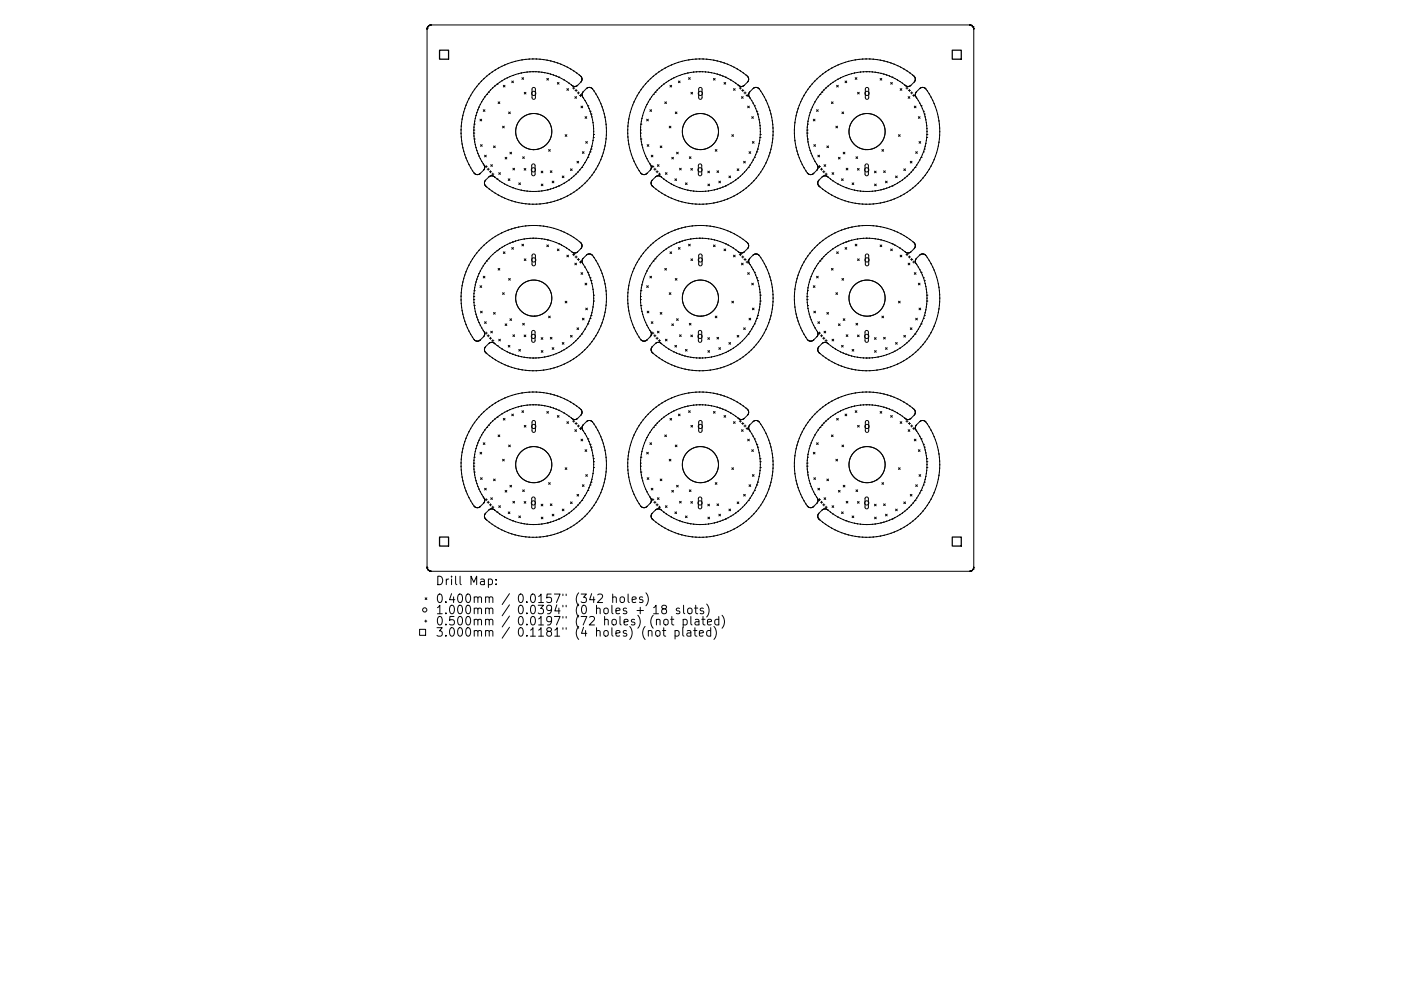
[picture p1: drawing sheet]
<svg xmlns="http://www.w3.org/2000/svg" width="297mm" height="210mm" viewBox="0 0 297 210" stroke-linecap="round" stroke-linejoin="round" font-family="sans-serif">
<defs><g id="words">
<g font-size="2.5">
<text x="92.3" y="124.1">Drill Map:</text>
<text x="92.3" y="127.9">0.400mm / 0.0157&quot; (342 holes)</text>
<text x="92.3" y="130.3">1.000mm / 0.0394&quot; (0 holes + 18 slots)</text>
<text x="92.3" y="132.7">0.500mm / 0.0197&quot; (72 holes) (not plated)</text>
<text x="92.3" y="135.1">3.000mm / 0.1181&quot; (4 holes) (not plated)</text>
</g>
</g></defs>
<g fill="none" stroke="#000" stroke-width=".21">
<path d="M90.5 6.2v114.1M90.5 6.2h.1M90.5 6.1v.1M90.6 6.1h-.1M90.6 6h.1M90.6 6v.1M90.6 5.9v.1M90.6 5.9h.1M90.6 5.8h.1M90.7 5.8h.1M90.7 5.7h.1M90.7 5.7v.1"/>
<path d="M90.7 5.6h.1M90.7 5.6v.1M90.8 5.6h.1M90.9 5.5l-.1 .1M90.9 5.5h.1M90.9 5.4h.1M91 5.4h.1M91.1 5.4h.1M91.1 5.4h-.1M91.2 5.3l-.1 .1M91.2 5.3h.1M91.3 5.3h-.1"/>
<path d="M91.3 5.3h.1M91.4 5.3h.1M91.4 5.3h-.1M91.5 5.3h-.1M100.1 19.7l-.3 .5M100.2 19.7h-.1M100.2 19.6v.1M100.2 19.5v.1M100.6 19l-.4 .5M100.6 19h.1M100.6 18.9v.1M100.7 18.9h-.1"/>
<path d="M102 17.3l-1.3 1.6M102 17.3h.1M102.6 16.7l-.6 .6M102.6 16.7h.1M102.7 16.6l-.1 .1M102.7 16.6h.1M103.6 19.6h.1M103.6 19.6l-.4 .4M103.7 15.7l-1 .9M103.7 15.7h.1M104 19.1l-.4 .5M104 19.1h.1"/>
<path d="M104.5 18.7h.1M104.5 18.7l-.5 .4M104.9 18.2l-.4 .4M104.9 18.2h.1M105.4 17.8h.1M105.4 17.8l-.5 .4M105.6 14.5l-1.9 1.2M105.6 14.5h.1M105.7 14.4l-.1 .1M105.7 14.4h.1M105.9 17.5h.1M105.9 17.5l-.5 .3"/>
<path d="M106.4 17.1l-.5 .4M106.4 17.1h.1M106.5 17.1h.1M106.5 17.1h-.1M106.7 18.1l.4 .4M107 16.8l-.5 .3M107 16.8h.1M107.1 18.1l-.4 .4M107.1 13.7l-1.4 .7M107.1 13.7h.1M107.5 16.5h.1M107.5 16.5l-.5 .3"/>
<path d="M107.6 16.5h-.1M107.6 16.5h.1M107.7 13.5l-.6 .2M107.7 13.5h.1M107.8 13.5h-.1M107.8 13.5h.1M108.1 16.3l-.5 .2M108.1 16.2h.1M108.5 17.2l.4 .3M108.5 13.2l-.7 .3M108.5 13.2h.1M108.7 16h.1"/>
<path d="M108.7 16l-.6 .2M108.9 17.2l-.4 .3M109.1 13l-.6 .2M109.2 13h-.1M109.3 15.8l-.6 .2M109.3 15.8h.1M109.9 12.9l-.7 .1M109.9 15.6l-.6 .2M109.9 15.6h.1M109.9 12.9h.1M110.5 15.5l-.6 .1M110.5 15.5h.1"/>
<path d="M110.6 12.7l-.7 .2M110.6 12.7h.1M110.7 16.5l.3 .3M111 16.5l-.3 .3M111.2 19.6l.3 .3M111.5 12.6l-.9 .1M111.5 19.6l-.3 .3M111.5 12.6h.1M112.1 12.5l-.6 .1M112.2 12.5h-.1M112.4 15.2l-1.9 .3M112.4 15.2h.1"/>
<path d="M112.9 12.5h-.7M112.9 18.7l.4-.1 .2 .3v1.9l-.3 .3-.4-.4zM112.9 12.5h.9M112.9 12.5h.1M113 15.2h.1M113 15.2h-.6M113 15.2h.6M113.6 15.2h.1M113.6 15.2l.7 .1M113.8 12.5h.1M113.8 12.5l.6 .1M114.3 15.3h.1"/>
<path d="M114.3 15.3l1.2 .1M114.4 12.6h.1M114.4 12.6h.8M115.2 12.6h.1M115.2 12.6l.9 .2M115.5 15.4h.1M115.5 15.4l.6 .2M115.9 16.6l.4 .4M116.1 12.8h.1M116.1 12.8l.7 .1M116.1 15.6h.1M116.1 15.6l.6 .1"/>
<path d="M116.3 16.6l-.4 .4M116.7 15.7h.1M116.7 15.7l.6 .2M116.8 12.9h.1M116.8 12.9l.7 .2M117.3 15.9h.1M117.3 15.9l.6 .2M117.5 13.1h.1M117.6 13.1l2 .8M117.9 16.1h.1M117.9 16.1l.6 .3M118.2 17.5l.3 .4"/>
<path d="M118.5 16.4h.1M118.5 16.4l.6 .3M118.5 17.5l-.3 .4M119.1 16.7h.1M119.1 16.7l.5 .3M119.6 13.9h.1M119.6 17h.1M119.6 17l.5 .3M119.7 13.9v.1M119.7 14l.7 .3M120.1 17.3h.1M120.2 17.3h.1"/>
<path d="M120.2 17.3l.5 .3M120.2 18.8l.3 .4M120.4 14.3h.1M120.4 14.3l1.3 .8M120.5 18.8l-.3 .4M120.7 17.6h.1M120.7 17.6v.1M120.7 17.7h.1M120.7 17.7l.5 .3M121.2 18h.1M121.2 18l.1 .2M121.3 18.2h.1"/>
<path d="M121.4 18.7h.5M121.4 18.2l.1 .1M121.5 18.3h.1M121.6 18.3h.1M121.6 18.5v.4M121.7 18.3h.2M121.7 15.1h.1M121.7 15.1l1.1 .8M121.9 19.2h.5M121.9 18.3h.1M122.1 19v.4M122.1 18.3h-.2"/>
<path d="M122.2 18.3h-.1M122.4 19.7h.5M122.4 18.1l-.2 .2M122.5 18.1h-.1M122.6 19.5v.4M122.8 15.9h.1M122.8 15.9l.3 .3M123.1 16.2h.1M123.1 16.2l.2 .2M123.2 17.4l-.7 .7M123.2 17.4h.1M123.3 16.4h.1"/>
<path d="M123.3 16.4v.1M123.3 16.5l.1 .1M123.4 16.6v.1M123.4 17l-.2 .4M123.4 16.9v.1M123.4 16.7v.1M123.4 16.8v.1M123.4 20v.2M123.4 19.9v.1M123.4 19.8v.1M123.5 19.7l-.1 .1M123.6 19.5l-.1 .2"/>
<path d="M123.6 19.5h.1M124.5 18.7l-.9 .8M124.5 18.6v.1M124.7 18.6h-.2M124.7 18.6h.1M124.9 18.5l-.2 .1M125 18.5l.3 .1M125 18.5h-.1M125.3 18.6l.1 .1M125.4 18.7l.5 .5M125.9 19.2h.1M125.9 19.2l.1 .1"/>
<path d="M126 19.3v.1M126 19.4l.3 .5M126.3 19.9h.1M126.3 19.9l.7 1.3M135.5 19.7l-.3 .5M135.5 19.7h.1M135.5 19.6v.1M135.6 19.5l-.1 .1M135.9 19l-.3 .5M135.9 19h.1M137.3 17.3l-1.4 1.7M137.4 17.3h-.1"/>
<path d="M137.4 17.2v.1M137.5 17.2h-.1M138.5 16.2l-1 1M138.5 16.2h.1M138.9 19.6h.1M138.9 19.6l-.4 .4M139.3 19.1l-.4 .5M139.4 19.1h-.1M139.8 15.2l-1.3 1M139.8 15.2h.1M139.8 18.7h.1M139.8 18.7l-.4 .4"/>
<path d="M139.8 18.6h.1M139.8 18.6v.1M140.3 18.2l-.5 .4M140.3 18.2h.1M140.4 14.8l-.6 .4M140.4 14.8h.1M140.7 17.8h.1M140.7 17.8l-.4 .4M140.8 17.8h.1M140.8 17.8h-.1M140.9 14.5l-.5 .3M141 14.5h-.1"/>
<path d="M141.3 17.5h.1M141.3 17.5l-.5 .3M141.6 14.1l-.6 .4M141.6 14.1h.1M141.7 14.1h-.1M141.8 14.1h-.1M141.8 17.1l-.5 .4M141.8 17.1h.1M142 18.1l.4 .4M142.3 13.8l-.5 .3M142.3 16.8l-.5 .3M142.3 13.8h.1"/>
<path d="M142.3 16.8h.1M142.4 18.1l-.4 .4M142.9 16.5h.1M142.9 16.5l-.6 .3M143.1 13.5l-.8 .3M143.2 13.5h-.1M143.4 16.3h.1M143.4 16.3l-.5 .2M143.5 16.2h.1M143.5 16.2l-.1 .1M143.7 13.3l-.5 .2M143.8 13.3h-.1"/>
<path d="M143.8 17.2l.4 .3M144 16h.1M144 16l-.5 .2M144.2 17.2l-.4 .3M144.5 13l-.7 .3M144.5 13h.1M144.6 13h-.1M144.6 13h.1M144.6 15.8l-.6 .2M144.6 15.8h.1M145.2 15.6h.1M145.2 15.6l-.6 .2"/>
<path d="M145.3 12.8l-.7 .2M145.4 12.8h-.1M145.8 15.5l-.6 .1M145.8 15.5h.1M145.9 15.5h.1M145.9 15.5h-.1M146 12.7l-.6 .1M146 12.7h.1M146 16.5l.3 .3M146.3 16.5l-.3 .3M146.5 15.4l-.6 .1M146.5 15.4h.1"/>
<path d="M146.5 19.6l.3 .3M146.7 12.6l-.7 .1M146.7 12.6h.1M146.8 19.6l-.3 .3M147.1 15.3l-.6 .1M147.1 15.3h.1M147.6 12.5l-.9 .1M147.6 12.5h.1M147.7 15.2l-.6 .1M147.7 15.2h.1M148.2 12.5h-.6M148.2 18.7l.4-.1 .3 .3-.1 1.9-.3 .3-.4-.4z"/>
<path d="M148.3 12.5h-.1M148.3 15.2h.1M148.3 15.2h-.6M148.4 15.2h.1M148.4 15.2h-.1M148.4 15.2l1.8 .1M148.4 12.5h-.1M148.4 12.5h.1M148.4 12.5h.6M149 12.5h.1M149 12.5l.9 .1M149.9 12.6h.1"/>
<path d="M149.9 12.6h.6M150.2 15.3h.1M150.2 15.3l.6 .1M150.5 12.6h.1M150.5 12.6l.8 .2M150.8 15.4h.1M150.9 15.4l.5 .2M151.3 16.6l.3 .4M151.3 12.8h.1M151.3 12.8l.7 .1M151.4 15.6h.1M151.5 15.6h.1"/>
<path d="M151.5 15.6l.6 .1M151.6 16.6l-.3 .4M152 12.9h.1M152 12.9l.7 .2M152.1 15.7h.1M152.1 15.7l.6 .2M152.7 15.9h.1M152.7 15.9l1.1 .5M152.7 13.1h.1M152.8 13.1l.8 .3M153.5 17.5l.4 .4M153.6 13.4h.1"/>
<path d="M153.6 13.4l1.4 .5M153.8 16.4h.1M153.8 16.4l.6 .3M153.9 17.5l-.4 .4M154.4 16.7h.1M154.4 16.7l.5 .3M155 17h.1M155 17l.5 .3M155 13.9v.1M155 14l1.9 1M155.5 17.3h.1M155.5 17.3l.5 .3"/>
<path d="M155.5 18.8l.4 .4M155.9 18.8l-.4 .4M156 17.6v.1M156 17.7l.5 .3M156.5 18h.1M156.5 18l.2 .2M156.7 18.2h.1M156.7 18.7h.5M156.8 18.2l.1 .1M156.9 18.3h.1M156.9 15h.1M156.9 15l.6 .4"/>
<path d="M156.9 18.3h.2M157 18.5v.4M157.1 18.3h.1M157.3 19.2h.4M157.5 19v.4M157.5 15.4h.1M157.5 15.4l1.2 1.1M157.7 19.7h.5M158 19.5v.4M158.6 17.3l-.9 .9-.5 .1M158.6 17.3h.1M158.6 17.2v.1"/>
<path d="M158.7 17.1l-.1 .1M158.7 16.5v.1M158.7 16.6v.1M158.7 17v.1M158.7 16.9v.1M158.7 16.7v.1M158.7 16.8v.1M158.7 20v.2M158.7 19.9v.1M158.8 19.8l-.1 .1M158.8 19.7v.1M158.9 19.6l-.1 .1"/>
<path d="M158.9 19.6h.1M159.7 18.8l-.8 .8M159.7 18.7v.1M159.9 18.6l-.2 .1M160 18.6h-.1M160.2 18.6h-.2M160.2 18.5l.2 .1M160.2 18.5v.1M160.4 18.6h.1M160.5 18.6l.4 .2M160.9 18.8h.1M161 18.8v.1"/>
<path d="M161 18.9l.2 .3M161.2 19.2h.1M161.2 19.2l.1 .1M161.3 19.3v.1M161.3 19.4l.3 .5M161.6 19.9h.1M161.7 19.9v.1M161.7 20h.1M170.9 19.6l-1.1 2M170.9 19.5v.1M171.3 18.9l-.4 .6M171.3 18.9h.1"/>
<path d="M172.7 17.3l-1.4 1.6M172.7 17.3h.1M172.8 17.2l-.1 .1M172.8 17.2h.1M173.2 16.7l-.4 .5M173.2 16.7h.1M173.3 16.6l-.1 .1M173.3 16.6h.1M173.8 16.2l-.5 .4M173.8 16.2h.1M174.2 19.6h.1M174.2 19.6l-.3 .4"/>
<path d="M174.3 19.6h-.1M174.3 19.6h.1M174.4 15.7l-.6 .5M174.4 15.7h.1M175.1 18.7l-.8 .9M175.1 18.7h.1M175.6 18.2l-.5 .4M175.6 18.2h.1M175.7 14.8l-1.3 .9M175.8 14.8h-.1M176.1 17.8h.1M176.1 17.8l-.5 .4"/>
<path d="M176.3 14.5l-.5 .3M176.3 14.5h.1M176.4 14.4l-.1 .1M176.4 14.4h.1M176.6 17.5h.1M176.6 17.5l-.5 .3M177.1 14.1l-.7 .3M177.1 14.1h.1M177.1 17.1l-.5 .4M177.1 17.1h.1M177.4 18.1l.3 .4M177.7 16.8l-.6 .3"/>
<path d="M177.7 16.8h.1M177.7 18.1l-.3 .4M177.8 13.7l-.7 .4M177.8 13.7h.1M178.2 16.5l-.5 .3M178.2 16.5h.1M178.3 13.5l-.5 .2M178.4 13.5h-.1M178.8 16.3l-.6 .2M178.8 16.2v.1M179.2 17.2l.3 .3M179.2 13.2l-.8 .3"/>
<path d="M179.2 13.2h.1M179.4 16h.1M179.4 16l-.6 .2M179.5 17.2l-.3 .3M179.9 13l-.7 .2M179.9 13h.1M180 15.8l-.6 .2M180 15.8h.1M180.6 15.6h.1M180.6 15.6l-.6 .2M180.7 12.8l-.8 .2M180.7 12.8h.1"/>
<path d="M181.2 15.5l-.6 .1M181.2 15.5h.1M181.3 16.5l.4 .3M181.4 12.7l-.7 .1M181.4 12.7h.1M181.7 16.5l-.4 .3M181.8 15.4l-.6 .1M181.8 15.4h.1M181.8 19.6l.4 .3M182.2 12.6l-.8 .1M182.2 19.6l-.4 .3M182.2 12.6h.1"/>
<path d="M182.8 12.5l-.6 .1M182.8 12.5h.1M183.6 18.7l.3-.1 .3 .3v1.9l-.3 .3-.4-.4zM183.7 15.2l-1.9 .2M183.7 15.2h.1M183.7 15.2h.6M183.7 12.5h-.9M183.7 12.5h.1M183.7 12.5h.6M184.3 15.2h.1M184.3 15.2l.6 .1M184.3 12.5h.1"/>
<path d="M184.3 12.5h.2M184.5 12.5h.1M184.5 12.5l.6 .1M184.9 15.3h.1M184.9 15.3h.6M185.1 12.6h.1M185.1 12.6l.9 .1M185.5 15.3h.1M185.6 15.3l1.2 .3M186 12.7h.1M186 12.7l.7 .1M186.6 16.6l.4 .4"/>
<path d="M186.7 12.8h.1M186.8 12.8l.5 .1M186.8 15.6h.1M186.8 15.6l.6 .1M187 16.6l-.4 .4M187.3 12.9h.1M187.4 12.9h.1M187.4 15.7h.1M187.4 15.7l.6 .2M187.5 12.9h.1M187.5 12.9l.7 .2M188 15.9h.1"/>
<path d="M188 15.9l.6 .2M188.2 13.1h.1M188.2 13.1l.7 .3M188.6 16.1h.1M188.6 16.1l.6 .3M188.8 17.5l.4 .4M188.9 13.4h.1M189 13.4l1.2 .5M189.2 16.4h.1M189.2 16.4l.5 .3M189.2 17.5l-.4 .4M189.7 16.7h.1"/>
<path d="M189.7 16.7l.6 .3M190.2 13.9h.1M190.2 13.9l.8 .4M190.3 17h.1M190.3 17l.5 .3M190.8 17.3h.1M190.8 17.3l.5 .3M190.8 18.8l.4 .4M191 14.3h.1M191.1 14.3l1.1 .7M191.2 18.8l-.4 .4M191.3 17.6h.1"/>
<path d="M191.3 17.6v.1M191.3 17.7h.1M191.3 17.7l.5 .3M191.8 18h.1M191.8 18l.5 .3M192.1 18.7h.4M192.2 15h.1M192.2 15l.1 .1M192.3 18.5v.4M192.3 18.3h.1M192.3 15.1h.1M192.4 15.1l.5 .3"/>
<path d="M192.4 18.3h.2M192.6 19.2h.4M192.6 18.3h.1M192.8 19v.4M192.9 18.3h-.3M192.9 15.4h.1M192.9 15.4l.6 .5M192.9 18.3h.1M193.1 19.7h.4M193.1 18.1l-.2 .2M193.1 18.1h.1M193.3 19.5v.4"/>
<path d="M193.5 15.9h.1M193.5 15.9l.4 .3M193.8 17.4l-.7 .7M193.9 17.4h-.1M193.9 16.2v.1M193.9 16.3v.1M193.9 16.4h.1M194 16.4l.1 .3M194 17.2l-.1 .2M194 17.1v.1M194 17v.1M194.1 16.9l-.1 .1"/>
<path d="M194.1 16.7v.1M194.1 16.8v.1M194.2 19.6l-.1 .6M194.2 19.6h.1M195.1 18.7l-.9 .9M195.1 18.7h.1M195.4 18.6l-.3 .1M195.4 18.6h.1M195.6 18.5l-.2 .1M195.6 18.5h.1M195.7 18.5l.2 .1M195.9 18.6h.1"/>
<path d="M195.9 18.6l.1 .1M196 18.7h.1M196.1 18.7l.5 .6M196.6 19.3l.1 .1M196.7 19.4l.3 .5M197 19.9h.1M197 19.9v.1M197 20h.1M205.5 5.3h-114.1M205.6 5.3h.1M205.7 5.3h.1M205.8 5.3h.1"/>
<path d="M205.8 5.3l.1 .1M205.9 5.4h.1M206 5.4h.1M206.1 5.4h.1M206.1 5.5h.1M206.1 5.5l.1 .1M206.2 5.6h.1M206.3 5.6v.1M206.3 5.7h.1M206.3 5.7v.1M206.4 5.8h.1M206.4 5.8v.1"/>
<path d="M206.4 5.9h.1M206.4 5.9v.1M206.4 6h.1M206.4 6l.1 .1M206.5 6.1h.1M206.5 6.1v.1M206.5 6.2v114.1M206.5 6.2h.1M97.8 27.6v.8M97.8 27.6h.1M97.8 28.4h.1M97.8 27.5v.1"/>
<path d="M97.8 28.4v.6M97.8 27.5h.1M97.8 29h.1M97.8 29l.1 .9M97.8 26.7v.8M97.8 26.7h.1M97.9 26.1l-.1 .6M97.9 26.1h.1M97.9 29.9h.1M97.9 29.9l.1 .7M98 25.3l-.1 .8M98 25.3h.1"/>
<path d="M98 30.6h.1M98 30.6l.1 .8M98.1 24.6l-.1 .7M98.1 24.6h.1M98.1 24.5v.1M98.1 31.4h.1M98.2 24.4l-.1 .1M98.2 31.4l.1 .7M98.3 23.8l-.1 .6M98.3 23.8h.1M98.3 32.1h.1M98.3 32.1l.8 2"/>
<path d="M98.5 23.1l-.2 .7M98.5 23.1h.1M99.1 21.7l-.6 1.4M99.1 34.1v.1M99.1 34.2l.3 .6M99.1 21.7h.1M99.1 21.6v.1M99.1 21.6h.1M99.4 21l-.3 .6M99.4 34.8h.1M99.4 34.8l.3 .7M99.4 21h.1"/>
<path d="M99.4 20.9v.1M99.5 20.9h-.1M99.7 35.5h.1M99.8 35.5v.1M99.8 20.2l-.3 .7M99.8 35.6h.1M99.8 35.6l.7 1.1M99.8 20.2h.1M100.5 27.6v.6M100.5 27.6h.1M100.5 28.2h.1M100.5 28.2l.1 1.3"/>
<path d="M100.5 36.7h.1M100.5 27v.6M100.5 27h.1M100.5 36.7l.2 .2M100.6 26.4l-.1 .6M100.6 29.5h.1M100.6 26.3h.1M100.6 29.5v.6M100.6 30.1h.1M100.6 30.1l.3 1.2M100.7 36.9h.1M100.8 25.1l-.2 1.2"/>
<path d="M100.8 25.1h.1M100.8 36.9v.1M100.8 37h.2M100.9 31.3h.1M100.9 24.5l-.1 .6M100.9 24.5h.1M100.9 31.3l.2 .6M101 37h.1M101 37h.2M101.1 23.9h.1M101.1 31.9h.1M101.1 23.9l-.2 .6"/>
<path d="M101.1 31.9l.2 .6M101.3 37h-.1M101.3 23.3h.1M101.3 32.5h.1M101.3 23.3l-.2 .6M101.3 32.5l.3 .6M101.4 37h-.1M101.5 37h-.1M101.6 33.1h.1M101.6 22.7l-.3 .6M101.6 33.1l.2 .6M101.6 22.7h.1"/>
<path d="M101.6 37h-.1M101.6 36.9v.1M101.8 25.3l.3 .4M101.8 33.7h.1M101.8 22.2l-.2 .5M101.8 22.2h.1M101.8 33.7l.3 .5M101.9 30.7l.3 .3M102.1 34.2h.1M102.1 25.3l-.3 .4M102.1 34.2l.4 .6M102.2 30.7l-.3 .3"/>
<path d="M102.5 21.1l-.7 1.1M102.5 21.1h.1M102.5 23.3l.3 .3M102.5 34.8h.1M102.5 34.8l.2 .3M102.7 35.1h.1M102.7 35.1v.2M102.7 38.9h.1M102.7 38.9l.1 .2M102.7 35.8l-1.1 1.1M102.7 38.7v.2M102.7 38.7h.1"/>
<path d="M102.7 35.8h.1M102.7 32.9l.4 .4M102.7 35.3h.1M102.7 35.3l.1 .2M102.8 39.1v.1M102.8 35.5l-.1 .3M102.8 35.5h.1M102.8 38.5l-.1 .2M102.8 39.2l.1 .2M102.8 38.5h.1M102.8 20.6l-.3 .5M102.8 20.5h.1"/>
<path d="M102.8 23.3l-.3 .3M102.9 35.3h.4M102.9 38.3l-.1 .2M102.9 38.3h.1M102.9 39.4h.1M102.9 39.4l.1 .1M103 39.5h.1M103 39.5l.8 .7M103.1 35.1v.5M103.1 32.9l-.4 .4M103.2 20.1l-.4 .4M103.2 20h.1"/>
<path d="M103.3 35.9h.4M103.5 35.7v.4M103.8 37.4l-.9 .9M103.8 36.4h.4M103.8 37.4h.1M103.9 37.4h-.1M103.9 37.4h.1M104 36.2v.5M104 34.9l.4 .4M104.1 37.3l-.2 .1M104.1 37.3h.1M104.3 36.9h.4"/>
<path d="M104.3 37.3h-.2M104.3 37.3h.1M104.3 37.3l.4 .1M104.4 34.9l-.4 .4M104.5 36.7v.5M104.6 31l.4 .3M104.7 37.4h.1M104.7 37.4l.1 .1M104.8 37.5h.1M104.8 37.5l.1 .1M104.9 37.6h.1M104.9 37.6l.5 .4"/>
<path d="M105 31l-.4 .3M105.4 38h.1M105.4 38l.5 .4M105.6 21.6l.4 .4M105.7 36.6l.4 .4M105.9 38.4h.1M105.9 38.4l.5 .3M106 21.6l-.4 .4M106.1 36.6l-.4 .4M106.4 38.7h.1M106.5 38.7h.1M106.5 38.7l.5 .3"/>
<path d="M106.6 26.8l.3 .3M106.9 26.8l-.3 .3M107 39h.1M107 39l.5 .3M107.1 33.4l.4 .3M107.5 33.4l-.4 .3M107.5 39.3h.1M107.6 39.3l.5 .3M107.8 37.9l.3 .4M107.8 23.8l.4 .3M108.1 32.3l.4 .4M108.1 37.9l-.3 .4"/>
<path d="M108.1 39.6h.1M108.1 39.6l.6 .2M108.2 23.8l-.4 .3M108.5 32.3l-.4 .4M108.7 39.8h.1M108.7 39.8l.6 .2M108.7 35.7l.4 .4M109.1 35.7l-.4 .4M109.3 28.2h.1M109.3 28.2l.4 1.3 .7 1.1M110 38.8l.4 .4M110.4 38.8l-.4 .4"/>
<path d="M110.4 30.6h.1M110.4 30.6l.4 .3M110.8 30.9v.1M110.8 33.3l.4 .3M110.8 31l.5 .3M111.1 35.7l.4 .4M111.2 33.3l-.4 .3M111.3 31.3h.1M111.3 31.3l1 .4M111.5 24.5l-1 .6-.6 .9-.5 1-.1 1.2M111.5 35.7l-.4 .4M111.5 24.5h.1"/>
<path d="M112 24.3l-.5 .2M112 24.3h.1M112.3 24.2l-.3 .1M112.3 31.7h.1M112.4 24.2h-.1M112.7 24.1l-.3 .1M112.8 24.1h.9l.9 .3M112.8 24.1h-.1M112.8 34.9l.4-.1 .2 .3v1.9l-.3 .3-.4-.3zM114.6 31.5l-1.1 .2h-1.1M114.6 24.4h.1M114.6 24.4l1.1 .6"/>
<path d="M114.6 31.5h.1M114.7 36.3l.4 .4M114.8 39.1l.3 .3M115.1 36.3l-.4 .4M115.1 39.1l-.3 .3M115.7 25v.1M115.7 25.1l.8 .9 .4 1M116.2 30.2l-.6 .7-1 .6M116.2 30.2h.1M116.3 31.7l.4 .4M116.3 30.1l-.1 .1M116.4 30l-.1 .1"/>
<path d="M116.4 29.9v.1M116.5 29.9h-.1M116.7 31.7l-.4 .4M116.7 36.2l.3 .4M116.9 27h.1M116.9 27l.1 1.5-.5 1.4M117 36.2l-.3 .4M117.1 38.4l.3 .4M117.3 39.9l-.6 .2M117.3 39.9h.1M117.4 38.4l-.3 .4M117.9 39.7l-.6 .2"/>
<path d="M117.9 39.7h.1M118.5 39.5h.1M118.5 39.5l-.6 .2M118.5 39.4h.1M118.5 39.4v.1M119.1 39.2l-.6 .2M119.1 39.2h.1M119.2 37.3l.4 .4M119.6 37.3l-.4 .4M119.6 38.9l-.5 .3M119.6 38.9h.1M119.8 28.6l.4 .3"/>
<path d="M120.1 38.5h.1M120.1 38.5l-.5 .4M120.2 38.5h.1M120.2 38.5h-.1M120.2 28.6l-.4 .3M120.7 38.2l-.5 .3M120.7 38.2h.1M121 35.8l.3 .4M121.2 37.8h.1M121.2 37.8l-.5 .4M121.3 35.8l-.3 .4M121.6 37.4h.1"/>
<path d="M121.6 37.4l-.4 .4M121.9 20.5l.3 .4M122.2 20.5l-.3 .4M122.3 34.2l.4 .4M122.5 36.5l-.9 .9M122.5 36.5h.1M122.7 34.2l-.4 .4M122.9 20.3h.4M123.1 20v.5M123.2 22.5l.3 .4M123.3 35.5l-.8 1M123.3 35.5h.1"/>
<path d="M123.4 39.5l-1.7 1.3M123.4 39.4v.1M123.4 20.2h.1M123.4 20.2v.2M123.4 20.4h.1M123.5 20.4v.1M123.5 32.2l.3 .3M123.5 20.5h.1M123.5 20.5l.2 .3M123.5 22.5l-.3 .4M123.7 20.8h.1M123.7 35l-.4 .5"/>
<path d="M123.7 20.8l.6 1.1M123.7 35h.1M123.8 32.2l-.3 .3M124 34.5l-.3 .5M124 38.8l-.6 .6M124 24.8l.4 .3M124 34.5h.1M124.1 38.8h-.1M124.2 30l.3 .4M124.3 34l-.3 .5M124.3 21.9h.1M124.3 34h.1"/>
<path d="M124.4 21.9l.2 .5M124.4 33.9h.1M124.4 33.9l-.1 .1M124.4 24.8l-.4 .3M124.5 30l-.3 .4M124.6 38.3l-.5 .5M124.6 38.3h.1M124.6 22.4h.1M124.6 33.4l-.2 .5M124.6 22.4v.1M124.6 22.5h.1M124.6 33.4h.1"/>
<path d="M124.6 22.5l.3 .5M124.9 23h.1M124.9 32.8h.1M124.9 32.8l-.3 .6M124.9 23l.2 .6M125 37.8l-.4 .5M125 37.8h.1M125.1 23.6h.1M125.1 32.2l-.2 .6M125.1 32.2h.1M125.1 23.6l.2 .6M125.3 24.2h.1"/>
<path d="M125.3 31.6l-.2 .6M125.3 31.6h.1M125.3 24.2l.2 .6M125.5 37.2l-.5 .6M125.5 37.2h.1M125.5 24.8h.1M125.5 31h.1M125.5 31l-.2 .6M125.5 24.8l.2 1.2M125.6 30.4l-.1 .6M125.6 30.4h.1M125.7 26h.1"/>
<path d="M125.7 29.8l-.1 .6M125.7 29.8h.1M125.7 26l.1 .7M125.8 29.2h.1M125.8 26.7h.1M125.8 29.2l-.1 .6M125.8 26.7l.1 .6M125.9 27.3h.1M125.9 28.6h.1M125.9 28.6l-.1 .6M125.9 28.5h.1M125.9 27.3v1.2"/>
<path d="M125.9 28.5v.1M126 36.5l-.5 .7M126 36.5h.1M126.3 36l-.3 .5M126.3 35.9v.1M126.7 35.3l-.4 .6M126.7 35.3h.1M127 34.6l-.3 .7M127 21.2h.1M127.1 21.2l.3 .8M127.1 34.6h-.1M127.1 34.5v.1"/>
<path d="M127.1 34.5h.1M127.4 33.9l-.3 .6M127.4 33.9h.1M127.4 22h.1M127.4 22l.2 .6M127.6 22.6h.1M127.6 22.6l.1 .1M127.7 33.1l-.3 .8M127.7 22.7v.1M127.7 33.1h.1M127.7 22.8l.2 .7M127.9 32.5l-.2 .6"/>
<path d="M127.9 32.5h.1M127.9 23.5h.1M127.9 23.5l.2 .6M128.1 31.8l-.2 .7M128.1 24.1h.1M128.1 24.1v.1M128.1 31.7v.1M128.1 24.2h.1M128.1 24.2l.2 .6M128.3 31l-.2 .7M128.3 24.8h.1M128.3 31h.1"/>
<path d="M128.3 24.8v.1M128.3 24.9v.1M128.3 25l.1 .7M128.4 30.3l-.1 .7M128.4 30.3h.1M128.4 25.7h.1M128.4 25.7l.1 .7M128.5 26.4v.1M128.5 29.4l-.1 .9M128.5 29.4h.1M128.5 26.5l.1 .6M128.6 27.1h.1"/>
<path d="M128.6 27.1v.9M128.6 28.6l-.1 .8M128.6 28.6h.1M128.6 28v.6M128.6 28h.1M133.1 27.6v.8M133.1 27.6h.1M133.1 28.4h.1M133.1 27.5v.1M133.1 28.4v.6M133.1 27.5h.1M133.1 29h.1"/>
<path d="M133.1 29l.1 .9M133.1 26.7v.8M133.1 26.7h.1M133.2 26.1l-.1 .6M133.2 26.1h.1M133.2 29.9h.1M133.2 29.9l.1 .7M133.3 25.3l-.1 .8M133.3 25.3h.1M133.3 30.6h.1M133.3 30.6l.2 .8M133.5 24.6l-.2 .7"/>
<path d="M133.5 24.6h.1M133.5 24.5v.1M133.5 31.4h.1M133.5 31.4l.2 .7M133.5 24.4v.1M133.6 23.8l-.1 .6M133.6 23.8h.1M133.7 32.1h.1M133.7 32.1l.2 .7M133.9 23.1l-.3 .7M133.9 23.1h.1M133.9 32.8v.1"/>
<path d="M133.9 32.9l.2 .5M134.1 33.4v.1M134.1 33.5l.1 .1M134.2 33.6h.1M134.2 22.3l-.3 .8M134.2 33.6l.2 .5M134.2 22.3h.1M134.4 34.1v.1M134.4 21.7l-.2 .6M134.4 34.2l.3 .6M134.4 21.7h.1M134.5 21.6l-.1 .1"/>
<path d="M134.5 21.6h.1M134.7 34.8h.1M134.7 21l-.2 .6M134.7 34.8l.4 .8M134.7 21h.1M134.8 20.9l-.1 .1M134.8 20.9h.1M135.1 20.2l-.3 .7M135.1 35.6h.1M135.2 35.6l.7 1.2M135.2 20.2h-.1M135.8 27.6v.6"/>
<path d="M135.8 27.6h.1M135.8 28.2h.1M135.8 28.2v.6M135.8 27h.1M135.8 28.8h.1M135.8 27v.6M135.8 28.8v.1M135.8 28.9h.1M135.8 28.9l.1 .6M135.9 26.4l-.1 .6M135.9 36.8h.1M135.9 26.3h.1"/>
<path d="M135.9 29.5h.1M135.9 29.5l.1 .6M136 30.1h.1M136 30.1l.3 1.2M136 36.8l.1 .1M136.1 36.9h.1M136.1 25.1l-.2 1.2M136.1 25.1h.1M136.1 36.9l.1 .1M136.2 37h.1M136.2 37h.3M136.3 24.5l-.2 .6"/>
<path d="M136.3 31.3h.1M136.3 24.5h.1M136.3 31.3l.1 .6M136.4 23.9h.1M136.4 31.9h.1M136.4 23.9l-.1 .6M136.4 31.9l.3 .6M136.5 37h.1M136.7 32.5h.1M136.7 23.3h.1M136.7 23.3l-.3 .6M136.7 32.5l.2 .6"/>
<path d="M136.7 37h-.2M136.7 37h.1M136.9 33.1h.1M136.9 22.7l-.2 .6M136.9 22.7h.1M136.9 33.1l.3 .6M137.1 25.3l.4 .4M137.1 36.8l-.4 .2M137.1 36.8h.1M137.2 22.2l-.3 .5M137.2 22.2h.1M137.2 33.7h.1"/>
<path d="M137.2 33.7l.3 .5M137.2 30.7l.4 .3M137.5 21.6h.1M137.5 34.2h.1M137.5 21.6l-.3 .6M137.5 25.3l-.4 .4M137.5 34.2l.3 .6M137.6 30.7l-.4 .3M137.8 34.8h.1M137.8 21.1h.1M137.8 21.1l-.3 .5M137.8 23.3l.4 .3"/>
<path d="M137.8 34.8l.3 .5M137.9 36.1l-.8 .7M137.9 36v.1M138 36h-.1M138 35.9v.1M138 38.9h.1M138 38.9l.2 .4M138.1 38.7l-.1 .2M138.1 38.7h.1M138.1 32.9l.3 .4M138.1 35.3h.1M138.1 35.3v.2"/>
<path d="M138.1 35.5l-.1 .4M138.1 35.5h.1M138.1 38.5v.2M138.1 38.5h.1M138.1 20.6l-.3 .5M138.2 20.5h.1M138.2 23.3l-.4 .3M138.2 39.3h.1M138.2 35.3h.4M138.2 39.3l.3 .3M138.3 38.2l-.2 .3M138.3 38.2h.1"/>
<path d="M138.4 35.1v.5M138.4 32.9l-.3 .4M138.5 39.6h.1M138.5 39.6l.1 .1M138.5 20.1l-.3 .4M138.5 20h.1M138.6 39.7h.1M138.6 39.7l1.1 .8M138.6 35.9h.5M138.8 35.7v.4M139 37.5l-.7 .7M139.1 37.5h-.1"/>
<path d="M139.1 36.4h.4M139.3 36.2v.5M139.3 37.3l-.2 .2M139.4 37.3h-.1M139.4 34.9l.3 .4M139.5 37.3h-.1M139.6 37.3h.2M139.6 37.3h-.1M139.6 36.9h.4M139.7 34.9l-.3 .4M139.8 37.3h.1M139.8 36.7v.5"/>
<path d="M139.8 37.3l.5 .3M140 31l.3 .3M140.3 37.6h.1M140.3 37.6l1 .8M140.3 31l-.3 .3M140.9 21.6l.4 .4M141.1 36.6l.3 .4M141.3 38.4h.1M141.3 38.4l.5 .3M141.3 21.6l-.4 .4M141.4 36.6l-.3 .4M141.8 38.7l.5 .3"/>
<path d="M141.8 38.7h.1M141.9 26.8l.3 .3M142.2 26.8l-.3 .3M142.3 39h.1M142.3 39l1.1 .6M142.4 33.4l.4 .3M142.8 33.4l-.4 .3M143.1 37.9l.3 .4M143.2 23.8l.3 .3M143.4 32.3l.4 .4M143.4 39.6h.1M143.4 37.9l-.3 .4"/>
<path d="M143.5 39.6h.1M143.5 39.6l.5 .2M143.5 23.8l-.3 .3M143.8 32.3l-.4 .4M144 39.8h.1M144 39.8l1.2 .4M144.1 35.7l.3 .4M144.4 35.7l-.3 .4M144.7 28.2h.1M144.7 28.2l.2 1.1 .5 .9 .6 .6 1 .6M145.1 26.2l-.3 .9-.1 1.1M145.1 26.2h.1"/>
<path d="M145.3 38.8l.4 .4M145.5 25.6l-.4 .6M145.5 25.5v.1M145.6 25.4l-.1 .1M145.6 25.4h.1M145.7 38.8l-.4 .4M145.9 25.1l-.3 .3M145.9 25.1h.1M146.1 33.3l.4 .3M146.5 35.7l.3 .4M146.5 33.3l-.4 .3M146.8 35.7l-.3 .4"/>
<path d="M147 31.4h.1M147 31.4l.9 .3M147.5 24.2l-.9 .4-.7 .5M147.5 24.2h.1M147.9 24.1l-.4 .1M147.9 31.7h.1M147.9 24.1h1.3M147.9 24.1h.1M148.2 34.9l.3-.1 .3 .3v1.9l-.3 .3-.4-.3zM149.2 31.7h-1.3M149.2 24.1v.1M149.2 24.2l.9 .2"/>
<path d="M149.2 31.7h.1M150.1 36.3l.3 .4M150.1 31.4l-.9 .3M150.1 24.4h.1M150.1 39.1l.4 .3M150.1 24.4l1.2 .9M150.1 31.4h.1M150.4 36.3l-.3 .4M150.5 39.1l-.4 .3M150.9 30.9l-.8 .5M150.9 30.9h.1M151.3 25.3h.1"/>
<path d="M151.3 25.3l.6 .8 .3 .9M151.4 30.4l-.5 .5M151.5 30.3l-.1 .1M151.6 31.7l.4 .4M151.9 29.8l-.4 .5M151.9 29.7v.1M152 31.7l-.4 .4M152 36.2l.4 .4M152.2 27h.1M152.2 27l.1 .3M152.3 27.3v.1M152.3 27.4v1.2l-.4 1.1"/>
<path d="M152.4 36.2l-.4 .4M152.4 38.4l.4 .4M152.7 39.9l-.6 .2M152.7 39.9h.1M152.8 38.4l-.4 .4M153.8 39.5h.1M153.8 39.5l-1.1 .4M154.4 39.2l-.6 .2M154.4 39.2h.1M154.5 37.3l.4 .4M154.9 37.3l-.4 .4M154.9 38.9l-.5 .3"/>
<path d="M155 38.9h.1M155.2 28.6l.3 .3M155.5 38.5l-.5 .4M155.5 38.5h.1M155.5 28.6l-.3 .3M156 38.2l-.5 .3M156 38.2h.1M156.3 35.8l.3 .4M156.5 37.8h.1M156.5 37.8l-.5 .4M156.6 35.8l-.3 .4M157 37.4h.1"/>
<path d="M157 37.4l-.5 .4M157.2 20.5l.4 .4M157.4 37l-.4 .4M157.4 37h.1M157.6 20.5l-.4 .4M157.7 34.2l.3 .4M157.9 36.5l-.5 .5M157.9 36.5h.1M158 34.2l-.3 .4M158.2 20.3h.4M158.3 36l-.4 .5M158.3 36h.1"/>
<path d="M158.4 20v.5M158.5 22.5l.4 .4M158.7 35.5h.1M158.7 35.5l-.4 .5M158.7 20.2h.1M158.7 20.2l.1 .2M158.8 20.4h.1M158.8 20.4l.2 .4M158.8 32.2l.4 .3M158.9 22.5l-.4 .4M159 35l-.3 .5M159 20.8h.1"/>
<path d="M159 20.8l.7 1.1M159 35h.1M159.2 32.2l-.4 .3M159.4 34.5l-.4 .5M159.4 38.8l-1.9 1.6M159.4 24.8l.3 .3M159.4 34.5h.1M159.4 38.8h.1M159.5 30l.4 .4M159.7 34l-.3 .5M159.7 34h.1M159.7 21.9h.1"/>
<path d="M159.7 33.9h.1M159.7 21.9l.3 .5M159.7 33.9v.1M159.7 24.8l-.3 .3M159.8 38.4l-.4 .4M159.8 38.4h.1M159.9 30l-.4 .4M159.9 38.3l-.1 .1M159.9 38.3h.1M160 33.4l-.3 .5M160 22.4h.1M160 22.4v.1"/>
<path d="M160 22.5h.1M160 33.4h.1M160 22.5l.2 .5M160.2 23h.1M160.2 32.8h.1M160.2 32.8l-.2 .6M160.2 23l.2 .6M160.4 32.2l-.2 .6M160.5 32.2h.1M160.5 23.6h.1M160.5 23.6l.1 .6M160.6 24.2h.1"/>
<path d="M160.6 31.6l-.1 .6M160.7 24.2h.1M160.7 31.6h.1M160.7 24.2l.1 .6M160.8 24.8h.1M160.8 31h.1M160.8 31l-.1 .6M160.8 24.8l.3 1.2M160.9 37.1l-1 1.2M160.9 37.1h.1M161 30.4l-.2 .6M161 30.4h.1"/>
<path d="M161.1 26h.1M161.1 29.8l-.1 .6M161.1 29.8h.1M161.1 26v.7M161.1 29.2h.1M161.1 26.7h.1M161.1 29.2v.6M161.1 26.7l.1 .6M161.2 27.3h.1M161.2 28.6h.1M161.2 28.6l-.1 .6M161.2 28.5h.1"/>
<path d="M161.2 27.3v1.2M161.2 28.5v.1M161.3 36.5l-.4 .6M161.3 36.5h.1M161.6 36l-.3 .5M161.7 35.9l-.1 .1M161.7 35.8v.1M161.7 20l.4 .6M161.7 35.8h.1M162 35.3l-.3 .5M162 35.3h.1M162.1 20.6v.1"/>
<path d="M162.1 20.7l.6 1.3M162.7 22h.1M162.7 22l.3 .6M163 22.6h.1M163 22.6l.3 .9M163.2 32.5l-1.2 2.8M163.2 32.5h.1M163.3 23.5h.1M163.3 23.5l.1 .6M163.4 24.1h.1M163.4 31.8l-.2 .7M163.4 24.1l.1 .1"/>
<path d="M163.4 31.7v.1M163.5 24.2h.1M163.5 24.2l.1 .7M163.6 24.9v.1M163.6 25l.2 .7M163.7 30.3l-.3 1.4M163.7 30.3h.1M163.8 25.7h.1M163.8 25.7v.7M163.8 29.4l-.1 .9M163.8 26.4v.1M163.8 29.4h.1"/>
<path d="M163.8 26.5l.1 .6M163.9 27.1h.1M163.9 27.1v.9M163.9 28.6l-.1 .8M163.9 28.6h.1M163.9 28v.6M163.9 28h.1M168.4 27.6v.8M168.4 27.6h.1M168.4 27.5v.1M168.4 28.4h.1M168.4 27.5h.1"/>
<path d="M168.4 28.4l.1 .6M168.5 29h.1M168.5 29v.9M168.5 26.7l-.1 .8M168.5 26.7h.1M168.5 29.9h.1M168.5 29.9l.2 .7M168.6 25.3l-.1 1.4M168.6 25.3h.1M168.7 30.6h.1M168.7 30.6l.1 .8M168.8 24.6l-.2 .7"/>
<path d="M168.8 24.6h.1M168.8 31.4h.1M168.8 24.5v.1M168.8 31.4l.4 1.4M168.8 24.4v.1M169 23.8l-.2 .6M169 23.8h.1M169.2 23.1l-.2 .7M169.2 23.1h.1M169.2 32.8v.1M169.2 32.9l.2 .5M169.4 33.4v.1"/>
<path d="M169.4 33.5l.1 .1M169.5 22.3l-.3 .8M169.5 33.6h.1M169.5 22.3h.1M169.5 33.6l.2 .5M169.7 34.1v.1M169.7 21.7l-.2 .6M169.7 34.2l.7 1.3M169.7 21.7h.1M169.8 21.6l-.1 .1M169.8 21.6h.1M170.4 35.5h.1"/>
<path d="M170.4 35.5l.7 1.2M171.1 27.6v.6M171.1 28.2h.1M171.1 27.6h.1M171.1 28.2l.1 1.3M171.1 36.7h.1M171.2 27l-.1 .6M171.2 27h.1M171.2 36.7l.2 .2M171.2 26.4v.6M171.2 29.5h.1M171.2 26.3h.1"/>
<path d="M171.2 29.5l.1 .6M171.3 30.1h.1M171.3 30.1l.3 1.2M171.4 36.9h.1M171.4 36.9l.5 .1M171.4 25.1l-.2 1.2M171.4 25.1h.1M171.6 24.5l-.2 .6M171.6 31.3h.1M171.6 24.5h.1M171.6 31.3l.2 .6M171.8 31.9h.1"/>
<path d="M171.8 23.9l-.2 .6M171.8 23.9h.1M171.8 31.9l.4 1.2M172 37h-.1M172 23.3l-.2 .6M172 23.3h.1M172.1 37h-.1M172.2 37h-.1M172.2 33.1h.1M172.2 22.7l-.2 .6M172.2 22.7h.1M172.2 33.1l.3 .6"/>
<path d="M172.3 36.9l-.1 .1M172.3 36.9h.1M172.4 25.3l.4 .4M172.5 33.7h.1M172.5 22.2l-.3 .5M172.5 22.2h.1M172.5 33.7l.3 .5M172.5 30.7l.4 .3M172.8 34.2h.1M172.8 25.3l-.4 .4M172.8 34.2l.3 .6M172.9 30.7l-.4 .3"/>
<path d="M173.1 21.1l-.6 1.1M173.1 34.8h.1M173.1 21.1h.1M173.1 23.3l.4 .3M173.1 34.8l.2 .3M173.3 36l-1 .9M173.3 35.1h.1M173.3 35.9v.1M173.3 35.1l.1 .2M173.4 38.9h.1M173.4 38.9v.2M173.4 35.8l-.1 .1"/>
<path d="M173.4 38.7v.2M173.4 38.7h.1M173.4 35.8h.1M173.4 32.9l.4 .4M173.4 35.3h.1M173.4 35.3v.2M173.4 39.1v.1M173.4 35.5v.3M173.4 35.5h.1M173.4 39.2l.2 .2M173.5 20.6l-.4 .5M173.5 20.5h.1"/>
<path d="M173.5 23.3l-.4 .3M173.5 35.3h.5M173.5 38.3l-.1 .4M173.6 38.3h-.1M173.6 39.4h.1M173.6 39.4l.2 .2M173.7 35.1v.5M173.8 32.9l-.4 .4M173.8 39.6h.1M173.8 39.6l.1 .1M173.8 20.1l-.3 .4M173.9 20h.1"/>
<path d="M173.9 39.7h.1M173.9 39.7l.6 .5M174 35.9h.4M174.2 35.7v.4M174.4 37.4l-.8 .9M174.4 36.4h.5M174.5 37.4h-.1M174.6 37.4h-.1M174.6 37.3v.1M174.7 36.2v.5M174.7 34.9l.4 .4M174.8 37.3h-.2"/>
<path d="M174.8 37.3h.2M174.8 37.3h.1M174.9 36.9h.5M175 37.3h.1M175.1 34.9l-.4 .4M175.1 37.3h.1M175.2 36.7v.5M175.2 37.3l.1 .1M175.3 37.4h.1M175.3 31l.4 .3M175.4 37.4h.1M175.4 37.4l.2 .2"/>
<path d="M175.6 37.6h.1M175.6 37.6l.5 .4M175.7 31l-.4 .3M176.1 38h.1M176.1 38l.5 .4M176.3 21.6l.3 .4M176.4 36.6l.4 .4M176.6 38.4h.1M176.6 38.4l.5 .3M176.6 21.6l-.3 .4M176.8 36.6l-.4 .4M177.1 38.7h.1"/>
<path d="M177.1 38.7l.6 .3M177.2 26.8l.4 .3M177.6 26.8l-.4 .3M177.7 39h.1M177.7 39l.5 .3M177.8 33.4l.3 .3M178.1 33.4l-.3 .3M178.2 39.3h.1M178.2 39.3l.6 .3M178.4 37.9l.4 .4M178.5 23.8l.4 .3M178.8 32.3l.3 .4"/>
<path d="M178.8 39.6h.1M178.8 37.9l-.4 .4M178.8 39.6l.6 .2M178.9 23.8l-.4 .3M179.1 32.3l-.3 .4M179.4 39.8h.1M179.4 39.8l.6 .2M179.4 35.7l.4 .4M179.8 35.7l-.4 .4M180 28.2h.1M180 28.2l.3 1.3 .8 1.1M180.4 26.2l-.3 .9-.1 1.1"/>
<path d="M180.4 26.2h.1M180.7 38.8l.3 .4M180.9 25.4l-.5 .8M181 25.4h-.1M181 38.8l-.3 .4M181.1 30.6h.1M181.1 30.6l.5 .5M181.5 33.3l.3 .3M181.6 31.1h.1M181.7 31.1l.1 .1M181.8 31.2h.1M181.8 35.7l.4 .4"/>
<path d="M181.8 31.2l1.3 .5h1.2M181.8 33.3l-.3 .3M182.2 35.7l-.4 .4M183.5 34.9l.4-.1 .2 .3v1.9l-.3 .3-.4-.3zM184.3 24.1h-.9l-.9 .2-.8 .5-.7 .6M184.3 24.1h.1M184.4 24.1l1.1 .3 .9 .6 .7 .9 .4 1.1M184.4 31.7h-.1M184.7 31.6l-.3 .1M184.7 31.6h.1M185.1 31.5l-.4 .1M185.1 31.5h.1"/>
<path d="M185.4 36.3l.4 .4M185.4 39.1l.4 .3M185.8 31.2l-.7 .3M185.8 36.3l-.4 .4M185.8 39.1l-.4 .3M185.8 31.2h.1M185.9 31.1l-.1 .1M186 31.1h-.1M186.1 31l-.1 .1M186.1 31h.1M186.5 30.7l-.4 .3M186.5 30.6v.1"/>
<path d="M186.8 30.4l-.3 .2M186.8 30.3v.1M186.9 30.2l-.1 .1M186.9 30.2h.1M187 31.7l.3 .4M187 30.1l-.1 .1M187 30v.1M187.1 29.9l-.1 .1M187.1 29.9h.1M187.2 29.8l-.1 .1M187.2 29.7v.1M187.3 31.7l-.3 .4"/>
<path d="M187.3 36.2l.4 .4M187.5 27h.1M187.6 27v.3M187.6 27.3v.1M187.6 27.4v1.2l-.4 1.1M187.7 36.2l-.4 .4M187.7 38.4l.4 .4M188 39.9l-.6 .2M188 39.9h.1M188.1 38.4l-.4 .4M188.6 39.7l-.6 .2M188.6 39.7h.1"/>
<path d="M189.2 39.5h.1M189.2 39.5l-.6 .2M189.7 39.2l-.5 .2M189.7 39.2h.1M189.9 37.3l.3 .4M190.2 37.3l-.3 .4M190.3 38.9l-.6 .3M190.3 38.9h.1M190.5 28.6l.4 .3M190.8 38.5l-.5 .4M190.8 38.5h.1M190.9 28.6l-.4 .3"/>
<path d="M191.3 38.2l-.5 .3M191.3 38.2h.1M191.6 35.8l.4 .4M191.8 37.8h.1M191.8 37.8l-.5 .4M192 35.8l-.4 .4M192.3 37.4h.1M192.3 37.4l-.5 .4M192.5 20.5l.4 .4M192.8 37l-.5 .4M192.8 37h.1M192.9 20.5l-.4 .4"/>
<path d="M193 34.2l.4 .4M193.2 36.5l-.4 .5M193.2 36.5h.1M193.4 34.2l-.4 .4M193.5 20.3h.5M193.6 39.9l-.7 .5M193.6 39.8v.1M193.6 36l-.4 .5M193.6 36h.1M193.7 20v.5M193.9 22.5l.3 .4M194 35.5h.1"/>
<path d="M194 35.5l-.4 .5M194 39.5l-.4 .3M194.1 39.4l-.1 .1M194.1 20.2h.1M194.1 20.2v.2M194.1 20.4h.1M194.1 20.4l.1 .1M194.1 32.2l.4 .3M194.2 20.5h.1M194.2 20.5l.2 .3M194.2 22.5l-.3 .4M194.4 20.8h.1"/>
<path d="M194.4 35l-.4 .5M194.4 35h.1M194.4 20.8l.6 1.1M194.5 32.2l-.4 .3M194.7 34.5l-.3 .5M194.7 24.8l.4 .3M194.7 34.5h.1M194.9 30l.3 .4M195 34l-.3 .5M195 34h.1M195 21.9h.1M195 33.9h.1"/>
<path d="M195 33.9v.1M195 21.9l.3 .5M195.1 24.8l-.4 .3M195.1 38.4l-1 1M195.2 38.4h-.1M195.2 30l-.3 .4M195.3 22.4h.1M195.3 33.4l-.3 .5M195.3 22.4v.1M195.3 22.5h.1M195.3 33.4h.1M195.3 22.5l.3 .5"/>
<path d="M195.6 23h.1M195.6 32.8h.1M195.6 32.8l-.3 .6M195.6 23l.2 .6M195.6 37.8l-.4 .6M195.7 37.8h-.1M195.8 32.2l-.2 .6M195.8 32.2h.1M195.8 23.6h.1M195.8 23.6l.2 .6M196 24.2h.1M196 31.6h.1"/>
<path d="M196 31.6l-.2 .6M196 24.2l.2 .6M196.1 37.2l-.4 .6M196.1 37.2h.1M196.2 31l-.2 .6M196.2 24.8h.1M196.2 31h.1M196.2 24.8l.2 1.2M196.2 37.1l-.1 .1M196.2 37.1h.1M196.3 30.4l-.1 .6M196.3 30.4h.1"/>
<path d="M196.4 26h.1M196.4 29.8l-.1 .6M196.4 29.8h.1M196.4 26l.1 .7M196.5 29.2h.1M196.5 29.2l-.1 .6M196.5 26.7h.1M196.5 26.7v.6M196.5 27.3h.1M196.5 28.6h.1M196.5 28.6v.6M196.5 28.5h.1"/>
<path d="M196.5 27.3v1.2M196.5 28.5v.1M196.6 36.5l-.4 .6M196.7 36.5h-.1M197 36l-.3 .5M197 35.9v.1M197 35.8v.1M197.1 20l.3 .6M197.1 35.8h-.1M197.4 20.6v.1M197.4 20.7l.3 .5M197.7 34.6l-.6 1.2"/>
<path d="M197.7 21.2h.1M197.7 34.6h.1M197.7 21.2l.4 .8M197.8 34.5l-.1 .1M197.8 34.5h.1M198 33.9l-.2 .6M198 33.9h.1M198.1 22h.1M198.1 22l.2 .6M198.3 22.6h.1M198.3 22.6v.1M198.3 33.1l-.3 .8"/>
<path d="M198.3 22.7l.1 .1M198.4 22.8l.2 .7M198.4 33.1h-.1M198.5 32.5l-.1 .6M198.6 32.5h-.1M198.6 23.5h.1M198.6 23.5l.2 .6M198.8 31.8l-.2 .7M198.8 24.1h.1M198.8 24.1l.1 .7M198.8 31.7v.1M198.9 24.8h.1"/>
<path d="M198.9 31l-.1 .7M198.9 24.8l.1 .1M198.9 31h.1M199 24.9v.1M199 25l.1 .7M199.1 30.3l-.2 .7M199.1 30.3h.1M199.1 25.7h.1M199.1 25.7l.1 .7M199.2 29.4l-.1 .9M199.2 26.4v.1M199.2 29.4h.1"/>
<path d="M199.2 26.5v.6M199.2 27.1h.1M199.2 27.1v.9M199.2 28.6v.8M199.2 28.6h.1M199.2 28v.6M199.2 28h.1M98.1 59.8l-.1 .7M98.2 59.8h-.1M98.3 59.1l-.1 .7M98.3 59v.1M99.1 57l-.8 2"/>
<path d="M99.1 57h.1M99.4 56.3l-.3 .7M99.4 56.3h.1M99.7 55.7l-.3 .6M99.8 55.6l-.1 .1M99.8 55.6h.1M99.8 55.5v.1M100.1 55l-.3 .5M100.2 55h-.1M100.6 54.4l-.4 .6M100.6 54.4h.1M100.6 54.3v.1"/>
<path d="M100.7 54.3h-.1M100.9 59.8l-.3 1.2M100.9 59.8h.1M101 53.8l-.3 .5M101 53.7v.1M101.1 59.2h.1M101.1 59.2l-.2 .6M101.3 58.7h.1M101.3 58.7l-.2 .5M101.3 58.6v.1M101.3 58.6h.1M101.5 53.2l-.5 .5"/>
<path d="M101.5 53.2h.1M101.6 58.1h.1M101.6 58.1l-.3 .5M101.6 53.1l-.1 .1M101.6 53.1h.1M101.8 57.5l-.2 .6M101.8 57.5h.1M102.1 57l-.3 .5M102.1 56.9v.1M102.5 56.4h.1M102.5 56.4l-.4 .5M102.5 58.6l.3 .4"/>
<path d="M102.6 52.1l-1 1M102.6 52.1h.1M102.8 55.9l-.3 .5M102.8 55.9h.1M102.8 58.6l-.3 .4M103.2 55.4l-.4 .5M103.2 55.4h.1M103.6 54.9h.1M103.6 54.9l-.4 .5M103.8 51l-1.2 1.1M103.8 40.2h.1M103.8 40.2l1.2 .8"/>
<path d="M103.8 51h.1M104 54.4l-.4 .5M104 54.4h.1M104.5 54h.1M104.5 54l-.5 .4M104.9 53.6l-.4 .4M104.9 53.6h.1M105 50.2l-1.2 .8M105 41h.1M105 41l.6 .4M105 50.2h.1M105.4 53.2l-.5 .4"/>
<path d="M105.4 53.2h.1M105.6 56.9l.4 .4M105.6 41.4h.1M105.6 49.8l-.6 .4M105.6 41.4l1.5 .7M105.6 49.8h.1M105.9 52.8l-.5 .4M105.9 52.8h.1M106 56.9l-.4 .4M106.4 52.5l-.5 .3M106.4 52.5h.1M106.5 52.5h.1"/>
<path d="M106.5 52.5h-.1M106.7 53.4l.4 .4M107 52.1l-.5 .4M107 52.1h.1M107.1 53.4l-.4 .4M107.1 49.1l-1.5 .7M107.1 42.1h.1M107.1 49.1h.1M107.1 42.1l.7 .3M107.5 51.9l-.5 .2M107.6 51.8l-.1 .1M107.8 48.8l-.7 .3"/>
<path d="M107.8 42.4h.1M107.8 42.4l.7 .2M107.8 48.8h.1M107.8 59.1l.4 .3M108.1 51.6l-.5 .2M108.1 51.6h.1M108.2 59.1l-.4 .3M108.5 52.5l.4 .4M108.5 48.6l-.7 .2M108.5 42.6h.1M108.5 48.5v.1M108.5 42.6l.6 .2"/>
<path d="M108.7 51.4h.1M108.7 51.4l-.6 .2M108.9 52.5l-.4 .4M109.1 42.8h.1M109.1 48.4l-.6 .1M109.2 42.8l.7 .2M109.2 48.4h-.1M109.3 40h.1M109.3 51.1l-.6 .2M109.3 51.1h.1M109.3 40l.6 .2M109.9 48.2l-.7 .2"/>
<path d="M109.9 43h.1M109.9 40.2h.1M109.9 51h.1M109.9 51l-.6 .1M109.9 43l1.6 .2M109.9 48.2h.1M109.9 40.2l.6 .1M110.5 40.3h.1M110.5 50.8l-.6 .2M110.5 50.8h.1M110.5 40.3l1.9 .3M110.7 51.8l.3 .4"/>
<path d="M111 51.8l-.3 .4M111.2 54.9l.3 .4M111.3 59.9l-.5 .3M111.3 59.9h.1M111.5 47.9l-1.6 .3M111.5 43.2h.1M111.5 54.9l-.3 .4M111.5 47.9h.1M111.5 43.2l.6 .1M112.1 43.3h.1M112.1 47.9h-.6M112.2 43.3h.7"/>
<path d="M112.2 47.9h-.1M112.3 59.5l-1 .4M112.4 40.6h.1M112.4 50.6l-1.9 .2M112.4 59.5h-.1M112.4 59.5l1.1-.1 1.1 .3M112.4 50.6h.1M112.4 40.6h.6M112.9 47.8l-.7 .1M112.9 43.3h.1M112.9 54l.4-.1 .2 .3v1.9l-.3 .3-.4-.3zM112.9 47.8l.9 .1"/>
<path d="M112.9 47.8h.1M113 40.6h.1M113 50.5h.1M113 50.5l-.6 .1M113 50.5h.6M113.6 50.5v.1M113.6 40.6h-.6M113.6 40.6h.1M113.6 50.6h.7M113.8 43.3h-.9M113.8 47.9h.1M113.8 43.3h.1"/>
<path d="M113.8 47.9l1.4 .1M114.3 50.6h.1M114.3 40.6h-.7M114.3 40.6h.1M114.3 50.6l1.2 .2M114.4 43.3h-.6M114.4 43.3h.1M114.6 59.7h.1M114.6 59.7l1 .6 .6 .6M115.2 48h.1M115.2 48l.9 .1M115.5 40.4l-1.2 .2"/>
<path d="M115.5 50.8h.1M115.5 40.4h.1M115.5 50.8l.6 .1M115.9 52l.4 .3M116.1 43.1l-1.7 .2M116.1 48.1h.1M116.1 43.1h.1M116.1 48.1l.7 .2M116.1 40.3l-.6 .1M116.1 50.9h.1M116.1 40.3h.1M116.1 50.9l.6 .1"/>
<path d="M116.3 52l-.4 .3M116.7 40.1h.1M116.7 40.1l-.6 .2M116.7 51v.1M116.7 51.1l.6 .1M116.8 48.3h.1M116.8 48.3l.7 .2M117.3 51.2h.1M117.3 51.2l.6 .3M117.5 42.7l-1.4 .4M117.5 48.5h.1M117.6 42.7h-.1"/>
<path d="M117.6 48.5l.5 .2M117.9 51.5h.1M117.9 51.5l.6 .2M118.1 42.5l-.5 .2M118.1 48.7h.1M118.2 48.7l.8 .3M118.2 42.5h-.1M118.2 52.8l.3 .4M118.5 51.7h.1M118.5 51.7l.6 .3M118.5 52.8l-.3 .4M119 49h.1"/>
<path d="M119 49l.6 .2M119.1 52h.1M119.1 52l.5 .3M119.6 49.2h.1M119.6 41.9l-1.4 .6M119.6 41.9h.1M119.6 49.2l.1 .1M119.6 52.3h.1M119.6 52.3l.5 .3M119.7 41.9h-.1M119.7 49.3h.1M119.7 41.9h.1"/>
<path d="M119.7 49.3l.5 .3M120.1 52.6h.1M120.2 52.6h.1M120.2 52.6l.5 .4M120.2 54.1l.3 .4M120.2 49.6h.1M120.2 41.6l-.5 .3M120.3 49.6h.1M120.3 41.6h-.1M120.4 41.5l-.1 .1M120.4 49.6h.1M120.4 49.6l1.3 .8"/>
<path d="M120.4 41.5h.1M120.5 54.1l-.3 .4M120.7 53h.1M120.7 53l.5 .4M121.2 53.4h.1M121.2 53.4l.2 .2M121.4 54h.5M121.4 53.6h.1M121.5 53.6l.1 .1M121.6 53.7h.1M121.6 53.8v.4M121.7 53.7h.2"/>
<path d="M121.7 40.8l-1.3 .7M121.7 50.4h.1M121.7 50.4l1.2 .9M121.7 40.8h.1M121.9 55.8l.3 .4M121.9 54.5h.5M121.9 53.7h.1M122.1 54.3v.4M122.1 53.6l-.2 .1M122.2 53.6h-.1M122.2 55.8l-.3 .4M122.3 53.6h-.1"/>
<path d="M122.3 53.5v.1M122.4 55h.5M122.6 54.8v.5M122.9 55.6h.4M122.9 51.3h.1M122.9 51.3l.3 .2M123.1 55.4v.4M123.2 51.5v.1M123.2 57.8l.3 .4M123.2 51.6h.1M123.2 51.6l.1 .1M123.3 51.7v.1"/>
<path d="M123.3 52.6l-1 .9M123.3 52.6h.1M123.3 51.8h.1M123.3 51.8l.1 .2M123.3 52.4v.2M123.4 52.4h-.1M123.4 52h.1M123.4 52v.2M123.4 52.2v.2M123.4 55.4v.1M123.4 55.5l.1 .3M123.4 52.2h.1"/>
<path d="M123.5 55.8h.1M123.5 55l-.1 .4M123.5 55.8v.1M123.5 55h.1M123.5 55.9h.1M123.5 57.8l-.3 .4M123.5 54.9v.1M123.6 55.9l.1 .2M123.6 54.9h-.1M123.7 56.1h.1M123.7 56.1l.3 .6M124 56.7h.1"/>
<path d="M124 56.7l.3 .5M124.3 57.2h.1M124.4 57.2h.1M124.4 57.2l.2 .6M124.4 54.1l-.8 .8M124.4 54.1h.1M124.6 57.8h.1M124.6 57.8l.3 .5M124.7 53.9l-.3 .2M124.7 53.9h.1M124.9 58.3h.1M124.9 58.4l.2 .5"/>
<path d="M124.9 53.9h-.2M125 53.9h-.1M125 53.9h.2M125.1 58.9h.1M125.1 58.9l.2 .6M125.2 53.9h.1M125.2 53.9l.3 .2M125.3 59.5h.1M125.3 59.5l.2 .6M125.5 54.1h.1M125.5 54.1l.5 .6M126 54.7h.1"/>
<path d="M126 54.7l.7 1.2M126.7 55.9h.1M126.7 55.9l.3 .6M127 56.5l.1 .1M127.1 56.6v.1M127.1 56.7h.1M127.1 56.7l.3 .5M127.4 57.2v.1M127.4 57.3l.3 .8M127.7 58.1h.1M127.7 58.1l.2 .6M127.9 58.7h.1"/>
<path d="M127.9 58.7l.2 .7M128.1 59.4h.1M128.1 59.4l.2 .7M133.5 59.8l-.2 .7M133.5 59.8h.1M133.7 59.1l-.2 .7M133.7 59v.1M133.9 58.3l-.2 .7M133.9 58.3h.1M134.1 57.7l-.2 .6M134.1 57.7h.1M134.4 57l-.3 .7"/>
<path d="M134.4 57h.1M134.7 56.3l-.3 .7M134.7 56.3h.1M135.1 55.6l-.4 .7M135.2 55.5l-.1 .1M135.5 55l-.3 .5M135.5 55h.1M135.9 54.4l-.4 .6M135.9 54.4h.1M136.3 59.8l-.3 1.2M136.3 59.8h.1M136.4 53.7l-.5 .7"/>
<path d="M136.4 59.2h.1M136.4 59.2l-.1 .6M136.4 53.6v.1M136.7 58.7h.1M136.7 58.7l-.3 .5M136.7 58.6v.1M136.7 58.6h.1M136.8 53.2l-.4 .4M136.8 53.2h.1M136.9 58.1h.1M136.9 58.1l-.2 .5M136.9 53.1l-.1 .1"/>
<path d="M136.9 53.1h.1M137.2 57.5l-.3 .6M137.2 57.5h.1M137.5 57h.1M137.5 57l-.3 .5M137.5 56.9h.1M137.5 56.9v.1M137.8 56.4l-.3 .5M137.8 58.6l.4 .4M137.8 56.4h.1M138.1 55.9l-.3 .5M138.2 55.9h.1"/>
<path d="M138.2 58.6l-.4 .4M138.5 51.6l-1.6 1.5M138.5 51.5v.1M138.5 55.4l-.3 .5M138.5 55.4h.1M138.6 51.5h-.1M138.6 51.5h.1M138.9 54.9h.1M138.9 54.9l-.4 .5M139.3 54.4l-.4 .5M139.3 54.4h.1M139.7 50.6l-1.1 .9"/>
<path d="M139.7 40.5v.1M139.7 40.6l.6 .4M139.7 50.6h.1M139.8 54h.1M139.8 54l-.4 .4M140.3 53.6l-.5 .4M140.3 53.6h.1M140.3 50.2l-.6 .4M140.3 41h.1M140.3 50.2h.1M140.4 50.1l-.1 .1M140.4 41h.1"/>
<path d="M140.4 50.1h.1M140.4 41l.5 .4M140.9 56.9l.4 .4M140.9 41.4h.1M140.9 49.8l-.5 .3M141 41.4l.6 .3M141 49.8h-.1M141.3 52.8l-1 .8M141.3 52.8h.1M141.3 56.9l-.4 .4M141.6 49.5l-.6 .3M141.6 41.7h.1"/>
<path d="M141.6 41.7l.1 .1M141.6 49.4v.1M141.7 41.8h.1M141.7 49.4h-.1M141.8 41.8l.5 .2M141.8 49.4h-.1M141.8 52.5l-.5 .3M141.8 52.5h.1M142 53.4l.4 .4M142.3 49.1l-.5 .3M142.3 42h.1M142.3 52.1l-.5 .4"/>
<path d="M142.3 42l.8 .4M142.3 49.1h.1M142.3 52.1h.1M142.4 53.4l-.4 .4M143.1 48.8l-.8 .3M143.1 42.4h.1M143.2 48.8h-.1M143.2 42.4l.5 .2M143.2 59.1l.3 .3M143.4 51.6h.1M143.4 51.6l-1.1 .5M143.5 51.6h.1"/>
<path d="M143.5 51.6h-.1M143.5 59.1l-.3 .3M143.7 48.6l-.5 .2M143.7 42.6h.1M143.8 42.6l.7 .2M143.8 48.6h-.1M143.8 52.5l.4 .4M144 51.4h.1M144 51.4l-.5 .2M144 51.3v.1M144 51.3h.1M144.2 52.5l-.4 .4"/>
<path d="M144.5 48.4l-.7 .2M144.5 42.8h.1M144.5 48.4h.1M144.6 42.8h.1M144.6 48.3l-.1 .1M144.6 48.3h.1M144.6 42.8l.7 .2M145.2 51l-1.2 .3M145.2 40.2h.1M145.2 51h.1M145.2 40.2l.6 .1M145.3 48.2l-.7 .1"/>
<path d="M145.3 43h.1M145.4 43l2.2 .3M145.4 48.2h-.1M145.8 40.3h.1M145.8 50.8l-.6 .2M145.8 50.8h.1M145.9 50.8h.1M145.9 40.3h.1M145.9 50.8h-.1M145.9 40.3l.6 .2M146 51.8l.3 .4M146.3 51.8l-.3 .4"/>
<path d="M146.5 40.5h.1M146.5 50.7l-.6 .1M146.5 50.7h.1M146.5 40.5h.6M146.5 54.9l.3 .4M146.7 47.9l-1.3 .3M146.7 47.9h.1M146.8 54.9l-.3 .4M147 59.7l-1.2 .9-.9 1.2M147 59.7h.1M147.1 50.6l-.6 .1M147.1 40.5h.1"/>
<path d="M147.1 50.6h.1M147.1 40.5l.6 .1M147.6 47.9h-.9M147.6 43.3h.1M147.6 47.9h.1M147.6 43.3h.6M147.7 40.6h.1M147.7 50.6h-.6M147.7 50.6h.1M147.7 40.6h.6M147.9 59.5l-.9 .2M147.9 59.5h1.3"/>
<path d="M147.9 59.5h.1M148.2 47.8l-.6 .1M148.2 43.3h.1M148.2 54l.4-.1 .3 .3-.1 1.9-.3 .3-.4-.3zM148.3 47.8h-.1M148.3 43.3h.1M148.3 40.6h.1M148.3 50.5h.1M148.3 50.5l-.6 .1M148.4 50.5h.1M148.4 40.6h.1M148.4 50.5h-.1"/>
<path d="M148.4 50.5l1.8 .2M148.4 43.3h.1M148.4 47.8h-.1M148.4 47.8h.1M148.4 47.8h.6M149 40.6h.1M149 40.6h-.6M149 47.8h.1M149 43.3h-.6M149 43.3h.1M149 47.8l.9 .1M149.2 59.5h.1"/>
<path d="M149.2 59.5l.9 .3M149.9 43.3h-.9M149.9 47.9h.1M149.9 43.3h.1M149.9 47.9l.6 .1M150.1 59.8h.1M150.1 59.8l.8 .5M150.2 40.5l-1.2 .1M150.2 50.7h.1M150.2 50.7l.6 .1M150.2 40.5h.1M150.5 48h.1"/>
<path d="M150.5 48l.8 .1M150.8 40.4l-.6 .1M150.8 50.8h.1M150.9 40.4h-.1M150.9 50.8l.5 .1M151.3 52l.3 .3M151.3 43.1l-1.4 .2M151.3 48.1h.1M151.3 43.1h.1M151.3 48.1l.7 .1M151.4 50.9h.1M151.4 40.3l-.5 .1"/>
<path d="M151.4 40.3h.1M151.5 50.9h.1M151.5 40.3h.1M151.5 40.3h-.1M151.5 50.9l.6 .1M151.6 52l-.3 .3M152 42.9l-.7 .2M152 48.2h.1M152 48.2l.7 .2M152 42.9h.1M152.1 40.1l-.6 .2M152.1 51h.1"/>
<path d="M152.1 40.1h.1M152.1 51.1l.6 .1M152.7 51.2h.1M152.7 51.2l1.1 .5M152.7 48.4h.1M152.7 42.7l-.7 .2M152.8 48.4l.7 .3M152.8 42.7h-.1M153.5 48.7h.1M153.5 42.5l-.7 .2M153.5 42.5h.1M153.5 52.8l.4 .4"/>
<path d="M153.6 48.7h.1M153.6 42.5h-.1M153.6 48.7l1.4 .6M153.6 42.5h.1M153.8 51.7h.1M153.8 51.7l.6 .3M153.9 52.8l-.4 .4M154.2 42.2l-.6 .3M154.2 42.2h.1M154.4 52h.1M154.4 52l.5 .3M155 52.3h.1"/>
<path d="M155 52.3l.5 .3M155 41.9l-.8 .3M155 49.3h.1M155 49.3l1.2 .6M155 41.9h.1M155.5 52.6h.1M155.5 52.6l.5 .4M155.5 54.1l.4 .4M155.9 54.1l-.4 .4M156 53h.1M156 53l.5 .4M156.2 41.2l-1.2 .7"/>
<path d="M156.2 49.9h.1M156.3 49.9l1.2 .9M156.3 41.2h-.1M156.4 41.2h-.1M156.4 41.2h.1M156.5 53.4h.1M156.5 53.4l.1 .1M156.6 53.5h.1M156.6 53.5l.3 .1M156.7 54h.5M156.9 53.6h.1M156.9 53.6l.2 .1"/>
<path d="M157 53.8v.4M157.1 53.7h.1M157.2 55.8l.4 .4M157.3 54.5h.4M157.4 53.7h-.2M157.4 53.6v.1M157.5 54.3v.4M157.5 40.4l-1.1 .8M157.5 50.8h.1M157.5 50.8l.9 .7M157.5 40.4h.1M157.6 53.6h-.2"/>
<path d="M157.6 55.8l-.4 .4M157.6 53.6h.1M157.7 53.5l-.1 .1M157.7 55h.5M157.8 53.5h-.1M157.8 53.5h.1M157.8 53.4v.1M158 54.8v.5M158.2 55.6h.4M158.4 55.4v.4M158.4 51.5h.1M158.5 51.5l.1 .1"/>
<path d="M158.5 57.8l.4 .4M158.5 52.7l-.7 .7M158.6 52.7h-.1M158.6 51.6v.1M158.6 51.7l.1 .1M158.7 51.8h.1M158.7 51.8v.4M158.7 52.4l-.1 .3M158.7 52.4h.1M158.7 52.2v.2M158.7 55.4v.1M158.7 55.5l.1 .1"/>
<path d="M158.7 52.2h.1M158.7 55.2v.2M158.8 55.6v.1M158.8 55.2h-.1M158.8 55.7v.1M158.8 55.8h.1M158.8 55.8l.2 .3M158.9 57.8l-.4 .4M159 56.1h.1M159 56.1l.4 .6M159.4 56.7h.1M159.4 56.7l.3 .5"/>
<path d="M159.7 57.2h.1M159.7 57.2l.3 .6M159.8 54l-1 1.2M159.8 54h.1M160 57.8h.1M160 57.8l.2 .5M160.2 53.9l-.4 .1M160.2 53.9h.2M160.2 53.9h.1M160.2 58.3h.1M160.2 58.4l.2 .5M160.4 53.9h.1"/>
<path d="M160.5 58.9h.1M160.5 58.9l.1 .6M160.5 53.9h.1M160.6 53.9l.1 .1M160.7 59.5h.1M160.7 59.5l.1 .6M160.7 54h.1M160.8 54h.1M160.8 54l.5 .7M161.3 54.7h.1M161.3 54.7l.4 .6M161.7 55.3h.1"/>
<path d="M161.7 55.3l.3 .6M162 55.9h.1M162 55.9l1.2 2.8M163.2 58.7h.1M163.2 58.7l.2 .7M163.4 59.4h.1M163.4 59.4l.3 1.5M168.8 59.8l-.1 .7M168.8 59.8h.1M169.2 58.3l-.4 1.5M169.2 58.3h.1M169.4 57.7l-.2 .6"/>
<path d="M169.4 57.7h.1M169.7 57l-.3 .7M169.7 57h.1M170.4 55.7l-.7 1.3M170.4 55.6v.1M171.3 54.3l-.9 1.3M171.3 54.3h.1M171.6 59.8l-.3 1.2M171.6 59.8h.1M171.7 53.8l-.4 .5M171.7 53.7v.1M171.8 53.7h-.1"/>
<path d="M171.8 59.2h.1M171.8 59.2l-.2 .6M171.8 53.6v.1M172.2 53.2l-.4 .4M172.2 53.2h.1M172.2 58.1l-.4 1.1M172.2 58.1h.1M172.3 53.1l-.1 .1M172.3 53.1h.1M172.5 57.5l-.3 .6M172.5 57.5h.1M172.8 57l-.3 .5"/>
<path d="M172.8 56.9v.1M173.1 56.4h.1M173.1 56.4l-.3 .5M173.1 58.6l.4 .4M173.2 52.1l-.9 1M173.2 52.1h.1M173.5 55.9l-.4 .5M173.5 55.9h.1M173.5 58.6l-.4 .4M173.8 51.6l-.6 .5M173.8 51.5v.1M173.8 55.4l-.3 .5"/>
<path d="M173.9 55.4h.1M173.9 51.5h-.1M173.9 51.5h.1M174.2 54.9h.1M174.2 54.9l-.3 .5M174.3 54.9h-.1M174.3 54.9h.1M174.5 51l-.6 .5M174.5 40.2h.1M174.5 40.2l1.2 .8M174.5 51h.1M174.7 54.4l-.4 .5"/>
<path d="M174.7 54.4h.1M175.1 54h.1M175.1 54l-.4 .4M175.6 53.6l-.5 .4M175.6 53.6h.1M175.7 50.1l-1.2 .9M175.7 41h.1M175.8 41l.5 .4M175.8 50.1h-.1M176.1 53.2l-.5 .4M176.1 53.2h.1M176.3 56.9l.3 .4"/>
<path d="M176.3 49.8l-.5 .3M176.3 41.4h.1M176.3 41.4l.8 .4M176.3 49.8h.1M176.6 52.8h.1M176.6 52.8l-.5 .4M176.6 56.9l-.3 .4M177.1 49.4l-.8 .4M177.1 41.8h.1M177.1 41.8l.7 .3M177.1 49.4h.1M177.1 52.5l-.5 .3"/>
<path d="M177.1 52.5h.1M177.4 53.4l.3 .4M177.7 52.1l-.6 .4M177.7 52.1h.1M177.7 53.4l-.3 .4M177.8 42.1h.1M177.8 49.1l-.7 .3M177.8 42.1l1.4 .5M177.8 49.1h.1M178.2 51.9l-.5 .2M178.2 51.8v.1M178.5 59.1l.4 .3"/>
<path d="M178.8 51.6h.1M178.8 51.6l-.6 .2M178.9 59.1l-.4 .3M179.2 52.5l.3 .4M179.2 48.6l-1.4 .5M179.2 42.6h.1M179.2 42.6l.7 .2M179.2 48.5v.1M179.4 51.4h.1M179.4 51.4l-.6 .2M179.5 52.5l-.3 .4M179.9 48.3l-.7 .2"/>
<path d="M179.9 42.8h.1M179.9 42.8l.8 .2M179.9 48.3h.1M180 51.1l-.6 .2M180 40h.1M180 51.1h.1M180 40l.6 .2M180.6 40.2h.1M180.6 51h.1M180.6 51l-.6 .1M180.6 40.2l.6 .1M180.7 48.2l-.8 .1"/>
<path d="M180.7 43h.1M180.7 43l.7 .1M180.7 48.2h.1M181.2 50.8l-.6 .2M181.2 40.3h.1M181.2 50.8h.1M181.2 40.3l.6 .2M181.3 51.8l.4 .4M181.4 48l-.7 .2M181.4 43.1h.1M181.4 43.1l.8 .1M181.4 48h.1"/>
<path d="M181.7 51.8l-.4 .4M181.8 40.5h.1M181.8 50.7l-.6 .1M181.8 40.5l1.9 .1M181.8 50.7h.1M181.8 54.9l.4 .4M181.8 60h.1M182.2 43.2h.1M182.2 47.9l-.8 .1M182.2 54.9l-.4 .4M182.2 43.2l.6 .1M182.2 47.9h.1"/>
<path d="M182.8 47.9h-.6M182.8 43.3h.1M182.8 43.3h.9M182.8 47.9h.1M183.6 54l.3-.1 .3 .3v1.9l-.3 .3-.4-.3zM183.7 50.5l-1.9 .2M183.7 50.5h.1M183.7 40.6h.1M183.7 50.5h.6M183.7 47.8l-.9 .1M183.7 43.3h.1M183.7 47.8h.1"/>
<path d="M183.7 47.8h.6M184.3 50.5v.1M184.3 40.6h.1M184.3 40.6h-.6M184.3 50.6h.6M184.3 47.8h.1M184.3 43.3h-.6M184.3 59.5h-1.2l-1.3 .5M184.3 59.5h.1M184.3 43.3h.1M184.3 47.8l.2 .1M184.4 59.5h.3"/>
<path d="M184.5 43.3h-.2M184.5 47.9h.1M184.5 47.9l1.5 .1M184.5 43.3h.1M184.7 59.5h.1M184.7 59.5l.4 .1M184.9 50.6h.1M184.9 40.6h-.6M184.9 40.6h.1M184.9 50.6l.6 .1M185.1 59.6h.1M185.1 43.3h-.6"/>
<path d="M185.1 59.6l.7 .3M185.1 43.3h.1M185.5 50.7h.1M185.5 40.5l-.6 .1M185.6 40.5h-.1M185.6 50.7l1.2 .2M185.8 59.9v.1M185.8 60h.1M186 43.2l-.9 .1M186 48h.1M186 48l.7 .1M186 43.2h.1"/>
<path d="M186.6 52l.4 .3M186.7 43.1l-.7 .1M186.7 48.1h.1M186.8 43.1h-.1M186.8 48.1l.5 .1M186.8 40.3l-1.2 .2M186.8 40.3h.1M186.8 50.9h.1M186.8 50.9l.6 .1M187 52l-.4 .3M187.3 48.2h.1M187.3 42.9l-.5 .2"/>
<path d="M187.4 48.2l.1 .1M187.4 42.9h-.1M187.4 40.1h.1M187.4 40.1l-.6 .2M187.4 51h.1M187.4 51v.1M187.4 51.1h.1M187.4 51.1l.6 .1M187.5 48.3h.1M187.5 42.9h-.1M187.5 42.9h.1M187.5 48.3l.7 .2"/>
<path d="M188 51.2h.1M188 51.2l.6 .3M188.2 48.5h.1M188.2 42.7l-.7 .2M188.2 48.5l.7 .2M188.2 42.7h.1M188.6 51.5h.1M188.6 51.5l.6 .2M188.8 52.8l.4 .4M188.9 42.5l-.7 .2M188.9 48.7h.1M189 48.7l.7 .3"/>
<path d="M189 42.5h-.1M189.2 51.7h.1M189.2 51.7l.5 .3M189.2 52.8l-.4 .4M189.5 42.2l-.5 .3M189.5 42.2h.1M189.7 49h.1M189.7 49l.5 .2M189.7 52h.1M189.7 52l.6 .3M190.2 49.2h.1M190.2 41.9l-.7 .3"/>
<path d="M190.2 49.2l.7 .4M190.2 41.9h.1M190.3 52.3h.1M190.3 52.3l.5 .3M190.8 52.6h.1M190.8 52.6l.5 .4M190.8 54.1l.4 .4M190.9 41.6l-.7 .3M190.9 49.6h.1M190.9 41.6h.1M191 49.6h.1M191 41.5l-.1 .1"/>
<path d="M191.1 49.6l1.2 .8M191.1 41.5h-.1M191.2 54.1l-.4 .4M191.3 53h.1M191.3 53l.5 .4M191.7 41.2l-.6 .3M191.7 41.2h.1M191.8 53.4h.1M191.8 53.4l.2 .1M192 53.5h.1M192.1 53.5v.1M192.1 54h.4"/>
<path d="M192.1 53.6h.1M192.2 53.6l.4 .1M192.3 53.8v.4M192.3 40.8l-.6 .4M192.3 50.4h.1M192.4 40.8h-.1M192.4 50.4l.5 .4M192.5 55.8l.4 .4M192.6 54.5h.4M192.6 53.7h.1M192.8 54.3v.4M192.9 40.4l-.5 .4"/>
<path d="M192.9 50.8h.1M192.9 50.8l.7 .5M192.9 40.4h.1M192.9 55.8l-.4 .4M193 53.6l-.4 .1M193 53.5v.1M193.1 55h.4M193.3 54.8v.5M193.5 55.6h.5M193.6 51.3h.1M193.6 51.3l.4 .5M193.7 55.4v.4"/>
<path d="M193.9 57.8l.3 .4M193.9 52.6l-.9 .9M194 52.6h-.1M194 51.8h.1M194 51.8l.1 .2M194.1 52h.1M194.1 52v.2M194.1 52.2l-.1 .4M194.1 55.4v.1M194.1 55.5v.1M194.1 52.2h.1M194.1 55.2v.2"/>
<path d="M194.1 55.6v.1M194.1 55.2h.1M194.1 55.7v.1M194.1 55.8h.1M194.2 55l-.1 .2M194.2 55.8v.1M194.2 55h.1M194.2 55.9h.1M194.2 57.8l-.3 .4M194.2 55.9l.2 .2M194.3 54.8l-.1 .2M194.3 54.8h.1"/>
<path d="M194.4 56.1h.1M194.4 56.1l.3 .6M194.7 56.7h.1M194.7 56.7l.3 .5M195 54.1l-.7 .7M195 57.2h.1M195 54.1h.1M195 57.2l.3 .6M195.2 54l-.2 .1M195.2 54h.1M195.3 57.8h.1M195.3 57.8l.3 .5"/>
<path d="M195.4 53.9l-.2 .1M195.4 53.9h.1M195.6 58.3h.1M195.6 58.3v.1M195.6 58.4h.1M195.6 58.4l.2 .5M195.6 53.9h-.2M195.6 53.9h.1M195.7 53.9l.3 .1M195.8 58.9h.1M195.8 58.9l.2 .6M196 59.5h.1"/>
<path d="M196 59.5l.2 .6M196 54h.1M196.1 54l.1 .1M196.2 54.1h.1M196.3 54.1v.1M196.3 54.2l.3 .5M196.6 54.7h.1M196.7 54.7l.3 .6M197 55.3h.1M197.1 55.3l.6 1.2M197.7 56.5v.1M197.7 56.6l.1 .1"/>
<path d="M197.8 56.7h.1M197.8 56.7l.2 .5M198 57.2v.1M198 57.3l.3 .8M198.3 58.1h.1M198.4 58.1l.1 .6M198.5 58.7h.1M198.6 58.7l.2 .7M198.8 59.4h.1M198.8 59.4l.1 .7M97.8 63.6h.1M97.8 63.6v.1"/>
<path d="M97.8 63.7h.1M97.8 62.8v.8M97.8 63.7v.7M97.8 62.8h.1M97.8 62.2v.6M97.8 62.2h.1M97.8 64.4v.1M97.8 64.5l.1 .6M97.9 65.1h.1M97.9 65.1l.1 .7M97.9 61.3l-.1 .9M97.9 61.3h.1"/>
<path d="M98 65.8v.1M98 65.9l.1 .7M98 60.5l-.1 .8M98 60.5h.1M98.1 66.6h.1M98.1 66.6v.1M98.1 66.7h.1M98.2 66.7l.1 .6M98.3 67.3h.1M98.3 67.3l.2 .7M98.5 68v.1M98.5 68.1l.6 1.4"/>
<path d="M99.1 69.5h.1M99.1 69.5v.1M99.1 69.6h.1M99.1 69.6l.3 .6M99.4 70.2h.1M99.4 70.2v.1M99.4 70.3h.1M99.5 70.3l.3 .7M99.8 71h.1M99.8 71l.4 .6M100.2 71.6h.1M100.2 71.6l.4 .5"/>
<path d="M100.5 62.9h.1M100.5 63.6h.1M100.5 62.9v.7M100.5 63.6v.6M100.5 64.2h.1M100.5 64.2l.1 .6M100.6 61.7l-.1 1.2M100.6 64.8h.1M100.6 61.7h.1M100.6 64.8v.6M100.6 72.1v.1M100.6 72.2l.2 .1"/>
<path d="M100.6 61.1v.6M100.6 65.4h.1M100.6 65.4v.1M100.6 65.5h.1M100.6 61v.1M100.6 65.5l.2 .5M100.8 66v.1M100.8 66.1l.1 .6M100.8 72.3h.1M100.8 72.3h.2M100.9 66.7h.1M100.9 66.7l.2 .6"/>
<path d="M101 72.3v.1M101 72.4h.2M101.1 67.3h.1M101.1 67.3l.2 .5M101.3 72.4h-.1M101.3 67.8h.1M101.3 67.8v.1M101.3 67.9h.1M101.3 67.9l.3 .5M101.4 72.4h-.1M101.5 72.3l-.1 .1M101.6 68.4h.1"/>
<path d="M101.6 68.4l.2 .6M101.6 72.3h-.1M101.6 72.3h.1M101.7 72.2l-.1 .1M101.8 60.6l.3 .4M101.8 72.2h-.1M101.8 72.2h.1M101.8 69h.1M101.8 69l.7 1.1M101.8 72.1v.1M101.9 66l.3 .4M102.1 60.6l-.3 .4"/>
<path d="M102.2 66l-.3 .4M102.5 70.1h.1M102.5 70.1l.2 .4M102.5 71.5l-.7 .6M102.5 71.4v.1M102.6 71.4h-.1M102.6 71.3v.1M102.7 74.2l.2 .5M102.7 74.1v.1M102.7 70.5v.1M102.7 70.6l.1 .1M102.7 74v.1"/>
<path d="M102.7 68.3l.4 .3M102.7 73.9v.1M102.8 70.7v.1M102.8 70.8l-.2 .5M102.8 73.8l-.1 .1M102.8 73.7v.1M102.9 70.7h.4M102.9 74.7h.1M102.9 74.7l.8 .7M103.1 70.4v.5M103.1 68.3l-.4 .3M103.3 71.2h.4"/>
<path d="M103.5 71v.5M103.7 75.4h.1M103.7 75.4l1.9 1.3M103.8 72.8l-1 .9M103.8 71.8h.4M103.8 72.8h.1M103.9 72.7l-.1 .1M103.9 72.7h.1M104 71.5v.5M104 70.3l.4 .3M104.3 72.3h.4M104.3 72.6l-.4 .1"/>
<path d="M104.3 72.6h.1M104.3 72.6l.2 .1M104.4 70.3l-.4 .3M104.5 72.1v.4M104.5 72.7h.1M104.6 72.7l.2 .1M104.6 66.3l.4 .4M104.8 72.8h.1M104.8 72.8l.1 .1M104.9 72.9h.1M104.9 72.9l.5 .4M105 66.3l-.4 .4"/>
<path d="M105.4 73.3h.1M105.4 73.3l.5 .4M105.6 76.7h.1M105.6 76.7l.1 .1M105.7 76.8h.1M105.7 72l.4 .3M105.7 76.8l1.4 .6M105.9 73.7h.1M105.9 73.7l.5 .3M106.1 72l-.4 .3M106.4 74h.1M106.5 74h.1"/>
<path d="M106.5 74l.5 .4M106.6 62.1l.3 .4M106.9 62.1l-.3 .4M107 74.4h.1M107 74.4l.5 .2M107.1 68.7l.4 .4M107.1 77.4h.1M107.1 77.4l.6 .3M107.5 68.7l-.4 .4M107.5 74.6l.1 .1M107.6 74.7l.5 .2M107.7 77.7h.1"/>
<path d="M107.8 73.3l.3 .3M107.8 77.7h.1M107.8 77.7l.7 .2M108.1 67.6l.4 .4M108.1 73.3l-.3 .3M108.1 74.9h.1M108.1 74.9l.6 .2M108.5 67.6l-.4 .4M108.5 77.9v.1M108.5 78l.6 .1M108.7 75.1h.1M108.7 75.2l.6 .2"/>
<path d="M108.7 71l.4 .4M109.1 71l-.4 .4M109.1 78.1h.1M109.2 78.1l.7 .2M109.3 75.4h.1M109.3 75.4l.6 .1M109.3 63l.1 1.1 .5 1.1 .6 .8 1 .7M109.3 62.9v.1M109.6 61.9l-.3 1M109.6 61.8v.1M109.9 78.3h.1M109.9 75.5h.1"/>
<path d="M109.9 78.3l.7 .2M109.9 75.5l.6 .2M110 74.1l.4 .4M110.4 74.1l-.4 .4M110.4 60.6l-.8 1.2M110.4 60.6h.1M110.5 75.7h.1M110.5 75.7l1.9 .2M110.6 78.5h.1M110.6 78.5l.9 .1M110.8 60.2l-.4 .4M110.8 68.6l.4 .4"/>
<path d="M110.8 60.2h.1M111.1 71.1l.4 .3M111.2 68.6l-.4 .4M111.5 66.7h.1M111.5 71.1l-.4 .3M111.5 66.7l.5 .2M111.5 78.6h.1M111.5 78.6h.6M112 66.9h.1M112 66.9l.3 .1M112.1 78.6h.1M112.2 78.6l.7 .1"/>
<path d="M112.3 67h.1M112.4 75.9h.1M112.4 67l.3 .1M112.4 75.9l.6 .1M112.7 67.1h.1M112.8 70.2l.4-.1 .2 .3v1.9l-.3 .3-.4-.3zM112.9 78.7h.1M113 76h.1M113.6 76h-.6M113.6 76h.1M113.8 78.7h-.9M113.8 78.6v.1"/>
<path d="M114.3 75.9l-.7 .1M114.3 75.9h.1M114.4 78.6h-.6M114.4 78.6h.1M114.6 66.8l-.9 .2-.9 .1M114.6 66.8h.1M114.7 71.6l.4 .4M114.8 74.4l.3 .3M115.1 71.6l-.4 .4M115.1 74.4l-.3 .3M115.5 75.7l-1.2 .2M115.5 75.7h.1"/>
<path d="M115.7 66.1l-1.1 .7M115.7 66.1h.1M116.1 78.4l-1.7 .2M116.1 78.4h.1M116.1 75.6l-.6 .1M116.1 75.6h.1M116.2 60.9v.1M116.2 61l.1 .1M116.3 67.1l.4 .3M116.3 61.1h.1M116.4 61.1v.1M116.4 61.2l.1 .1"/>
<path d="M116.5 61.3l.5 1.4-.1 1.5M116.7 67.1l-.4 .3M116.7 71.6l.3 .3M116.7 75.5h.1M116.7 75.5l-.6 .1M116.9 64.2l-.4 1-.8 .9M116.9 64.2h.1M117 71.6l-.3 .3M117.1 73.8l.3 .3M117.3 75.3l-.6 .1M117.3 75.3h.1M117.4 73.8l-.3 .3"/>
<path d="M117.5 78l-1.4 .4M117.6 78h-.1M117.9 75l-.6 .3M117.9 75h.1M118.1 77.8l-.5 .2M118.2 77.8h-.1M118.5 74.8h.1M118.5 74.8l-.6 .2M119.1 74.5l-.6 .3M119.1 74.5h.1M119.2 72.7l.4 .3M119.6 77.3l-1.4 .5"/>
<path d="M119.6 72.7l-.4 .3M119.6 77.3h.1M119.6 74.2l-.5 .3M119.6 74.2h.1M119.7 77.2l-.1 .1M119.7 77.2h.1M119.8 63.9l.4 .4M120.1 73.9h.1M120.1 73.9l-.5 .3M120.2 73.9h.1M120.2 73.9h-.1M120.2 63.9l-.4 .4"/>
<path d="M120.4 76.9l-.7 .3M120.4 76.9h.1M120.7 73.5l-.5 .4M120.7 73.5h.1M121 71.2l.3 .3M121.2 73.1h.1M121.2 73.1l-.5 .4M121.3 71.2l-.3 .3M121.6 72.7l-.4 .4M121.6 72.7h.1M121.7 76.1l-1.3 .8M121.7 76.1h.1"/>
<path d="M122.3 69.6l.4 .3M122.5 71.8l-.9 .9M122.5 71.8h.1M122.7 69.6l-.4 .3M122.8 75.3l-1.1 .8M122.8 75.3h.1M123.3 70.9l-.8 .9M123.3 70.9h.1M123.4 74.8l-.6 .5M123.4 74.8h.1M123.5 67.5l.3 .4M123.5 74.7l-.1 .1"/>
<path d="M123.5 74.7h.1M123.7 70.4h.1M123.7 70.4l-.4 .5M123.8 67.5l-.3 .4M124 74.2l-.5 .5M124 60.1l.4 .3M124.1 74.2h-.1M124.2 65.4l.3 .3M124.3 69.3l-.6 1.1M124.4 69.3h.1M124.4 60.1l-.4 .3M124.5 65.4l-.3 .3"/>
<path d="M124.6 73.6l-.5 .6M124.6 73.6h.1M124.6 68.7l-.2 .6M124.6 68.7h.1M124.9 68.2h.1M124.9 68.2l-.3 .5M125 73.2l-.4 .4M125 73.1v.1M125.1 67.6l-.2 .5M125.1 67.6h.1M125.3 67h.1M125.3 67l-.2 .6"/>
<path d="M125.5 72.6l-.5 .5M125.5 72.5v.1M125.5 66.4l-.2 .6M125.5 60.1h.1M125.5 66.4h.1M125.5 60.1l.1 .6M125.6 60.7v.1M125.6 60.8l.1 .6M125.7 61.4h.1M125.7 65.1l-.2 1.3M125.7 65.1h.1M125.7 61.4l.1 .6"/>
<path d="M125.8 62h.1M125.8 64.5h.1M125.8 64.5l-.1 .6M125.8 62l.1 .6M125.9 63.9l-.1 .6M125.9 62.6h.1M125.9 63.9h.1M125.9 62.6v1.3M125.9 71.9l-.4 .6M125.9 71.9h.1M126 71.8l-.1 .1M126 71.8h.1"/>
<path d="M126.3 71.3l-.3 .5M126.3 71.3h.1M127.4 69.1l-1.1 2.2M127.4 69.1h.1M127.6 68.6l-.2 .5M127.6 68.5v.1M127.7 68.4l-.1 .1M127.7 68.4h.1M127.9 67.7l-.2 .7M127.9 67.7h.1M128.1 67.1l-.2 .6M128.1 67.1h.1"/>
<path d="M128.1 67v.1M128.1 66.9v.1M128.3 60.1v.1M128.3 60.2l.1 .7M128.3 66.2l-.2 .7M128.3 66.2h.1M128.4 60.9h.1M128.4 60.9l.1 .9M128.4 65.5l-.1 .7M128.4 65.5h.1M128.5 64.7l-.1 .8M128.5 61.8h.1"/>
<path d="M128.5 61.8l.1 1.4M128.5 64.7h.1M128.6 64.1l-.1 .6M128.6 64.1h.1M128.6 63.2h.1M128.6 63.2v.9M133.1 63.6h.1M133.1 63.6v.1M133.1 62.8v.8M133.1 63.7h.1M133.1 63.7v.7M133.1 62.8h.1"/>
<path d="M133.1 62.2v.6M133.1 62.2h.1M133.1 64.4v.1M133.1 64.5l.1 .6M133.2 65.1h.1M133.2 65.1l.1 .7M133.2 61.3l-.1 .9M133.2 61.3h.1M133.3 65.8v.1M133.3 65.9l.2 .7M133.3 60.5l-.1 .8M133.3 60.5h.1"/>
<path d="M133.5 66.6h.1M133.5 66.6v.1M133.5 66.7h.1M133.5 66.7l.1 .6M133.6 67.3h.1M133.6 67.3l.3 .7M133.9 68v.1M133.9 68.1l.3 .8M134.2 68.9h.1M134.2 68.9l.2 .6M134.4 69.5h.1M134.4 69.5l.1 .1"/>
<path d="M134.5 69.6h.1M134.5 69.6l.2 .6M134.7 70.2h.1M134.7 70.2l.1 .1M134.8 70.3h.1M134.8 70.3l.3 .7M135.1 71h.1M135.2 71l.3 .6M135.5 71.6h.1M135.6 71.6l.2 .4M135.8 63.6h.1M135.8 62.9h.1"/>
<path d="M135.8 62.9v.7M135.8 63.6v.6M135.8 62.3h.1M135.8 64.2h.1M135.8 62.3v.6M135.8 64.2l.1 .6M135.8 72l.1 .1M135.9 72.1l.6 .3M135.9 61.7l-.1 .6M135.9 61.7h.1M135.9 64.8h.1M135.9 64.8l.2 1.2"/>
<path d="M136 61.1l-.1 .6M136 61.1h.1M136.1 66v.1M136.1 66.1l.2 .6M136.3 66.7h.1M136.3 66.7l.1 .6M136.4 67.3h.1M136.4 67.3l.3 .5M136.5 72.4h.1M136.7 67.9h.1M136.7 67.9l.2 .5M136.7 72.4h-.2"/>
<path d="M136.7 72.4h.1M136.9 72.3l-.2 .1M136.9 68.4h.1M136.9 68.4l.3 .6M136.9 72.3h.1M137 72.3h-.1M137 72.2v.1M137.1 60.6l.4 .4M137.2 69h.1M137.2 69l.3 .5M137.2 66l.4 .4M137.5 69.5v.1"/>
<path d="M137.5 69.6h.1M137.5 60.6l-.4 .4M137.5 69.6l.3 .5M137.6 66l-.4 .4M137.8 70.1h.1M137.8 70.1l.2 .3M137.8 71.5l-.8 .7M137.9 71.4l-.1 .1M138 70.4h.1M138 70.4l.1 .3M138 71.2l-.1 .2M138 71.2h.1"/>
<path d="M138 74.2l.1 .2M138 74.1v.1M138.1 74l-.1 .1M138.1 74.4h.1M138.1 68.3l.3 .3M138.1 71l-.1 .2M138.1 73.9v.1M138.1 74.4v.2M138.1 71h.1M138.1 70.7v.1M138.1 70.8v.2M138.1 74.6h.1"/>
<path d="M138.2 74.6l.1 .2M138.2 70.7h.4M138.2 73.6l-.1 .3M138.2 73.6h.1M138.3 74.8h.1M138.3 74.8l.2 .1M138.4 70.4v.5M138.4 68.3l-.3 .3M138.5 74.9v.1M138.5 75l1.3 1M138.6 71.2h.5M138.8 71v.5"/>
<path d="M139 72.9l-.8 .7M139 72.9h.1M139 72.8v.1M139.1 72.8h-.1M139.1 71.8h.4M139.2 72.7l-.1 .1M139.2 72.7h.1M139.3 71.5v.5M139.3 72.7h-.1M139.4 72.7h-.1M139.4 70.3l.3 .3M139.5 72.6l-.1 .1"/>
<path d="M139.6 72.6l.2 .1M139.6 72.6h-.1M139.6 72.3h.4M139.7 70.3l-.3 .3M139.8 76h.1M139.8 76l.6 .4M139.8 72.7h.1M139.8 72.1v.4M139.8 72.7h.2M140 72.7h.1M140 66.3l.3 .4M140 72.7l.3 .2"/>
<path d="M140.3 72.9h.1M140.3 72.9l1 .8M140.3 66.3l-.3 .4M140.4 76.4h.1M140.4 76.4l.5 .3M140.9 76.7h.1M141 76.7l.7 .4M141.1 72l.3 .3M141.3 73.7h.1M141.3 73.7l.5 .3M141.4 72l-.3 .3M141.7 77.1h.1"/>
<path d="M141.8 77.1l.5 .3M141.8 74h.1M141.8 74l.5 .4M141.9 62.1l.3 .4M142.2 62.1l-.3 .4M142.3 77.4h.1M142.3 74.4h.1M142.3 77.4l.8 .3M142.3 74.4l1.1 .5M142.4 68.7l.4 .4M142.8 68.7l-.4 .4M143.1 73.3l.3 .3"/>
<path d="M143.1 77.7h.1M143.2 77.7l.5 .2M143.4 67.6l.4 .4M143.4 74.9h.1M143.4 73.3l-.3 .3M143.5 74.9h.1M143.5 74.9l.5 .2M143.7 77.9h.1M143.8 77.9l.7 .2M143.8 67.6l-.4 .4M144 75.1h.1M144 75.1v.1"/>
<path d="M144 75.2h.1M144 75.2l1.2 .3M144.1 71l.3 .4M144.4 71l-.3 .4M144.5 78.1h.1M144.5 78.1l.1 .1M144.6 78.2h.1M144.6 78.2l.7 .1M144.7 63l.1 1.1 .3 .9M144.7 62.9v.1M144.9 61.9l-.2 1M144.9 61.8v.1"/>
<path d="M145.1 65h.1M145.1 65l.4 .6M145.2 75.5h.1M145.2 75.5l.6 .2M145.3 74.1l.4 .4M145.3 78.3h.1M145.4 78.3l.6 .2M145.5 65.6h.1M145.5 65.6l.4 .4M145.7 74.1l-.4 .4M145.8 75.7h.1M145.9 75.7h.1"/>
<path d="M145.9 75.7l.6 .1M145.9 66v.1M145.9 66.1l.7 .5 .9 .3M146 78.5h.1M146 78.5l.7 .1M146.1 68.6l.4 .4M146.5 75.8h.1M146.5 71.1l.3 .3M146.5 75.8l.6 .1M146.5 68.6l-.4 .4M146.7 78.6h.1M146.7 78.6h.9"/>
<path d="M146.8 71.1l-.3 .3M147.1 75.9h.1M147.1 75.9h.6M147.5 66.9v.1M147.5 67h.4M147.6 78.6h.1M147.6 78.6l.6 .1M147.7 75.9h.1M147.7 75.9l.6 .1M147.9 67h.1M148.2 70.2l.3-.1 .3 .3v1.9l-.3 .3-.4-.3zM148.2 78.7h.1"/>
<path d="M148.3 78.7h.1M148.3 76h.1M148.4 76h.1M148.4 78.7h.1M149 78.7h-.6M149 78.7h.1M149.2 67h-1.3M149.2 67h.1M149.9 78.6l-.9 .1M149.9 78.6h.1M150.1 71.6l.3 .4M150.1 66.7l-.9 .3"/>
<path d="M150.1 74.4l.4 .3M150.1 66.7h.1M150.2 75.8l-1.8 .2M150.2 75.8h.1M150.4 71.6l-.3 .4M150.5 74.4l-.4 .3M150.8 75.7l-.6 .1M150.9 75.7h-.1M150.9 60.3h.1M150.9 60.3l.5 .5M151.3 78.4l-1.4 .2M151.3 78.4h.1"/>
<path d="M151.3 65.9l-1.2 .8M151.3 65.8v.1M151.4 60.8h.1M151.4 75.6l-.5 .1M151.4 75.6h.1M151.5 60.8l.4 .6M151.5 75.6h-.1M151.5 75.6h.1M151.6 67.1l.4 .3M151.9 61.4v.1M151.9 61.5l.4 1v1.3M152 67.1l-.4 .3"/>
<path d="M152 71.6l.4 .3M152 78.3l-.7 .1M152 78.3h.1M152.1 75.5h.1M152.1 75.5l-.6 .1M152.2 64.2l-.3 .9-.6 .7M152.2 64.2h.1M152.3 63.8l-.1 .4M152.3 63.8h.1M152.4 71.6l-.4 .3M152.4 73.8l.4 .3M152.7 75.3l-.6 .1"/>
<path d="M152.7 75.3h.1M152.7 78.1l-.7 .2M152.8 73.8l-.4 .3M152.8 78.1h-.1M153.5 77.8l-.7 .3M153.5 77.8h.1M153.6 77.8h-.1M153.6 77.8h.1M153.8 74.8h.1M153.8 74.8l-1.1 .5M154.4 74.5l-.6 .3M154.4 74.5h.1"/>
<path d="M154.5 72.7l.4 .3M154.9 72.7l-.4 .3M154.9 74.2l-.5 .3M154.9 74.2h.1M155 77.2l-1.4 .6M155 77.2h.1M155.2 63.9l.3 .4M155.5 73.9h.1M155.5 73.9l-.5 .3M155.5 63.9l-.3 .4M156 73.5l-.5 .4M156 73.5h.1"/>
<path d="M156.3 71.2l.3 .3M156.5 73.1h.1M156.5 73.1l-.5 .4M156.6 71.2l-.3 .3M156.9 76.2l-1.9 1M156.9 76.2h.1M157.4 72.3l-.9 .8M157.4 72.3h.1M157.5 75.7l-.6 .5M157.5 75.7h.1M157.7 69.6l.3 .3M157.9 71.8l-.5 .5"/>
<path d="M157.9 71.8h.1M158 69.6l-.3 .3M158.3 71.4l-.4 .4M158.3 71.4h.1M158.7 70.9h.1M158.7 70.9l-.4 .5M158.8 67.5l.4 .4M159 70.4h.1M159 70.4l-.3 .5M159.2 67.5l-.4 .4M159.3 74.3l-1.8 1.4M159.3 74.3h.1"/>
<path d="M159.4 74.2l-.1 .1M159.4 60.1l.3 .3M159.4 74.2h.1M159.5 65.4l.4 .3M159.7 69.3l-.7 1.1M159.7 69.3h.1M159.7 60.1l-.3 .3M159.8 73.7l-.4 .5M159.8 73.7h.1M159.9 65.4l-.4 .3M159.9 73.6l-.1 .1M159.9 73.6h.1"/>
<path d="M160 68.7l-.3 .6M160 68.7h.1M160.2 68.2h.1M160.2 68.2l-.2 .5M160.4 73l-.5 .6M160.4 73h.1M160.4 67.6l-.2 .5M160.5 67.6h-.1M160.5 67.6h.1M160.6 67h.1M160.6 67l-.1 .6M160.7 67h.1"/>
<path d="M160.7 67h-.1M160.8 60.1h.1M160.8 66.4l-.1 .6M160.8 66.4h.1M160.8 60.1l.2 .6M160.9 72.4l-.5 .6M160.9 72.4h.1M161 60.7v.1M161 60.8l.1 .6M161.1 61.4h.1M161.1 65.1l-.3 1.3M161.1 65.1h.1"/>
<path d="M161.1 61.4v.6M161.1 62h.1M161.1 64.5v.6M161.1 62l.1 .6M161.1 64.5h.1M161.2 62.6h.1M161.2 63.9l-.1 .6M161.2 63.9h.1M161.2 62.6v1.3M161.2 71.9l-.3 .5M161.2 71.9h.1M161.3 71.8l-.1 .1"/>
<path d="M161.3 71.8h.1M161.6 71.3l-.3 .5M161.7 71.3h-.1M161.7 71.2v.1M161.7 71.2h.1M162.1 70.5l-.4 .7M162.1 70.5h.1M162.7 69.1l-.6 1.4M162.7 69.1h.1M163 68.6l-.3 .5M163 68.5v.1M163.3 67.7l-.3 .8"/>
<path d="M163.3 67.7h.1M163.4 67.1l-.1 .6M163.4 67.1h.1M163.5 67l-.1 .1M163.5 66.9v.1M163.6 66.2l-.1 .7M163.6 66.2h.1M163.7 60.9h.1M163.7 60.9l.1 .9M163.8 65.5l-.2 .7M163.8 65.5h.1M163.8 64.9v.6"/>
<path d="M163.8 64.8v.1M163.8 64.7v.1M163.8 61.8h.1M163.8 61.8l.1 1.4M163.8 64.7h.1M163.9 64.1l-.1 .6M163.9 64.1h.1M163.9 63.2h.1M163.9 63.2v.9M168.4 63.6h.1M168.4 63.6v.1M168.4 62.8v.8"/>
<path d="M168.4 63.7h.1M168.4 62.8h.1M168.4 63.7l.1 .7M168.5 62.2l-.1 .6M168.5 62.2h.1M168.5 64.4v.1M168.5 64.5l.1 1.3M168.5 61.3v.9M168.5 61.3h.1M168.6 65.8v.1M168.6 65.9l.2 .7M168.7 60.5l-.2 .8"/>
<path d="M168.7 60.5h.1M168.8 66.6h.1M168.8 66.6v.1M168.8 66.7h.1M168.8 66.7l.2 .6M169 67.3h.1M169 67.3l.2 .7M169.2 68v.1M169.2 68.1l.3 .8M169.5 68.9h.1M169.5 68.9l.2 .6M169.7 69.5h.1"/>
<path d="M169.7 69.5l.1 .1M169.8 69.6h.1M169.8 69.6l1.1 2M170.9 71.6h.1M170.9 71.6l.4 .5M171.1 62.9h.1M171.1 63.6h.1M171.1 62.9v.7M171.1 63.6l.1 .6M171.2 64.2h.1M171.2 64.2v.6M171.2 61.7l-.1 1.2"/>
<path d="M171.2 64.8h.1M171.2 61.7h.1M171.2 64.8l.1 .6M171.3 72.1v.1M171.3 72.2l.2 .1M171.3 61.1l-.1 .6M171.3 65.4h.1M171.3 65.4v.1M171.3 65.5h.1M171.3 61v.1M171.3 65.5l.1 .5M171.4 66v.1"/>
<path d="M171.4 66.1l.2 .6M171.5 72.3h.1M171.5 72.3l.2 .1M171.6 66.7h.1M171.6 66.7l.2 .6M171.7 72.4h.1M171.7 72.4h.2M171.8 67.3h.1M171.8 67.3l.2 .5M172 72.4h-.1M172 67.8v.1M172 67.9l.2 .5"/>
<path d="M172.1 72.3l-.1 .1M172.2 72.3h-.1M172.2 68.4h.1M172.2 68.4l.3 .6M172.4 72.2l-.2 .1M172.4 60.6l.4 .4M172.4 72.2h.1M172.5 69h.1M172.5 69l.6 1.1M172.5 66l.4 .4M172.8 60.6l-.4 .4M172.9 66l-.4 .4"/>
<path d="M173.1 70.1h.1M173.1 70.1l.2 .3M173.3 71.4l-.9 .8M173.3 71.3v.1M173.3 70.4h.1M173.3 70.4l.1 .1M173.4 74.2v.2M173.4 74.1v.1M173.4 70.5v.1M173.4 70.6v.1M173.4 74.4h.1M173.4 68.3l.4 .3"/>
<path d="M173.4 71l-.1 .3M173.4 74.4l.1 .2M173.4 71h.1M173.4 70.7v.1M173.4 70.8v.2M173.5 74.6h.1M173.5 73.8l-.1 .3M173.5 74.6v.1M173.5 73.7v.1M173.5 70.7h.5M173.5 74.7h.1M173.6 74.7l.2 .2"/>
<path d="M173.7 70.4v.5M173.8 68.3l-.4 .3M173.8 74.9v.1M173.8 75l.6 .4M174 71.2h.4M174.2 71v.5M174.4 75.4h.1M174.4 75.4l1.3 1M174.4 72.8l-.9 .9M174.4 71.8h.5M174.5 72.8h-.1M174.7 71.5v.5"/>
<path d="M174.7 70.3l.4 .3M174.8 72.6l-.3 .2M174.8 72.6l.6 .2M174.8 72.6h.1M174.9 72.3h.5M175.1 70.3l-.4 .3M175.2 72.1v.4M175.3 66.3l.4 .4M175.4 72.8h.1M175.4 72.8l.2 .1M175.6 72.9h.1M175.6 72.9l.5 .4"/>
<path d="M175.7 66.3l-.4 .4M175.7 76.4h.1M175.8 76.4l.5 .3M176.1 73.3h.1M176.1 73.3l.5 .4M176.3 76.7h.1M176.3 76.7l.1 .1M176.4 76.8h.1M176.4 72l.4 .3M176.4 76.8l.7 .3M176.6 73.7h.1M176.6 73.7l.5 .3"/>
<path d="M176.8 72l-.4 .3M177.1 77.1h.1M177.1 77.1l.7 .3M177.1 74h.1M177.1 74l.6 .4M177.2 62.1l.4 .4M177.6 62.1l-.4 .4M177.7 74.4h.1M177.7 74.4l.5 .2M177.8 68.7l.3 .4M177.8 77.4h.1M177.8 77.4l.5 .3"/>
<path d="M178.1 68.7l-.3 .4M178.2 74.6v.1M178.2 74.7l.6 .2M178.3 77.7h.1M178.4 77.7l.8 .2M178.4 73.3l.4 .3M178.8 67.6l.3 .4M178.8 74.9h.1M178.8 73.3l-.4 .3M178.8 74.9l.6 .2M179.1 67.6l-.3 .4M179.2 77.9v.1"/>
<path d="M179.2 78l.7 .2M179.4 75.1h.1M179.4 75.2l.6 .2M179.4 71l.4 .4M179.8 71l-.4 .4M179.9 78.2h.1M179.9 78.2l.8 .1M180 75.4h.1M180 75.4l.6 .1M180 63l.1 1.1 .3 .9M180 62.9v.1M180.3 61.9l-.3 1"/>
<path d="M180.3 61.8v.1M180.4 65h.1M180.4 65l.8 1 .9 .7 1.1 .3h1.1M180.6 75.5h.1M180.6 75.5l.6 .2M180.7 74.1l.3 .4M180.7 78.3h.1M180.7 78.3l1.5 .3M181 74.1l-.3 .4M181.1 60.6l-.8 1.2M181.1 60.6h.1M181.2 75.7h.1"/>
<path d="M181.2 75.7l.6 .1M181.5 68.6l.3 .4M181.6 60.1l-.5 .5M181.7 60.1h-.1M181.8 75.8h.1M181.8 60l-.1 .1M181.8 71.1l.4 .3M181.8 75.8l1.9 .2M181.8 68.6l-.3 .4M182.2 71.1l-.4 .3M182.2 78.6h.1M182.2 78.6h.6"/>
<path d="M182.8 78.6h.1M182.8 78.6l.9 .1M183.5 70.2l.4-.1 .2 .3v1.9l-.3 .3-.4-.3zM183.7 76h.1M183.7 78.7h.1M184.3 76h-.6M184.3 76h.1M184.3 78.7h-.6M184.3 78.7h.1M184.4 67h-.1M184.5 78.7h-.2M184.5 78.6v.1"/>
<path d="M184.9 75.9l-.6 .1M184.9 75.9h.1M185.1 78.6h-.6M185.1 78.6h.1M185.4 71.6l.4 .4M185.4 74.4l.4 .3M185.5 75.8l-.6 .1M185.6 75.8h-.1M185.8 71.6l-.4 .4M185.8 74.4l-.4 .3M185.9 60l.1 .1M186 60.1h.1"/>
<path d="M186 78.5l-.9 .1M186 78.5h.1M186.1 60.1v.1M186.1 60.2l.4 .3M186.5 60.5h.1M186.5 60.5l.3 .3M186.7 78.4l-.7 .1M186.8 78.4h-.1M186.8 60.8h.1M186.8 75.6l-1.2 .2M186.8 75.6h.1M186.8 60.8l.1 .1"/>
<path d="M186.9 60.9v.1M186.9 61l.1 .1M187 67.1l.3 .3M187 61.1h.1M187 61.1l.1 .1M187.1 61.2v.1M187.1 61.3l.1 .1M187.2 61.4v.1M187.2 61.5l.4 1v1.3M187.3 67.1l-.3 .3M187.3 71.6l.4 .3M187.3 78.3l-.5 .1"/>
<path d="M187.4 78.3h-.1M187.4 75.5h.1M187.4 75.5l-.6 .1M187.4 75.4v.1M187.4 75.4h.1M187.5 78.2l-.1 .1M187.5 78.2h.1M187.5 64.2l-.4 1.1-.7 .8-.9 .6-1.1 .3M187.6 64.2h-.1M187.6 63.8v.4M187.6 63.8h.1M187.7 71.6l-.4 .3"/>
<path d="M187.7 73.8l.4 .3M188 75.3l-.6 .1M188 75.3h.1M188.1 73.8l-.4 .3M188.2 78l-.7 .2M188.2 78h.1M188.6 75l-.6 .3M188.6 75h.1M188.9 77.8l-.7 .2M189 77.8h-.1M189.2 74.8h.1M189.2 74.8l-.6 .2"/>
<path d="M189.7 74.5l-.5 .3M189.7 74.5h.1M189.9 72.7l.3 .3M190.2 77.3l-1.2 .5M190.2 72.7l-.3 .3M190.2 77.3h.1M190.3 74.2l-.6 .3M190.3 74.2h.1M190.5 63.9l.4 .4M190.8 73.9h.1M190.8 73.9l-.5 .3M190.9 63.9l-.4 .4"/>
<path d="M191 76.9l-.8 .4M191.1 76.9h-.1M191.3 73.5l-.5 .4M191.3 73.5h.1M191.6 71.2l.4 .3M191.7 76.5l-.6 .4M191.7 76.5h.1M191.8 73.1l-.5 .4M191.8 73.1h.1M192 71.2l-.4 .3M192.2 76.2l-.5 .3M192.2 76.2h.1"/>
<path d="M192.3 72.7l-.5 .4M192.3 72.7h.1M192.3 76.1l-.1 .1M192.4 76.1h-.1M192.8 72.3l-.5 .4M192.8 72.3h.1M192.9 75.7l-.5 .4M192.9 75.7h.1M193 69.6l.4 .3M193.2 71.8l-.4 .5M193.2 71.8h.1M193.4 69.6l-.4 .3"/>
<path d="M193.5 75.3l-.6 .4M193.5 75.3h.1M193.6 71.4l-.4 .4M193.6 71.4h.1M194 70.9l-.4 .5M194 70.9h.1M194 74.8l-.5 .5M194.1 74.8h-.1M194.1 67.5l.4 .4M194.1 74.7v.1M194.2 74.7h-.1M194.4 70.4h.1"/>
<path d="M194.4 70.4l-.4 .5M194.5 67.5l-.4 .4M194.6 74.3l-.4 .4M194.6 74.3h.1M194.7 60.1l.4 .3M194.9 65.4l.3 .3M195 69.3l-.6 1.1M195 69.3h.1M195.1 60.1l-.4 .3M195.1 73.7l-.5 .6M195.2 73.7h-.1M195.2 65.4l-.3 .3"/>
<path d="M195.3 68.7l-.3 .6M195.3 68.7h.1M195.6 68.2h.1M195.6 68.2l-.3 .5M195.6 68.1v.1M195.6 68.1h.1M195.6 73.2l-.4 .5M195.7 73.1l-.1 .1M195.7 73v.1M195.7 73h.1M195.8 67.6l-.2 .5M195.8 67.6h.1"/>
<path d="M196 67h.1M196 67l-.2 .6M196.1 72.6l-.4 .4M196.1 72.5v.1M196.2 60.1h.1M196.2 66.4h.1M196.2 66.4l-.2 .6M196.2 60.1l.1 .6M196.2 72.4l-.1 .1M196.2 72.4h.1M196.3 60.7v.1M196.3 60.8l.1 .6"/>
<path d="M196.4 61.4h.1M196.4 65.1l-.2 1.3M196.4 61.4l.1 .6M196.4 65.1h.1M196.5 64.5l-.1 .6M196.5 62h.1M196.5 64.5h.1M196.5 62v.6M196.5 62.6h.1M196.5 63.9v.6M196.5 63.9h.1M196.5 62.6v1.3"/>
<path d="M196.6 71.8l-.4 .6M196.7 71.8h-.1M197 71.3l-.3 .5M197 71.3h.1M197 71.2v.1M197.1 71.2h-.1M197.4 70.5l-.3 .7M197.4 70.5h.1M198.1 69.1l-.7 1.4M198.1 69.1h.1M198.3 68.6l-.2 .5M198.3 68.5v.1"/>
<path d="M198.3 68.4v.1M198.4 68.4h-.1M198.6 67.7l-.2 .7M198.6 67.7h.1M198.8 67.1l-.2 .6M198.8 67.1h.1M198.9 60.1v.1M198.9 60.2l.2 .7M199 66.2l-.2 .9M199 66.2h.1M199.1 60.9h.1M199.1 60.9l.1 .9"/>
<path d="M199.1 65.5l-.1 .7M199.1 65.5h.1M199.2 64.9l-.1 .6M199.2 64.8v.1M199.2 61.8h.1M199.2 64.7v.1M199.2 61.8v1.4M199.2 64.7h.1M199.2 64.1v.6M199.2 64.1h.1M199.2 63.2h.1M199.2 63.2v.9"/>
<path d="M97.8 98.3v.6M97.8 98.9h.1M97.8 98.9v.7M97.8 98.3h.1M97.8 99.6v.1M97.8 99.7v.1M97.8 99.8h.1M97.8 97.4v.9M97.8 99.8l.1 .7M97.8 97.4h.1M97.9 96.8l-.1 .6M97.9 96.7v.1"/>
<path d="M97.9 96.6v.1M97.9 96.6h.1M98 96l-.1 .6M98 96h.1M98.1 95.3l-.1 .7M98.1 95.2v.1M98.3 94.5l-.2 .7M98.3 94.5h.1M98.5 93.8l-.2 .7M98.5 93.8h.1M99.1 92.2l-.6 1.6M99.1 92.2h.1"/>
<path d="M99.4 91.6l-.3 .6M99.5 91.5l-.1 .1M100.1 90.3l-.6 1.2M100.2 90.3h-.1M100.2 90.2v.1M100.2 90.2h.1M100.5 98.3v.6M100.5 98.3h.1M100.5 98.9h.1M100.5 98.9l.1 1.2M100.5 97.7v.6M100.5 97.6v.1"/>
<path d="M100.6 97h.1M100.6 97l-.1 .6M100.6 89.6l-.4 .6M100.6 96.4h.1M100.6 96.4v.6M100.7 89.6h-.1M100.8 95.8l-.2 .6M100.8 95.8h.1M100.9 95.2l-.1 .6M100.9 95.2h.1M101 89.1l-.3 .5M101 89.1h.1"/>
<path d="M101.1 94.6h.1M101.1 94.6l-.2 .6M101.3 94h.1M101.3 94l-.2 .6M101.5 88.5l-.5 .6M101.5 88.5h.1M101.6 93.4l-.3 .6M101.6 93.4h.1M101.6 88.4l-.1 .1M101.6 88.4h.1M101.8 96l.3 .3M101.8 92.8l-.2 .6"/>
<path d="M101.8 92.8h.1M102 87.9l-.4 .5M102 87.9h.1M102.1 92.3l-.3 .5M102.1 96l-.3 .3M102.1 92.3h.1M102.5 91.7h.1M102.5 91.7l-.4 .6M102.5 93.9l.3 .4M102.6 87.4l-.6 .5M102.6 87.4h.1M102.7 87.3l-.1 .1"/>
<path d="M102.7 87.3h.1M102.8 91.2l-.3 .5M102.8 91.2h.1M102.8 93.9l-.3 .4M103.2 90.7h.1M103.2 90.7l-.4 .5M103.6 90.2h.1M103.6 90.2l-.4 .5M103.7 86.4l-1 .9M103.7 86.4h.1M103.8 86.3l-.1 .1M103.8 86.3h.1"/>
<path d="M104.5 89.3h.1M104.5 89.3l-.9 .9M105 85.5l-1.2 .8M105 85.5h.1M105.4 88.5l-.9 .8M105.4 88.5h.1M105.6 92.3l.4 .3M105.6 85.1l-.6 .4M105.6 85.1h.1M105.7 85.1h-.1M105.7 85.1h.1M105.9 88.1l-.5 .4"/>
<path d="M105.9 88.1h.1M106 92.3l-.4 .3M106.4 87.8l-.5 .3M106.4 87.8h.1M106.5 87.8h.1M106.5 87.8h-.1M106.6 97.4l.3 .4M106.7 88.8l.4 .3M106.9 97.4l-.3 .4M107 87.5l-.5 .3M107 87.5h.1M107.1 88.8l-.4 .3"/>
<path d="M107.5 87.2l-.5 .3M107.6 87.2h-.1M107.7 84.2l-2 .9M107.7 84.2h.1M107.8 84.1l-.1 .1M107.8 84.1h.1M107.8 94.4l.4 .4M108.1 86.9l-.5 .3M108.1 86.9h.1M108.2 94.4l-.4 .4M108.5 87.9l.4 .3M108.7 86.7h.1"/>
<path d="M108.7 86.7l-.6 .2M108.9 87.9l-.4 .3M109.1 83.7l-1.3 .4M109.2 83.7h-.1M109.3 86.5h.1M109.3 86.5l-.6 .2M109.4 98.1l.1 1.7 .9 1.4M109.4 98.1h.1M109.8 96.7l-.4 1.4M109.9 96.7h-.1M109.9 83.5l-.7 .2M109.9 86.3h.1"/>
<path d="M109.9 86.3l-.6 .2M109.9 83.5h.1M109.9 96.5v.2M110 96.5h-.1M110 96.4v.1M110.1 96.3l-.1 .1M110.5 86.2l-.6 .1M110.5 86.2h.1M110.6 83.4l-.7 .1M110.6 83.4h.1M110.7 87.1l.3 .4M110.7 95.7l-.6 .6"/>
<path d="M110.7 95.7h.1M111 87.1l-.3 .4M111.2 90.3l.3 .3M111.3 95.2l-.6 .5M111.3 95.2h.1M111.5 95.2h-.2M111.5 95.1v.1M111.5 83.3l-.9 .1M111.5 90.3l-.3 .3M111.5 83.3h.1M112 94.9l-.5 .2M112 94.9h.1"/>
<path d="M112.1 83.2l-.6 .1M112.2 83.2h-.1M112.3 94.8l-.3 .1M112.4 85.9l-1.9 .3M112.4 94.8h-.1M112.4 85.9h.1M112.7 94.8h-.3M112.8 94.8h.9l.9 .2M112.8 94.8h-.1M112.9 83.2h-.7M112.9 89.3l.4-.1 .2 .3v1.9l-.3 .3-.4-.3zM112.9 83.2h.9"/>
<path d="M112.9 83.2h.1M113 85.9h.1M113 85.9h-.6M113 85.9h.6M113.6 85.9h.1M113.6 85.9h.7M113.8 83.2h.1M113.8 83.2h.6M114.3 85.9h.1M114.3 85.9l1.2 .2M114.4 83.2h.1M114.4 83.2l.8 .1"/>
<path d="M114.6 95h.1M114.6 95l1.1 .7M115.2 83.3h.1M115.2 83.3l.9 .1M115.5 86.1h.1M115.5 86.1l.6 .1M115.7 95.7h.1M115.7 95.7l1 1.4M115.9 87.3l.4 .4M116.1 83.4v.1M116.1 83.5l.7 .1M116.1 86.2h.1"/>
<path d="M116.1 86.2l.6 .2M116.3 87.3l-.4 .4M116.7 97.1h.1M116.7 97.1l.3 .9v.9M116.7 86.4h.1M116.7 86.4l.6 .2M116.8 83.6h.1M116.8 99.7l-.2 .5M116.8 83.6l.7 .2M116.8 99.7h.1M117 99l-.2 .7M117 98.9v.1"/>
<path d="M117.3 86.6h.1M117.3 86.6l.6 .2M117.5 83.8h.1M117.6 83.8l.5 .2M117.9 86.8h.1M117.9 86.8l.6 .2M118.1 84h.1M118.2 84l.8 .3M118.2 88.2l.3 .3M118.5 87h.1M118.5 87v.1M118.5 87.1h.1"/>
<path d="M118.5 87.1l.6 .2M118.5 88.2l-.3 .3M119 84.3h.1M119 84.3l1.2 .6M119.1 87.3h.1M119.1 87.3l.5 .3M119.6 87.6h.1M119.6 87.6l.5 .4M119.8 99.2l.4 .4M120.1 88h.1M120.2 88h.1M120.2 88l.5 .3"/>
<path d="M120.2 89.5l.3 .3M120.2 99.2l-.4 .4M120.2 84.9h.1M120.3 84.9l.1 .1M120.4 85h.1M120.4 85l2.4 1.6M120.5 89.5l-.3 .3M120.7 88.3h.1M120.7 88.3l.5 .4M121.2 88.7h.1M121.2 88.7l.1 .1M121.3 88.8v.1"/>
<path d="M121.3 88.9l.3 .1M121.4 89.4h.5M121.6 89h.1M121.6 89.1v.5M121.7 89h.2M121.9 91.2l.3 .3M121.9 89.9h.5M121.9 89h.1M122.1 89.6v.5M122.1 89h-.2M122.2 88.9l-.1 .1M122.2 91.2l-.3 .3"/>
<path d="M122.3 88.9h-.1M122.3 88.9h.1M122.4 90.4h.5M122.6 90.2v.4M122.8 86.6h.1M122.9 90.9h.4M122.9 86.6v.1M122.9 86.7l.4 .3 .1 .4M123.1 90.7v.5M123.2 93.2l.3 .3M123.2 88l-.9 .9M123.2 88h.1"/>
<path d="M123.4 87.7l-.2 .3M123.4 87.7h.1M123.4 90.7v.2M123.4 87.4v.1M123.4 87.5v.2M123.4 90.7h.1M123.4 90.9h.1M123.4 90.9l.3 .6M123.4 90.5v.2M123.4 90.5h.1M123.5 90.3l-.1 .2M123.5 90.3h.1"/>
<path d="M123.5 93.2l-.3 .3M123.7 91.5h.1M123.7 91.5l.3 .5M124 92h.1M124 95.4l.4 .4M124 92l.3 .5M124.4 92.6h.1M124.4 92.6l.2 .5M124.4 95.4l-.4 .4M124.5 89.3l-1 1M124.5 89.3h.1M124.6 93.1h.1"/>
<path d="M124.6 93.1l.3 .6M124.7 89.3h-.2M124.7 89.2v.1M124.9 93.7h.1M124.9 93.7l.2 .6M124.9 89.2h-.2M125 89.2h.2M125 89.2h-.1M125.1 94.3h.1M125.1 94.3l.2 .6M125.2 89.2v.1M125.2 89.3h.1"/>
<path d="M125.3 94.9h.1M125.3 94.9l.2 .6M125.3 89.3h.1M125.4 89.3l.1 .1M125.5 95.5h.1M125.5 95.5l.1 .6M125.5 89.4h.1M125.5 89.4l.1 .1M125.6 89.5h.1M125.6 89.5l.3 .4M125.6 96.1h.1M125.6 96.1l.2 1.2"/>
<path d="M125.8 97.3h.1M125.8 99.9l-.2 1.2M125.8 99.9h.1M125.8 99.8v.1M125.8 99.8h.1M125.8 97.3l.1 .6M125.9 99.2l-.1 .6M125.9 98h.1M125.9 99.2h.1M125.9 98v.6M125.9 98.6h.1M125.9 98.6v.6"/>
<path d="M125.9 89.9h.1M125.9 89.9l.1 .1M126 90h.1M126 90l.3 .5M126.3 90.5v.1M126.3 90.6l.4 .6M126.7 91.2h.1M126.7 91.2l.4 .8M127.1 92h.1M127.1 92l.3 .7M127.4 92.7h.1M127.4 92.7l.2 .6"/>
<path d="M127.6 93.3h.1M127.6 93.3l.3 .8M127.9 94.1v.1M127.9 94.2l.2 .7M128.1 94.9h.1M128.1 94.9l.2 .7M128.3 95.6h.1M128.3 95.6l.1 .8M128.4 96.4h.1M128.4 96.4l.1 .6M128.5 97h.1M128.5 97l.1 .7"/>
<path d="M128.6 97.7v.1M128.6 97.8v.8M128.6 99.3l-.2 1.6M128.6 99.3h.1M128.6 98.7v.6M128.6 98.6v.1M133.1 98.3v.6M133.1 98.9h.1M133.1 98.9v.7M133.1 98.3h.1M133.1 99.6v.1M133.1 99.7v.1"/>
<path d="M133.1 97.4v.9M133.1 99.8h.1M133.1 99.8l.1 .7M133.1 97.4h.1M133.2 96.8l-.1 .6M133.2 96.7v.1M133.2 96.6v.1M133.2 96.6h.1M133.3 96l-.1 .6M133.3 96h.1M133.5 95.3l-.2 .7M133.5 95.2v.1"/>
<path d="M133.6 94.5l-.1 .7M133.6 94.5h.1M133.9 93.8l-.3 .7M133.9 93.8h.1M133.9 93.7v.1M133.9 93.6v.1M134.2 92.9l-.3 .7M134.2 92.9h.1M134.5 92.2l-.3 .7M134.5 92.2h.1M134.8 91.6l-.3 .6M134.8 91.5v.1"/>
<path d="M135.5 90.3l-.7 1.2M135.5 90.3h.1M135.5 90.2v.1M135.6 90.2h-.1M135.8 98.3v.6M135.8 98.9h.1M135.8 98.3h.1M135.8 98.9v.6M135.8 97.7h.1M135.8 99.5h.1M135.8 97.7v.6M135.8 97.6h.1"/>
<path d="M135.8 99.5l.1 .6M135.8 97.6v.1M135.9 97l-.1 .6M135.9 97h.1M136 96.4h.1M136 96.4l-.1 .6M136.1 95.8l-.1 .6M136.1 95.8h.1M136.3 95.2h.1M136.3 95.2l-.2 .6M136.4 89l-.8 1.2M136.4 94.6h.1"/>
<path d="M136.4 94.6l-.1 .6M136.4 89h.1M136.7 94h.1M136.7 94l-.3 .6M136.8 88.5l-.4 .5M136.8 88.5h.1M136.9 93.4l-.2 .6M136.9 93.4h.1M136.9 88.4l-.1 .1M136.9 88.4h.1M137.1 96l.4 .3M137.2 92.8l-.3 .6"/>
<path d="M137.2 92.8h.1M137.3 87.9l-.4 .5M137.4 87.9h-.1M137.4 87.8v.1M137.5 87.8h-.1M137.5 92.3h.1M137.5 92.3l-.3 .5M137.5 96l-.4 .3M137.8 91.7h.1M137.8 91.7l-.3 .6M137.8 93.9l.4 .4M138.1 91.2l-.3 .5"/>
<path d="M138.2 91.2h.1M138.2 93.9l-.4 .4M138.5 86.9l-1 .9M138.5 86.9h.1M138.5 90.7h.1M138.5 90.7l-.3 .5M138.6 86.8l-.1 .1M138.6 86.8h.1M138.9 90.2h.1M138.9 90.2l-.4 .5M139.7 86l-1.1 .8M139.7 85.9v.1"/>
<path d="M139.8 85.9h-.1M139.8 85.9h.1M139.8 89.3l-.9 .9M139.8 89.3h.1M140.3 88.9l-.5 .4M140.3 88.9h.1M140.3 85.5l-.5 .4M140.3 85.5h.1M140.4 85.5h-.1M140.4 85.5h.1M140.9 92.3l.4 .3M140.9 85.1l-.5 .4"/>
<path d="M141 85.1h-.1M141.3 88.1l-1 .8M141.3 88.1h.1M141.3 92.3l-.4 .3M141.6 84.8l-.6 .3M141.6 84.8h.1M141.8 87.8l-.5 .3M141.8 87.8h.1M141.9 97.4l.3 .4M142 88.8l.4 .3M142.2 97.4l-.3 .4M142.3 87.5l-.5 .3"/>
<path d="M142.3 87.5h.1M142.4 88.8l-.4 .3M143.1 84.1l-1.5 .7M143.2 84.1h-.1M143.2 94.4l.3 .4M143.4 86.9h.1M143.4 86.9l-1.1 .6M143.5 86.9h.1M143.5 86.9h-.1M143.5 94.4l-.3 .4M143.7 83.9l-.5 .2M143.8 83.9h-.1"/>
<path d="M143.8 87.9l.4 .3M144 86.7h.1M144 86.7l-.5 .2M144.2 87.9l-.4 .3M144.5 83.7l-.7 .2M144.5 83.7h.1M144.6 83.7h-.1M144.6 83.7h.1M144.6 86.5h.1M144.6 86.5l-.6 .2M144.7 98.1l.1 1.3 .4 1.1 .8 1 1 .6M144.7 98.1h.1"/>
<path d="M144.8 97.8l-.1 .3M144.8 97.7v.1M144.9 97.4l-.1 .3M144.9 97.4h.1M145.2 96.7l-.3 .7M145.2 96.7h.1M145.2 86.3l-.6 .2M145.2 86.3h.1M145.3 96.5l-.1 .2M145.3 96.5h.1M145.3 83.5l-.7 .2M145.4 83.5h-.1"/>
<path d="M145.5 96.2l-.2 .3M145.5 96.2h.1M145.8 86.2l-.6 .1M145.8 86.2h.1M145.9 86.2h.1M145.9 86.2h-.1M146 83.4l-.6 .1M146 83.4h.1M146 87.1l.3 .4M146.3 87.1l-.3 .4M146.5 86l-.6 .2M146.5 86h.1"/>
<path d="M146.5 90.3l.3 .3M146.7 83.3l-.7 .1M146.7 83.3h.1M146.8 90.3l-.3 .3M147.1 86h-.6M147.1 86h.1M147.5 94.9l-1.2 .5-.8 .8M147.5 94.9h.1M147.6 83.2l-.9 .1M147.6 83.2h.1M147.7 85.9l-.6 .1M147.7 85.9h.1"/>
<path d="M147.9 94.8l-.4 .1M147.9 94.8h.1M147.9 94.8h1.3M148.2 83.2h-.6M148.2 89.3l.4-.1 .3 .3-.1 1.9-.3 .3-.4-.3zM148.3 83.2h-.1M148.3 85.9h.1M148.3 85.9h-.6M148.4 85.9h-.1M148.4 85.9h.1M148.4 85.9l1.8 .1M148.4 83.2h.1"/>
<path d="M148.4 83.2h-.1M148.4 83.2h.6M149 83.2h.1M149 83.2h.9M149.2 94.8h.1M149.2 94.8l.9 .3M149.9 83.2h.1M149.9 83.2l.6 .1M150.1 95.1h.1M150.1 95.1l1.2 .9M150.2 86h.1M150.2 86l.6 .1"/>
<path d="M150.5 83.3h.1M150.5 83.3l.8 .1M150.8 86.1h.1M150.9 86.1l.5 .1M151.3 87.3l.3 .4M151.3 83.4h.1M151.3 83.4l.7 .2M151.3 96h.1M151.3 96l.7 1.1M151.4 86.2h.1M151.5 86.2h.1M151.5 86.2l.6 .2"/>
<path d="M151.6 87.3l-.3 .4M152 83.6h.1M152 97.1h.1M152 83.6l1.5 .4M152 97.1l.3 1.3-.1 1.3M152.1 86.4h.1M152.1 86.4l.6 .2M152.2 99.7l-.2 .5M152.2 99.7h.1M152.7 86.6h.1M152.7 86.6l.5 .2M153.2 86.8h.1"/>
<path d="M153.3 86.8h.1M153.3 86.8l.5 .2M153.5 84h.1M153.5 88.2l.4 .3M153.6 84h.1M153.6 84l2.6 1.3M153.8 87h.1M153.8 87.1l.6 .2M153.9 88.2l-.4 .3M154.4 87.3h.1M154.4 87.3l.5 .3M155 87.6h.1"/>
<path d="M155 87.6l.5 .4M155.2 99.2l.3 .4M155.5 88h.1M155.5 88l.5 .3M155.5 89.5l.4 .3M155.5 99.2l-.3 .4M155.9 89.5l-.4 .3M156 88.3h.1M156 88.3l.5 .4M156.2 85.3h.1M156.3 85.3l.6 .4M156.5 88.7h.1"/>
<path d="M156.5 88.7l.2 .2M156.7 88.9h.1M156.7 89.4h.5M156.8 88.9l.3 .1M156.9 85.7h.1M156.9 85.7l.6 .4M157 89.1v.5M157.1 89h.1M157.2 91.2l.4 .3M157.3 89.9h.4M157.4 89h-.2M157.4 89h.1"/>
<path d="M157.5 89.6v.5M157.5 86.1h.1M157.5 86.1l1 .8M157.6 91.2l-.4 .3M157.7 88.8l-.3 .2M157.7 90.4h.5M157.8 88.8h-.1M158 90.2v.4M158.2 90.9h.4M158.4 90.7v.5M158.5 88.1l-.7 .7M158.5 86.9h.1"/>
<path d="M158.5 88.1h.1M158.5 86.9l.1 .2M158.5 93.2l.4 .3M158.6 87.1h.1M158.6 87.9l-.1 .2M158.7 87.1v.1M158.7 87.8l-.1 .1M158.7 87.2v.1M158.7 87.7v.1M158.7 87.3v.1M158.7 87.7h.1M158.7 90.7v.2"/>
<path d="M158.7 87.4v.1M158.7 87.5v.2M158.7 90.7h.1M158.7 90.9h.1M158.7 90.9l.1 .2M158.8 91.1h.1M158.8 91.1v.1M158.8 90.3l-.1 .4M158.8 91.2h.1M158.9 90.3h-.1M158.9 91.2l.1 .3M158.9 93.2l-.4 .3"/>
<path d="M158.9 90.2v.1M158.9 90.2h.1M159 91.5h.1M159 91.5l.4 .5M159.4 92h.1M159.4 95.4l.3 .4M159.4 92l.3 .5M159.7 89.4l-.8 .8M159.7 92.6h.1M159.7 92.6l.3 .5M159.7 89.4h.1M159.7 95.4l-.3 .4"/>
<path d="M159.9 89.3l-.2 .1M160 93.1h.1M160 93.1l.2 .6M160 89.3h-.1M160.2 89.2l-.2 .1M160.2 89.2h.2M160.2 89.2h.1M160.2 93.7h.1M160.2 93.7l.2 .6M160.4 89.2h.1M160.4 94.3h.1M160.5 94.3h.1"/>
<path d="M160.5 94.3l.1 .6M160.5 89.2l.3 .1M160.7 94.9h.1M160.7 94.9l.1 .6M160.8 89.3v.1M160.8 89.4l.2 .1M160.8 95.5h.1M160.8 95.5l.2 .6M161 89.5h.1M161 96.1h.1M161 96.1l.1 1.2M161 89.5l.2 .4"/>
<path d="M161.1 97.3h.1M161.1 99.9l-.1 1.2M161.1 99.9h.1M161.1 99.8v.1M161.1 97.3l.1 .6M161.1 99.8h.1M161.2 99.2l-.1 .6M161.2 99.2h.1M161.2 98h.1M161.2 98v.6M161.2 98.6h.1M161.2 98.6v.6"/>
<path d="M161.2 89.9h.1M161.2 89.9l.1 .1M161.3 90h.1M161.3 90l.3 .5M161.6 90.5l.1 .1M161.7 90.6l.3 .6M162 91.2h.1M162 91.2l.1 .1M162.1 91.3h.1M162.1 91.3l.6 1.4M162.7 92.7h.1M162.7 92.7l.3 .6"/>
<path d="M163 93.3h.1M163 93.3l.3 .8M163.3 94.1v.1M163.3 94.2l.2 .7M163.5 94.9h.1M163.5 94.9l.1 .7M163.6 95.6h.1M163.6 95.6l.2 .8M163.8 96.4h.1M163.8 96.4v.6M163.8 97h.1M163.8 97l.1 .7"/>
<path d="M163.9 97.7v.1M163.9 97.8v.8M163.9 99.3l-.1 .9M163.9 99.3h.1M163.9 98.7v.6M163.9 98.6v.1M168.4 98.3v.6M168.4 98.9h.1M168.4 98.9l.1 .7M168.4 98.3h.1M168.5 99.6v.1M168.5 99.7v.1"/>
<path d="M168.5 97.4l-.1 .9M168.5 99.8h.1M168.5 99.8v.7M168.5 97.4h.1M168.5 96.6v.8M168.5 96.6h.1M168.6 96l-.1 .6M168.6 96h.1M168.8 95.3l-.2 .7M168.8 95.2v.1M169 94.5l-.2 .7M169 94.5h.1"/>
<path d="M169.2 93.8l-.2 .7M169.2 93.8h.1M169.2 93.7v.1M169.2 93.6v.1M169.5 92.9l-.3 .7M169.5 92.9h.1M169.8 92.2l-.3 .7M169.8 92.2h.1M170.9 90.2l-1.1 2M170.9 90.2h.1M171.1 98.3v.6M171.1 98.3h.1"/>
<path d="M171.1 98.9h.1M171.1 98.9l.1 1.2M171.2 97.7l-.1 .6M171.2 97.6v.1M171.2 97h.1M171.2 97v.6M171.3 89.6l-.4 .6M171.3 96.4h.1M171.3 96.4l-.1 .6M171.3 89.6h.1M171.4 95.8l-.1 .6M171.4 95.8h.1"/>
<path d="M171.6 95.2l-.2 .6M171.6 95.2h.1M171.7 89.1l-.4 .5M171.7 89.1h.1M171.8 89l-.1 .1M171.8 94.6h.1M171.8 94.6l-.2 .6M171.8 89h.1M172 94l-.2 .6M172 94h.1M172.2 88.5l-.4 .5M172.2 88.5h.1"/>
<path d="M172.2 93.4l-.2 .6M172.2 93.4h.1M172.3 88.4l-.1 .1M172.3 88.4h.1M172.4 96l.4 .3M172.5 92.8l-.3 .6M172.5 92.8h.1M172.7 87.9l-.4 .5M172.7 87.9h.1M172.8 87.8l-.1 .1M172.8 87.8h.1M172.8 92.3l-.3 .5"/>
<path d="M172.8 96l-.4 .3M172.8 92.3h.1M173.1 91.7h.1M173.1 91.7l-.3 .6M173.1 93.9l.4 .4M173.2 87.4l-.4 .4M173.2 87.4h.1M173.3 87.3l-.1 .1M173.3 87.3h.1M173.5 91.2l-.4 .5M173.5 91.2h.1M173.5 93.9l-.4 .4"/>
<path d="M173.8 86.9l-.5 .4M173.8 86.9h.1M173.8 90.7l-.3 .5M173.8 90.7h.1M173.9 90.7h.1M173.9 90.7h-.1M173.9 86.8l-.1 .1M173.9 86.8h.1M174.2 90.2h.1M174.2 90.2l-.3 .5M174.3 90.2h-.1M174.3 90.2h.1"/>
<path d="M174.4 86.4l-.5 .4M174.4 86.4h.1M174.5 86.3l-.1 .1M174.5 86.3h.1M175.1 89.3l-.8 .9M175.1 89.3h.1M175.6 88.9l-.5 .4M175.6 88.9h.1M175.7 85.5l-1.2 .8M175.8 85.5h-.1M176.1 88.5l-.5 .4M176.1 88.5h.1"/>
<path d="M176.3 92.3l.3 .3M176.3 85.1l-.5 .4M176.3 85.1h.1M176.4 85.1h-.1M176.4 85.1h.1M176.6 88.1h.1M176.6 88.1l-.5 .4M176.6 92.3l-.3 .3M177.1 87.8l-.5 .3M177.1 87.8h.1M177.2 97.4l.4 .4M177.4 88.8l.3 .3"/>
<path d="M177.6 97.4l-.4 .4M177.7 87.5l-.6 .3M177.7 87.5h.1M177.7 88.8l-.3 .3M178.2 87.2l-.5 .3M178.2 87.2h.1M178.3 84.2l-1.9 .9M178.4 84.2h-.1M178.5 94.4l.4 .4M178.8 86.9h.1M178.8 86.9l-.6 .3M178.9 94.4l-.4 .4"/>
<path d="M179.2 87.9l.3 .3M179.4 86.7h.1M179.4 86.7l-.6 .2M179.5 87.9l-.3 .3M179.9 83.7l-1.5 .5M179.9 83.7h.1M180 86.5h.1M180 86.5l-.6 .2M180.1 97.8l-.1 .9 .1 .9 .4 .9 .6 .7M180.1 97.7v.1M180.2 97.4l-.1 .3M180.2 97.4h.1"/>
<path d="M180.6 86.3h.1M180.6 86.3l-.6 .2M180.7 83.5l-.8 .2M180.7 83.5h.1M181.2 86.2l-.6 .1M181.2 86.2h.1M181.3 87.1l.4 .4M181.4 83.4l-.7 .1M181.4 83.4h.1M181.7 87.1l-.4 .4M181.8 86l-.6 .2M181.8 86h.1"/>
<path d="M181.8 90.3l.4 .3M182.2 83.3l-.8 .1M182.2 90.3l-.4 .3M182.2 83.3h.1M182.8 83.2l-.6 .1M182.8 83.2h.1M183.6 89.3l.3-.1 .3 .3v1.9l-.3 .3-.4-.3zM183.7 85.9l-1.9 .1M183.7 85.9h.1M183.7 85.9h.6M183.7 83.2h-.9M183.7 83.2h.1"/>
<path d="M183.7 83.2h.6M184.3 85.9h.1M184.3 85.9h.6M184.3 83.2h.1M184.3 94.8h-1.3l-1.2 .5-1 .9-.6 1.2M184.3 94.8h.1M184.3 83.2h.2M184.4 94.8l.3 .1M184.5 83.2h.1M184.5 83.2h.6M184.7 94.9h.1M184.7 94.9l.4 .1"/>
<path d="M184.9 85.9h.1M184.9 85.9l.6 .1M185.1 95h.1M185.1 83.2h.1M185.1 95l1.4 .8 .9 1.3M185.1 83.2l.9 .1M185.5 86h.1M185.6 86l1.2 .2M186 83.3h.1M186 83.3l.7 .1M186.6 87.3l.4 .4M186.7 83.4l.1 .1"/>
<path d="M186.8 83.5l.5 .1M186.8 86.2h.1M186.8 86.2l.6 .2M187 87.3l-.4 .4M187.3 83.6h.1M187.4 97.1h.1M187.4 83.6h.1M187.4 97.1l.2 .9v.9M187.4 86.4h.1M187.4 86.4l.6 .2M187.5 83.6h.1M187.5 99.7l-.7 1.3"/>
<path d="M187.5 83.6l.7 .2M187.5 99.7h.1M187.6 99l-.1 .7M187.6 98.9v.1M188 86.6h.1M188 86.6l.6 .2M188.2 83.8h.1M188.2 83.8l.7 .2M188.6 86.8h.1M188.6 86.8l.6 .2M188.8 88.2l.4 .3M188.9 84h.1"/>
<path d="M189 84l.7 .3M189.2 87h.1M189.2 87.1l.5 .2M189.2 88.2l-.4 .3M189.7 84.3h.1M189.7 84.3l1.2 .6M189.7 87.3h.1M189.7 87.3l.6 .3M190.3 87.6h.1M190.3 87.6l.5 .4M190.5 99.2l.4 .4M190.8 88h.1"/>
<path d="M190.8 88l.5 .3M190.8 89.5l.4 .3M190.9 99.2l-.4 .4M190.9 84.9h.1M190.9 84.9l.1 .1M191 85h.1M191.1 85l1.1 .7M191.2 89.5l-.4 .3M191.3 88.3h.1M191.3 88.3l.5 .4M191.8 88.7h.1M191.8 88.7l.3 .2"/>
<path d="M192.1 89.4h.4M192.1 88.9h.1M192.2 88.9l.1 .1M192.2 85.7h.1M192.2 85.7l.7 .4M192.3 89.1v.5M192.3 89h.1M192.4 89h.2M192.5 91.2l.4 .3M192.6 89.9h.4M192.6 89h.1M192.8 89.6v.5"/>
<path d="M192.9 88.9l-.3 .1M192.9 86.1h.1M192.9 86.1l.6 .5M192.9 88.9h.1M192.9 91.2l-.4 .3M193 88.9h-.1M193 88.9h.1M193.1 90.4h.4M193.3 90.2v.4M193.5 86.6h.1M193.5 90.9h.5M193.6 86.6v.1"/>
<path d="M193.6 86.7l.2 .2M193.7 90.7v.5M193.8 86.9h.1M193.9 93.2l.3 .3M193.9 86.9h.1M193.9 88l-.9 .9M193.9 86.9l.1 .3M193.9 88h.1M194 87.9l-.1 .1M194 87.8v.1M194 87.2v.1M194 87.7v.1"/>
<path d="M194 87.3l.1 .1M194 87.7h.1M194.1 90.7l.3 .8M194.1 87.4v.1M194.1 87.5l-.1 .2M194.1 90.7h.1M194.1 90.5v.2M194.1 90.5h.1M194.2 93.2l-.3 .3M194.2 90.2l-.1 .3M194.3 90.2h-.1M194.4 91.5h.1"/>
<path d="M194.4 91.5l.3 .5M194.7 92h.1M194.7 95.4l.4 .4M194.7 92l.3 .5M195 92.6h.1M195 92.6l.3 .5M195.1 95.4l-.4 .4M195.1 89.4l-.8 .8M195.1 89.4h.1M195.2 89.3l-.1 .1M195.2 89.3h.1M195.3 93.1h.1"/>
<path d="M195.3 93.1l.3 .6M195.6 93.7h.1M195.6 93.7l.2 .6M195.6 89.2l-.4 .1M195.6 89.2h.1M195.7 89.2l.2 .1M195.8 94.3h.1M195.8 94.3l.2 .6M195.9 89.3h.1M195.9 89.3l.3 .1M196 94.9h.1M196 94.9l.2 .6"/>
<path d="M196.2 95.5h.1M196.2 95.5l.1 .6M196.2 89.4h.1M196.2 89.4l.4 .6M196.3 96.1h.1M196.3 96.1l.2 1.2M196.5 97.3h.1M196.5 99.9l-.2 1.2M196.5 99.9h.1M196.5 99.8v.1M196.5 97.3v.6M196.5 99.8h.1"/>
<path d="M196.5 99.2v.6M196.5 98h.1M196.5 99.2h.1M196.5 98v.6M196.5 98.6h.1M196.5 98.6v.6M196.6 90h.1M196.7 90l.3 .5M197 90.5v.1M197 90.6l.4 .7M197.4 91.3h.1M197.4 91.3l.4 .7"/>
<path d="M197.8 92h.1M197.8 92l.3 .7M198.1 92.7h.1M198.1 92.7l.2 .6M198.3 93.3h.1M198.3 93.3l.3 .8M198.6 94.1v.1M198.6 94.2l.4 1.4M199 95.6h.1M199 95.6l.1 .8M199.1 96.4h.1M199.1 96.4l.1 .6"/>
<path d="M199.2 97h.1M199.2 97v.7M199.2 97.7v.1M199.2 97.8v.8M199.2 99.3v.9M199.2 99.3h.1M199.2 98.7v.6M199.2 98.6v.1M97.9 100.5v.1M97.9 100.6l.1 .6M98 101.2h.1M98 101.2v.1"/>
<path d="M98 101.3h.1M98 101.3l.1 .6M98.1 101.9h.1M98.1 101.9l.2 .8M98.3 102.7h.1M98.3 102.7v.1M98.3 102.8h.1M98.3 102.8l.8 2.1M99.1 104.9h.1M99.1 104.9l.3 .7M99.4 105.6h.1M99.5 105.6l.2 .6"/>
<path d="M99.7 106.2h.1M99.8 106.2l.7 1.1M100.5 107.3v.1M100.5 107.4l.2 .1M100.6 100.1h.1M100.6 100.1v.1M100.6 100.2h.1M100.6 100.2v.6M100.6 100.8h.1M100.6 100.8l.2 .6M100.7 107.5v.1M100.7 107.6l.5 .1"/>
<path d="M100.8 101.4h.1M100.8 101.4l.1 .6M100.9 102h.1M100.9 102l.2 .6M101.1 102.6h.1M101.1 102.6l.2 .6M101.3 107.7h-.1M101.3 103.2h.1M101.3 103.2l.3 .6M101.6 103.8h.1M101.6 103.8l.2 .5M101.8 104.3h.1"/>
<path d="M101.8 104.3l.3 .6M101.9 101.4l.3 .3M102.1 104.9h.1M102.1 104.9l.4 .5M102.2 101.4l-.3 .3M102.5 105.4h.1M102.5 105.4l.3 .8M102.6 106.7l-.9 .8-.4 .2M102.6 106.6v.1M102.7 106.5l-.1 .1M102.7 109.4v.2M102.7 106.5h.1"/>
<path d="M102.7 109.4h.1M102.7 109.6v.1M102.7 109.7l.1 .2M102.7 103.6l.4 .4M102.8 109.2l-.1 .2M102.8 106.2l-.1 .3M102.8 106.2h.1M102.8 109.2h.1M102.8 109.9h.1M102.8 109.9l.1 .2M102.9 106h.4M102.9 108.9l-.1 .3"/>
<path d="M102.9 110.1h.1M102.9 108.9h.1M102.9 110.1l.8 .7M103.1 105.8v.4M103.1 103.6l-.4 .4M103.3 106.6h.4M103.5 106.3v.5M103.7 108.2l-.8 .7M103.7 108.2h.1M103.7 110.8h.1M103.8 107.1h.4M103.8 110.8h.1"/>
<path d="M103.8 110.8l1.2 .8M104 106.9v.4M104 105.6l.4 .4M104.1 108l-.4 .2M104.1 108h.1M104.3 107.6h.4M104.3 108h-.2M104.3 108h.1M104.3 108h.2M104.4 105.6l-.4 .4M104.5 107.4v.4M104.5 108h.1"/>
<path d="M104.6 108l.1 .1M104.6 101.6l.4 .4M104.7 108.1h.1M104.7 108.1l.2 .2M104.9 108.3h.1M104.9 108.3l.5 .4M105 111.6h.1M105 111.6l.7 .5M105 101.6l-.4 .4M105.4 108.7h.1M105.4 108.7l.5 .3M105.7 112.1h.1"/>
<path d="M105.7 107.3l.4 .4M105.7 112.1l1.4 .7M105.9 109h.1M105.9 109l.5 .4M106.1 107.3l-.4 .4M106.4 109.4h.1M106.5 109.4h.1M106.5 109.4l.5 .3M107 109.7h.1M107 109.7l.5 .3M107.1 104l.4 .4M107.1 112.8h.1"/>
<path d="M107.1 112.8l.6 .2M107.5 104l-.4 .4M107.5 110h.1M107.6 110l.5 .2M107.7 113h.1M107.8 108.6l.3 .4M107.8 113h.1M107.8 113l.7 .3M108.1 103l.4 .3M108.1 110.2v.1M108.1 108.6l-.3 .4M108.1 110.3l.6 .2"/>
<path d="M108.5 103l-.4 .3M108.5 113.3h.1M108.5 113.3l.6 .2M108.7 110.5h.1M108.7 110.5l.6 .2M108.7 106.4l.4 .3M109.1 106.4l-.4 .3M109.1 113.5h.1M109.2 113.5l.7 .1M109.3 110.7h.1M109.3 110.7l.6 .2M109.9 113.6h.1"/>
<path d="M109.9 110.9h.1M109.9 113.6l.7 .2M109.9 110.9l.6 .1M110 109.5l.4 .3M110.4 109.5l-.4 .3M110.4 101.2v.1M110.4 101.3l.3 .2M110.5 111h.1M110.5 111l1.9 .3M110.6 113.8h.1M110.6 113.8l.9 .1M110.7 101.5h.1"/>
<path d="M110.7 101.5l.1 .1M110.8 101.6h.1M110.8 103.9l.4 .4M110.8 101.6l.5 .3M111.1 106.4l.4 .4M111.2 103.9l-.4 .4M111.3 101.9h.1M111.3 101.9l.2 .1M111.5 102h.1M111.5 106.4l-.4 .4M111.5 102l.5 .2M111.5 113.9h.1"/>
<path d="M111.5 113.9l.6 .1M112 102.2h.1M112 102.2l.7 .2M112.1 114h.1M112.2 114h.7M112.4 111.3h.1M112.4 111.3h.6M112.7 102.4h.1M112.8 105.5h.4l.2 .3v1.9l-.3 .3-.4-.4zM112.9 114h.1M113 111.3h.1M113.6 111.3h-.6"/>
<path d="M113.6 111.3h.1M113.8 114h-.9M113.8 114h.1M114.3 111.2l-.7 .1M114.3 111.2h.1M114.4 113.9l-.6 .1M114.4 113.9h.1M114.6 102.1l-.9 .3h-.9M114.6 102.1h.1M114.7 107l.4 .3M114.8 109.7l.3 .4M115.1 107l-.4 .3"/>
<path d="M115.1 109.7l-.3 .4M115.5 111.1l-1.2 .1M115.5 111.1h.1M116.1 110.9l-.6 .2M116.1 110.9h.1M116.3 102.4l.4 .4M116.6 100.3l-.8 1-1.2 .8M116.6 100.2v.1M116.7 102.4l-.4 .4M116.7 106.9l.3 .4M116.7 110.8l-.6 .1M116.7 110.8h.1"/>
<path d="M116.8 113.6l-2.4 .3M116.8 113.6h.1M117 106.9l-.3 .4M117.1 109.1l.3 .4M117.3 110.6l-.6 .2M117.3 110.6h.1M117.4 109.1l-.3 .4M117.5 113.4l-.7 .2M117.6 113.4h-.1M117.9 110.4l-.6 .2M117.9 110.4h.1M118.1 113.2l-.5 .2"/>
<path d="M118.2 113.2h-.1M118.5 110.1h.1M118.5 110.1l-.6 .3M119.1 109.8l-.6 .3M119.1 109.8h.1M119.2 108l.4 .4M119.6 112.6l-1.4 .6M119.6 108l-.4 .4M119.6 112.6h.1M119.6 109.5l-.5 .3M119.6 109.5h.1M119.7 112.6h-.1"/>
<path d="M119.7 112.5v.1M120.1 109.2h.1M120.1 109.2l-.5 .3M120.2 109.2h.1M120.2 109.2h-.1M120.2 112.3l-.5 .2M120.3 112.3h-.1M120.4 112.2l-.1 .1M120.4 112.2h.1M120.7 108.9l-.5 .3M120.7 108.9h.1M120.7 108.8h.1"/>
<path d="M120.7 108.8v.1M121 106.5l.3 .4M121.2 108.5l-.5 .3M121.2 108.5h.1M121.3 106.5l-.3 .4M121.6 108.1l-.4 .4M121.6 108.1h.1M121.6 108v.1M121.6 108h.1M121.7 111.4l-1.3 .8M121.7 111.4h.1M122.1 107.6h.1"/>
<path d="M122.1 107.6l-.5 .4M122.3 104.9l.4 .3M122.5 107.2l-.4 .4M122.5 107.2h.1M122.7 104.9l-.4 .3M122.8 110.6l-1.1 .8M122.8 110.6h.1M123.3 106.2l-.8 1M123.3 106.2h.1M123.5 102.9l.3 .3M123.5 110l-.7 .6M123.5 110h.1"/>
<path d="M123.7 105.7l-.4 .5M123.7 105.7h.1M123.8 102.9l-.3 .3M124 105.2l-.3 .5M124 109.5l-.5 .5M124 105.2h.1M124.1 109.5h-.1M124.2 100.7l.3 .4M124.3 104.6l-.3 .6M124.4 104.6h.1M124.5 100.7l-.3 .4M124.6 104.1l-.2 .5"/>
<path d="M124.6 104h.1M124.9 103.5h.1M124.9 103.5l-.3 .5M125.1 102.9l-.2 .6M125.1 102.9h.1M125.3 102.3l-.2 .6M125.3 102.3h.1M125.5 107.9l-1.4 1.6M125.5 107.9h.1M125.5 101.7h.1M125.5 101.7l-.2 .6M125.6 101.1l-.1 .6"/>
<path d="M125.6 101.1h.1M126.7 106l-1.2 1.9M126.7 106h.1M127 105.3l-.3 .7M127.1 105.3h-.1M127.1 105.2v.1M127.1 105.2h.1M127.4 104.6l-.3 .6M127.4 104.6h.1M127.4 104.5v.1M127.4 104.5h.1M127.6 103.9l-.2 .6"/>
<path d="M127.6 103.9h.1M127.9 103.2l-.3 .7M127.9 103.1v.1M127.9 103v.1M127.9 103h.1M128.1 102.3l-.2 .7M128.1 102.3h.1M128.3 101.6l-.2 .7M128.3 101.5v.1M128.4 100.9l-.1 .6M128.4 100.9h.1M133.2 100.5v.1"/>
<path d="M133.2 100.6l.1 .6M133.3 101.2h.1M133.3 101.2v.1M133.3 101.3h.1M133.3 101.3l.2 .6M133.5 101.9h.1M133.5 101.9l.1 .8M133.6 102.7h.1M133.6 102.7l.1 .1M133.7 102.8h.1M133.7 102.8l.2 .7M133.9 103.5h.1"/>
<path d="M133.9 103.5l.2 .6M134.1 104.1h.1M134.1 104.1l.4 .8M134.5 104.9h.1M134.5 104.9l.3 .7M134.8 105.6h.1M134.8 105.6l1.1 1.8M135.9 100.1h.1M135.9 100.1v.1M135.9 107.4v.1M135.9 100.2h.1M135.9 100.2l.1 .6"/>
<path d="M135.9 107.5h.1M136 100.8h.1M136 100.8l.1 .6M136 107.5l.1 .1M136.1 107.6h.1M136.1 101.4h.1M136.1 101.4l.2 .6M136.2 107.6v.1M136.2 107.7h.3M136.3 102h.1M136.3 102l.1 .6M136.4 102.6h.1"/>
<path d="M136.4 102.6l.3 .6M136.5 107.7h.1M136.7 103.2h.1M136.7 103.2l.2 .6M136.7 107.7h-.2M136.7 107.7h.1M136.9 107.6l-.2 .1M136.9 103.8h.1M136.9 103.8l.3 .5M136.9 107.6h.1M137.1 107.5l-.2 .1M137.1 107.5h.1"/>
<path d="M137.2 104.3h.1M137.2 104.3l.3 .6M137.2 101.4l.4 .3M137.5 104.9h.1M137.5 104.9l.3 .5M137.6 101.4l-.4 .3M137.8 105.4h.1M137.8 105.4l.2 .4M138 106.7l-.9 .8M138 106.6v.1M138 105.8h.1M138 105.8l.1 .2"/>
<path d="M138 106.5v.1M138 106.5h.1M138.1 109.6v.1M138.1 109.7v.2M138.1 103.6l.3 .4M138.1 106h.1M138.1 106v.2M138.1 106.2l-.1 .3M138.1 106.2h.1M138.1 109.9h.1M138.1 109.9l.1 .1M138.2 109l-.1 .6"/>
<path d="M138.2 110h.1M138.2 106h.4M138.2 109h.1M138.2 110l.4 .4M138.4 105.8v.4M138.4 103.6l-.3 .4M138.6 110.4h.1M138.6 110.4l1.1 .8M138.6 106.6h.5M138.8 106.3v.5M139.1 107.1h.4M139.2 108.1l-1 .9"/>
<path d="M139.2 108.1h.1M139.3 106.9v.4M139.4 105.6l.3 .4M139.5 108l-.3 .1M139.6 108l.5 .1M139.6 108h-.1M139.6 107.6h.4M139.7 111.2h.1M139.7 111.2l.1 .1M139.7 105.6l-.3 .4M139.8 111.3h.1M139.8 111.3l.5 .3"/>
<path d="M139.8 107.4v.4M140 101.6l.3 .4M140.1 108.1h.1M140.1 108.1l.2 .2M140.3 108.3h.1M140.3 108.3l1 .7M140.3 111.6h.1M140.3 111.6l1.3 .8M140.3 101.6l-.3 .4M141.1 107.3l.3 .4M141.3 109h.1M141.3 109l.5 .4"/>
<path d="M141.4 107.3l-.3 .4M141.6 112.4h.1M141.7 112.4h.1M141.8 112.4l.5 .3M141.8 109.4h.1M141.8 109.4l.5 .3M142.3 112.7h.1M142.3 109.7h.1M142.3 112.7l.8 .3M142.3 109.7l1.1 .5M142.4 104l.4 .4M142.8 104l-.4 .4"/>
<path d="M143.1 108.6l.3 .4M143.1 113h.1M143.2 113l1.3 .5M143.4 103l.4 .3M143.4 110.2h.1M143.4 110.2l.1 .1M143.4 108.6l-.3 .4M143.5 110.3h.1M143.5 110.3l.5 .2M143.8 103l-.4 .3M144 110.5h.1M144 110.5l1.2 .4"/>
<path d="M144.1 106.4l.3 .3M144.4 106.4l-.3 .3M144.5 113.5h.1M144.6 113.5h.1M144.6 113.5l.7 .2M145.2 110.9h.1M145.2 110.9l.6 .1M145.3 109.5l.4 .3M145.3 113.7h.1M145.4 113.7l.6 .1M145.7 109.5l-.4 .3M145.8 111h.1"/>
<path d="M145.9 111h.1M145.9 111l.6 .1M146 113.8h.1M146 113.8l.7 .1M146.1 103.9l.4 .4M146.5 111.1h.1M146.5 106.4l.3 .4M146.5 111.1l.6 .1M146.5 103.9l-.4 .4M146.7 113.9h.1M146.7 113.9l.9 .1M146.8 106.4l-.3 .4"/>
<path d="M147 102.1h.1M147 102.1l.5 .2M147.1 111.2h.1M147.1 111.2l.6 .1M147.5 102.3h.1M147.5 102.3l.4 .1M147.6 114h.1M147.6 114h.6M147.7 111.3h.1M147.7 111.3h.6M147.9 102.4h.1M148.2 105.5h.3l.3 .3v1.9l-.3 .3-.4-.4z"/>
<path d="M148.2 114h.1M148.3 114h.1M148.3 111.3h.1M148.4 111.3h.1M148.4 114h.1M149 114h-.6M149 114h.1M149.2 102.4h-1.3M149.2 102.3v.1M150.1 107l.3 .3M150.1 109.7l.4 .4M150.2 111.2l-1.8 .1"/>
<path d="M150.2 111.2h.1M150.4 107l-.3 .3M150.5 109.7l-.4 .4M150.8 111.1l-.6 .1M150.9 111.1h-.1M150.9 101.6l-.8 .5-.9 .2M150.9 101.5v.1M151.3 113.7l-2.3 .3M151.3 113.7h.1M151.4 101l-.5 .5M151.4 110.9l-.5 .2M151.4 110.9h.1"/>
<path d="M151.5 101h-.1M151.5 110.9h-.1M151.5 110.9h.1M151.6 102.4l.4 .4M151.9 100.3l-.4 .7M152 100.2l-.1 .1M152 102.4l-.4 .4M152 106.9l.4 .4M152 113.6l-.7 .1M152 113.6h.1M152.1 110.8h.1M152.1 110.8l-.6 .1"/>
<path d="M152.4 106.9l-.4 .4M152.4 109.1l.4 .4M152.7 110.6l-.6 .2M152.7 110.6h.1M152.7 113.4l-.7 .2M152.8 109.1l-.4 .4M152.8 113.4h-.1M153.5 113.2l-.7 .2M153.5 113.2h.1M153.6 113.1l-.1 .1M153.6 113.1h.1M153.8 110.1h.1"/>
<path d="M153.8 110.1l-1.1 .5M154.2 112.9l-.6 .2M154.2 112.9h.1M154.4 109.8l-.6 .3M154.4 109.8h.1M154.5 108l.4 .4M154.9 108l-.4 .4M154.9 109.5l-.5 .3M154.9 109.5h.1M155 109.5h.1M155 109.5h-.1M155 112.6l-.8 .3"/>
<path d="M155 112.5v.1M155.5 109.2l-.5 .3M155.5 109.2h.1M156 108.9l-.5 .3M156 108.9h.1M156 108.8h.1M156 108.8v.1M156.2 111.9l-1.2 .6M156.3 111.9h-.1M156.3 106.5l.3 .4M156.5 108.5h.1M156.5 108.5l-.5 .3"/>
<path d="M156.6 106.5l-.3 .4M156.9 111.5l-.6 .4M156.9 111.5h.1M157 108.1l-.5 .4M157 108.1h.1M157 108h.1M157 108v.1M157.4 107.6h.1M157.4 107.6l-.4 .4M157.7 104.9l.3 .3M157.9 107.2l-.5 .4M157.9 107.2h.1"/>
<path d="M158 104.9l-.3 .3M158.3 106.7l-.4 .5M158.3 106.7h.1M158.7 106.2h.1M158.7 106.2l-.4 .5M158.8 102.9l.4 .3M159 105.7l-.3 .5M159 105.7h.1M159.2 102.9l-.4 .3M159.3 109.6l-2.4 1.9M159.3 109.6h.1M159.4 105.2l-.4 .5"/>
<path d="M159.4 109.5l-.1 .1M159.4 105.2h.1M159.4 109.5h.1M159.5 100.7l.4 .4M159.7 104.6l-.3 .6M159.7 104.6h.1M159.9 100.7l-.4 .4M160 104.1l-.3 .5M160 104h.1M160.2 103.5h.1M160.2 103.5l-.2 .5M160.4 102.9l-.2 .6"/>
<path d="M160.5 102.9h.1M160.6 102.3l-.1 .6M160.7 102.3h.1M160.8 101.7h.1M160.8 101.7l-.1 .6M160.9 107.8l-1.5 1.7M160.9 107.8h.1M161 101.1l-.2 .6M161 101.1h.1M162 106l-1.1 1.8M162 106h.1M162.1 105.9l-.1 .1"/>
<path d="M162.1 105.8v.1M162.7 104.5l-.6 1.3M162.7 104.5h.1M163 103.9l-.3 .6M163 103.9h.1M163.2 103.2l-.2 .7M163.2 103.1v.1M163.3 103l-.1 .1M163.3 103h.1M163.5 102.3l-.2 .7M163.5 102.3h.1M163.6 101.6l-.1 .7"/>
<path d="M163.6 101.5v.1M163.7 100.9l-.1 .6M163.7 100.9h.1M163.8 100.2l-.1 .7M163.8 100.2h.1M168.5 100.5v.1M168.5 100.6l.1 .6M168.6 101.2h.1M168.6 101.2l.1 .1M168.7 101.3h.1M168.7 101.3l.1 .6M168.8 101.9h.1"/>
<path d="M168.8 101.9l.2 .8M169 102.7h.1M169 102.7l.2 .8M169.2 103.5h.1M169.2 103.5l.2 .6M169.4 104.1h.1M169.4 104.1l.4 .8M169.8 104.9h.1M169.8 104.9l.6 1.3M170.4 106.2h.1M170.4 106.2l.7 1.1M171.1 107.3l.1 .1"/>
<path d="M171.2 107.4l.2 .1M171.2 100.1v.1M171.2 100.1h.1M171.2 100.2h.1M171.2 100.2l.1 .6M171.3 100.8h.1M171.3 100.8l.1 .6M171.4 107.5v.1M171.4 107.6h.1M171.4 101.4h.1M171.4 101.4l.2 .6M171.5 107.6h.1"/>
<path d="M171.5 107.6l.2 .1M171.6 102h.1M171.6 102l.2 .6M171.7 107.7h.1M171.7 107.7h.2M171.8 102.6h.1M171.8 102.6l.2 .6M172 107.7h-.1M172 103.2h.1M172 103.2l.2 .6M172.1 107.7h-.1M172.2 107.7h-.1"/>
<path d="M172.2 103.8h.1M172.2 103.8l.3 .5M172.3 107.6l-.1 .1M172.3 107.6h.1M172.5 104.3h.1M172.5 104.3l.3 .6M172.5 101.4l.4 .3M172.8 104.9h.1M172.8 104.9l.3 .5M172.9 101.4l-.4 .3M173.1 105.4h.1M173.1 105.4l.3 .6"/>
<path d="M173.2 106.8l-.9 .8M173.2 106.7v.1M173.4 106.5l-.2 .2M173.4 109.4v.2M173.4 106.5h.1M173.4 109.4h.1M173.4 109.6v.1M173.4 109.7l.2 .4M173.4 103.6l.4 .4M173.4 106h.1M173.4 106v.2M173.4 109.2v.2"/>
<path d="M173.4 106.2v.3M173.4 106.2h.1M173.4 109.2h.1M173.5 106h.5M173.6 108.9l-.2 .3M173.6 110.1h.1M173.6 108.9h.1M173.6 110.1l.3 .3M173.7 105.8v.4M173.8 103.6l-.4 .4M173.9 110.4h.1M173.9 110.4l.5 .4"/>
<path d="M174 106.6h.4M174.2 106.3v.5M174.3 108.2l-.7 .7M174.4 108.2h-.1M174.4 110.8h.1M174.4 107.1h.5M174.5 110.8h.1M174.5 110.8l1.9 1.3M174.6 108l-.2 .2M174.6 108h.1M174.7 106.9v.4M174.7 105.6l.4 .4"/>
<path d="M174.8 108h-.2M174.8 108h.2M174.8 108h.1M174.9 107.6h.5M175 108h.1M175.1 105.6l-.4 .4M175.1 108h.1M175.2 107.4v.4M175.2 108h.1M175.3 108l.2 .2M175.3 101.6l.4 .4M175.5 108.2h.1"/>
<path d="M175.5 108.2l.1 .1M175.6 108.3h.1M175.6 108.3l.5 .4M175.7 101.6l-.4 .4M176.1 108.7h.1M176.1 108.7l.5 .3M176.4 112.1h.1M176.4 107.3l.4 .4M176.4 112.1l.7 .3M176.6 109h.1M176.6 109l.5 .4M176.8 107.3l-.4 .4"/>
<path d="M177.1 112.4h.1M177.1 112.4l.7 .4M177.1 109.4h.1M177.1 109.4l.6 .3M177.7 109.7h.1M177.7 109.7l.5 .3M177.8 104l.3 .4M177.8 112.8h.1M177.8 112.8l.5 .2M178.1 104l-.3 .4M178.2 110h.1M178.2 110l.6 .2"/>
<path d="M178.3 113h.1M178.4 113l.8 .3M178.4 108.6l.4 .4M178.8 103l.3 .3M178.8 110.2h.1M178.8 108.6l-.4 .4M178.8 110.3l.6 .2M179.1 103l-.3 .3M179.2 113.3h.1M179.2 113.3l.7 .2M179.4 110.5h.1M179.4 110.5l.6 .2"/>
<path d="M179.4 106.4l.4 .3M179.8 106.4l-.4 .3M179.9 113.5h.1M179.9 113.5l.8 .2M180 110.7h.1M180 110.7l.6 .2M180.6 110.9h.1M180.6 110.9l.6 .1M180.7 109.5l.3 .3M180.7 113.7h.1M180.7 113.7l.7 .1M181 109.5l-.3 .3"/>
<path d="M181.1 101.2v.1M181.1 101.3l.7 .5M181.2 111h.1M181.2 111l.6 .1M181.4 113.8h.1M181.4 113.8l.8 .1M181.5 103.9l.3 .4M181.8 111.1h.1M181.8 101.8h.1M181.8 106.4l.4 .4M181.8 111.1l1.9 .2M181.8 101.8l1.4 .6 1.5-.1"/>
<path d="M181.8 103.9l-.3 .4M182.2 106.4l-.4 .4M182.2 113.9h.1M182.2 113.9l.6 .1M182.8 114h.1M182.8 114h.9M183.5 105.5h.4l.2 .3v1.9l-.3 .3-.4-.4zM183.7 111.3h.1M183.7 114h.1M184.3 111.3h-.6M184.3 111.3h.1M184.3 114h-.6"/>
<path d="M184.3 114h.1M184.5 114h-.2M184.5 114h.1M184.7 102.3h.1M184.9 111.2l-.6 .1M184.9 111.2h.1M185.1 102.2l-.4 .1M185.1 113.9l-.6 .1M185.1 102.2h.1M185.1 113.9h.1M185.4 107l.4 .3M185.4 109.7l.4 .4"/>
<path d="M185.5 111.2h-.6M185.6 111.2h-.1M185.8 101.9l-.7 .3M185.8 107l-.4 .3M185.8 109.7l-.4 .4M185.8 101.9h.1M186 113.8l-.9 .1M186 113.8h.1M186.8 101l-1 .9M186.8 110.9l-1.2 .3M186.8 101h.1M186.8 110.9h.1"/>
<path d="M187 102.4l.3 .4M187.3 102.4l-.3 .4M187.3 106.9l.4 .4M187.3 113.6l-1.3 .2M187.4 113.6h-.1M187.4 110.8l-.6 .1M187.4 110.8h.1M187.5 113.6h-.1M187.5 113.6h.1M187.7 106.9l-.4 .4M187.7 109.1l.4 .4M188 110.6l-.6 .2"/>
<path d="M188 110.6h.1M188.1 109.1l-.4 .4M188.2 113.4l-.7 .2M188.2 113.4h.1M188.6 110.4l-.6 .2M188.6 110.4h.1M188.9 113.1l-.7 .3M189 113.1h-.1M189.2 110.1h.1M189.2 110.1l-.6 .3M189.5 112.9l-.5 .2M189.5 112.9h.1"/>
<path d="M189.7 109.8l-.5 .3M189.7 109.8h.1M189.9 108l.3 .4M190.2 112.6l-.7 .3M190.2 108l-.3 .4M190.2 112.6h.1M190.3 109.5l-.6 .3M190.3 109.5h.1M190.8 109.2l-.5 .3M190.8 109.2h.1M190.9 112.3l-.7 .3M190.9 112.3h.1"/>
<path d="M191 112.2l-.1 .1M191.1 112.2h-.1M191.3 108.9l-.5 .3M191.3 108.9h.1M191.3 108.8h.1M191.3 108.8v.1M191.6 106.5l.4 .4M191.8 108.5h.1M191.8 108.5l-.5 .3M192 106.5l-.4 .4M192.2 111.5l-1.1 .7M192.2 111.5h.1"/>
<path d="M192.3 108.1h.1M192.3 108.1l-.5 .4M192.3 108h.1M192.3 108v.1M192.3 111.4l-.1 .1M192.4 111.4h-.1M192.8 107.6h.1M192.8 107.6l-.5 .4M193 104.9l.4 .3M193.2 107.2l-.4 .4M193.2 107.2h.1M193.4 104.9l-.4 .3"/>
<path d="M193.5 110.6l-1.1 .8M193.5 110.6h.1M193.6 110.5l-.1 .1M193.6 110.5h.1M193.6 106.7l-.4 .5M193.6 106.7h.1M194 106.2l-.4 .5M194 106.2h.1M194.1 102.9l.4 .3M194.1 110l-.5 .5M194.2 110h-.1M194.4 105.7l-.4 .5"/>
<path d="M194.4 105.7h.1M194.5 102.9l-.4 .3M194.6 109.6l-.4 .4M194.6 109.6h.1M194.7 105.2l-.3 .5M194.7 105.2h.1M194.9 100.7l.3 .4M195 104.6l-.3 .6M195 104.6h.1M195.2 100.7l-.3 .4M195.3 104.1l-.3 .5M195.3 104h.1"/>
<path d="M195.6 103.5h.1M195.6 103.5l-.3 .5M195.8 102.9l-.2 .6M195.8 102.9h.1M196 102.3h.1M196 102.3l-.2 .6M196.1 107.9l-1.5 1.7M196.1 107.9h.1M196.2 101.7h.1M196.2 101.7l-.2 .6M196.2 107.8l-.1 .1M196.2 107.8h.1"/>
<path d="M196.3 101.1l-.1 .6M196.3 101.1h.1M197.4 105.9l-1.2 1.9M197.4 105.8v.1M197.7 105.3l-.3 .5M197.7 105.3h.1M197.8 105.2l-.1 .1M197.8 105.2h.1M198 104.6l-.2 .6M198 104.6h.1M198.1 104.5l-.1 .1M198.1 104.5h.1"/>
<path d="M198.3 103.9l-.2 .6M198.3 103.9h.1M198.5 103.2l-.2 .7M198.6 103.1l-.1 .1M198.6 103v.1M198.6 103h.1M199 101.6l-.4 1.4M199 101.5v.1M199.1 100.9l-.1 .6M199.1 100.9h.1M199.2 100.2l-.1 .7M199.2 100.2h.1"/>
<path d="M89 133.5h1.2v1.3h-1.2zM90 131.8h.5M90.1 126.8l.4 .4M90.3 131.6v.4M90.5 126.8l-.4 .4M90.5 120.3h.1M90.5 120.3v.1M90.5 120.4l.1 .1M90.5 120.4h.1M90.6 120.5h.1M90.6 120.5v.1M90.6 120.6h.1"/>
<path d="M90.6 120.6v.1M90.6 120.7h.1M90.7 120.7h.1M90.7 120.7v.1M90.7 120.8h.1M90.7 120.8v.1M90.7 120.9h.1M90.8 120.9h.1M90.8 121h.1M90.9 121h.1M91 121.1h.1M91.1 121.1h.1"/>
<path d="M91.1 121.1l.1 .1M91.2 121.2h.1M91.3 121.2h.1M91.4 121.2h.1M91.4 121.2h114.1M103.6 122.9l.5-.1 .3 .4v.5l-.2 .3h-.6M105.2 123.9v.2M105.2 122.9v.2M126.7 126.2l.7-.2 .3 .2 .1 .3-1.2 1.3h1.2M129.9 126.8l.3-.2 .4 .1 .1 1.1M129.9 126v1.8M131.6 126.7l.5-.1 .3 .4v.5l-.3 .3h-.5l-.1-.3v-.5z"/>
<path d="M133.2 126v1.6l.2 .2M134 127.2l.9-.1-.1-.4-.5-.1-.3 .3 .1 .9h.7M135.1 129.5h1.3M136.3 126.7l-.5-.1-.2 .3 .1 .3 .6 .1v.5h-.7M136.9 125.8a2.07 2.07 0 0 1 0 2.7M137.5 133.9l.2-.1 .4 .1 .1 1.1M138.6 128.9l.5-.5v1.8M138.6 130.2h1M139.1 133.9l.2-.1 .6 .1 .1 .7-.2 .3-.5 .1-.2-.2zM139.2 131.6l.2-.2 .5 .1 .1 1.1M140.5 133.8h.7M140.6 129.2l-.3-.4 .1-.2 .2-.2 .6 .1 .1 .3-.1 .2-.7 .3-.2 .2v.4l.3 .3 .6-.1 .1-.2v-.4l-.3-.3"/>
<path d="M140.7 133.2v1.5l.5 .3M140.8 131.6l.3-.2 .5 .2 .1 .7-.2 .2-.4 .1-.3-.2zM142.2 131.4h.7M142.4 130.8v1.5l.5 .3M143.1 133.9l.5-.1 .4 .3v.5l-.2 .3h-.7M143.1 133.8v1.8M144.1 129.1l-.5-.1-.2 .3 .1 .2 .6 .2v.4h-.7M144.8 133.2v1.5l.2 .3M144.8 131.5l.6-.1 .3 .3v.6l-.2 .2h-.7M144.8 131.4v1.8M144.9 128.4v1.6l.3 .2M145.7 133.9h.7l.1 1.1"/>
<path d="M145.9 129.2l.2-.2 .5 .2 .1 .7-.1 .2-.5 .1-.2-.2zM146.5 130.8v1.5l.2 .3M146.5 134.2l-.6 .1a.35 .35 0 0 0-.3 .3 .35 .35 0 0 0 .3 .4l.6-.1M147.1 133.8h.7M147.2 129h.7M147.3 133.2v1.5l.5 .3M147.4 131.5h.7l.1 1.1M147.5 128.4v1.6l.4 .2M148.2 131.8l-.6 .1a.35 .35 0 0 0-.3 .4 .35 .35 0 0 0 .3 .3l.6-.1M148.3 134.4l.8-.2v-.3l-.6-.1-.2 .2 .1 .9h.7M148.8 131.4h.7M149.1 130.8v1.5l.4 .3"/>
<path d="M149.1 129.1l-.4-.1-.3 .3 .1 .2 .6 .2v.4h-.7M149.8 128.2a2.07 2.07 0 0 1 0 2.7M150 132l.9-.2-.1-.3-.5-.1-.3 .3 .1 .8h.7M150.7 133.9l-.5-.1-.4 .3v.5l.2 .3h.7M150.7 133.2v1.8M151.4 132.9a2.07 2.07 0 0 1 0 2.8M152.4 131.5l-.5-.1-.4 .3v.6l.2 .2h.7M152.4 130.8v1.8M153.1 130.5a2.07 2.07 0 0 1 0 2.8M205.6 121.2h.1M205.7 121.2h-.1M205.7 121.2h.1"/>
<path d="M205.8 121.2h-.1M205.8 121.2h.1M205.9 121.1h.1M205.9 121.1l-.1 .1M206 121.1h-.1M206 121.1h.1M206.1 121.1h-.1M206.1 121v.1M206.1 121h.1M206.2 121h-.1M206.2 120.9h.1M206.3 120.9h-.1"/>
<path d="M206.3 120.9h.1M206.3 120.8h.1M206.3 120.8v.1M206.3 120.7v.1M206.4 120.7h.1M206.4 120.6v.1M206.4 120.6h.1M206.4 120.5h.1M206.4 120.5v.1M206.5 120.4h.1M206.5 120.4l-.1 .1M206.5 120.3v.1"/>
<path d="M206.5 120.3h.1"/>
<circle cx="113.2" cy="19.8" r=".45"/>
<circle cx="148.5" cy="19.8" r=".45"/>
<circle cx="183.8" cy="19.8" r=".45"/>
<circle cx="113.1" cy="36" r=".45"/>
<circle cx="148.4" cy="36" r=".45"/>
<circle cx="183.8" cy="36" r=".45"/>
<circle cx="113.2" cy="55.1" r=".45"/>
<circle cx="148.5" cy="55.1" r=".45"/>
<circle cx="183.8" cy="55.1" r=".45"/>
<circle cx="113.1" cy="71.4" r=".45"/>
<circle cx="148.4" cy="71.4" r=".45"/>
<circle cx="183.8" cy="71.4" r=".45"/>
<circle cx="113.2" cy="90.5" r=".45"/>
<circle cx="148.5" cy="90.5" r=".45"/>
<circle cx="183.8" cy="90.5" r=".45"/>
<circle cx="113.1" cy="106.7" r=".45"/>
<circle cx="148.4" cy="106.7" r=".45"/>
<circle cx="183.8" cy="106.7" r=".45"/>
<circle cx="90" cy="129.4" r=".45"/>
</g>
<g fill="#000" stroke="#000" stroke-width=".21">
<circle cx="91.3" cy="5.3" r=".05"/>
<circle cx="101.8" cy="36.8" r=".05"/>
<circle cx="103" cy="39.5" r=".05"/>
<circle cx="113.1" cy="31.7" r=".05"/>
<circle cx="137.2" cy="36.8" r=".05"/>
<circle cx="138.3" cy="39.5" r=".05"/>
<circle cx="147.9" cy="31.7" r=".05"/>
<circle cx="172.5" cy="36.8" r=".05"/>
<circle cx="173.7" cy="39.5" r=".05"/>
<circle cx="183.4" cy="31.7" r=".05"/>
<circle cx="101.8" cy="72.1" r=".05"/>
<circle cx="103" cy="74.8" r=".05"/>
<circle cx="113.3" cy="67.1" r=".05"/>
<circle cx="137.2" cy="72.1" r=".05"/>
<circle cx="138.3" cy="74.8" r=".05"/>
<circle cx="148.7" cy="67.1" r=".05"/>
<circle cx="172.5" cy="72.1" r=".05"/>
<circle cx="173.7" cy="74.8" r=".05"/>
<circle cx="184.6" cy="67" r=".05"/>
<circle cx="101.8" cy="107.5" r=".05"/>
<circle cx="103" cy="110.2" r=".05"/>
<circle cx="114.4" cy="102.2" r=".05"/>
<circle cx="137.2" cy="107.5" r=".05"/>
<circle cx="138.3" cy="110.2" r=".05"/>
<circle cx="150.1" cy="102.1" r=".05"/>
<circle cx="172.5" cy="107.5" r=".05"/>
<circle cx="173.7" cy="110.2" r=".05"/>
<circle cx="186" cy="101.8" r=".05"/>
</g>
<path d="M93.2 10.6h1.9v2h-1.9zM201.9 10.6h1.9v2h-1.9zM93.2 113.9h1.9v2h-1.9zM201.9 113.9h1.9v2h-1.9z" fill="none" stroke="#000" stroke-width=".27"/>
<use href="#words"/>
</svg>
